VERSION 5.7 ;
  NOWIREEXTENSIONATPIN ON ;
  DIVIDERCHAR "/" ;
  BUSBITCHARS "[]" ;
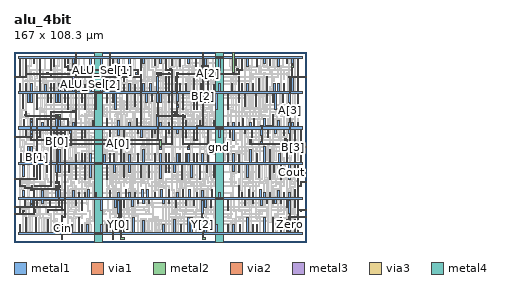
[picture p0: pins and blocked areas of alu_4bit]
MACRO alu_4bit
  CLASS BLOCK ;
  FOREIGN alu_4bit ;
  ORIGIN 1.900 4.000 ;
  SIZE 167.000 BY 108.300 ;
  PIN vdd
    USE POWER ;
    PORT
      LAYER metal1 ;
        RECT 1.200 81.600 2.000 86.200 ;
        RECT 4.400 81.600 5.200 86.200 ;
        RECT 7.600 81.600 8.400 86.200 ;
        RECT 12.400 81.600 13.200 90.200 ;
        RECT 15.600 81.600 16.400 85.800 ;
        RECT 18.800 81.600 19.600 86.200 ;
        RECT 20.400 81.600 21.200 86.200 ;
        RECT 23.600 81.600 24.400 86.200 ;
        RECT 26.800 81.600 27.600 86.200 ;
        RECT 31.600 81.600 32.400 90.200 ;
        RECT 33.200 81.600 34.000 86.200 ;
        RECT 38.000 81.600 38.800 85.800 ;
        RECT 41.200 81.600 42.000 86.200 ;
        RECT 47.600 81.600 48.400 86.200 ;
        RECT 50.800 81.600 51.600 85.800 ;
        RECT 57.200 81.600 58.000 90.200 ;
        RECT 60.400 81.600 61.200 85.800 ;
        RECT 63.600 81.600 64.400 86.200 ;
        RECT 66.800 81.600 67.600 85.800 ;
        RECT 70.000 81.600 70.800 86.200 ;
        RECT 71.600 81.600 72.400 86.200 ;
        RECT 75.400 81.600 76.200 86.200 ;
        RECT 79.600 81.600 80.400 90.200 ;
        RECT 84.400 81.600 85.200 90.200 ;
        RECT 86.000 81.600 86.800 90.200 ;
        RECT 90.200 81.600 91.000 86.200 ;
        RECT 92.400 81.600 93.200 86.200 ;
        RECT 95.600 81.600 96.400 86.200 ;
        RECT 100.400 81.600 101.200 89.000 ;
        RECT 104.200 81.600 105.000 86.200 ;
        RECT 108.400 81.600 109.200 90.200 ;
        RECT 111.600 81.600 112.400 85.800 ;
        RECT 114.800 81.600 115.600 86.200 ;
        RECT 121.800 81.600 122.600 86.200 ;
        RECT 126.000 81.600 126.800 90.200 ;
        RECT 127.600 81.600 128.400 86.200 ;
        RECT 130.800 81.600 131.600 86.200 ;
        RECT 134.000 81.600 134.800 86.200 ;
        RECT 137.200 81.600 138.000 89.000 ;
        RECT 142.000 81.600 142.800 90.200 ;
        RECT 146.200 81.600 147.000 86.200 ;
        RECT 148.400 81.600 149.200 86.200 ;
        RECT 151.600 81.600 152.400 86.200 ;
        RECT 156.400 81.600 157.200 90.200 ;
        RECT 159.600 81.600 160.400 90.200 ;
        RECT 0.400 80.400 162.800 81.600 ;
        RECT 2.800 72.200 3.600 80.400 ;
        RECT 6.000 75.800 6.800 80.400 ;
        RECT 7.600 75.800 8.400 80.400 ;
        RECT 10.800 71.800 11.600 80.400 ;
        RECT 17.200 75.800 18.000 80.400 ;
        RECT 18.800 75.800 19.600 80.400 ;
        RECT 22.000 75.800 22.800 80.400 ;
        RECT 23.600 75.800 24.400 80.400 ;
        RECT 26.800 75.800 27.600 80.400 ;
        RECT 28.400 71.800 29.200 80.400 ;
        RECT 33.200 75.800 34.000 80.400 ;
        RECT 36.400 75.800 37.200 80.400 ;
        RECT 38.000 71.800 38.800 80.400 ;
        RECT 44.400 71.800 45.200 80.400 ;
        RECT 50.800 75.800 51.600 80.400 ;
        RECT 54.000 75.800 54.800 80.400 ;
        RECT 55.600 71.800 56.400 80.400 ;
        RECT 62.000 71.800 62.800 80.400 ;
        RECT 66.800 73.000 67.600 80.400 ;
        RECT 70.000 75.800 70.800 80.400 ;
        RECT 73.200 75.800 74.000 80.400 ;
        RECT 76.400 76.200 77.200 80.400 ;
        RECT 79.600 75.800 80.400 80.400 ;
        RECT 81.200 75.800 82.000 80.400 ;
        RECT 86.000 75.800 86.800 80.400 ;
        RECT 87.600 75.800 88.400 80.400 ;
        RECT 90.800 76.200 91.600 80.400 ;
        RECT 94.000 71.800 94.800 80.400 ;
        RECT 100.400 71.800 101.200 80.400 ;
        RECT 102.000 71.800 102.800 80.400 ;
        RECT 106.200 75.800 107.000 80.400 ;
        RECT 109.000 75.800 109.800 80.400 ;
        RECT 113.200 71.800 114.000 80.400 ;
        RECT 119.600 71.800 120.400 80.400 ;
        RECT 126.000 75.800 126.800 80.400 ;
        RECT 129.200 73.000 130.000 80.400 ;
        RECT 135.600 73.000 136.400 80.400 ;
        RECT 142.000 75.800 142.800 80.400 ;
        RECT 145.200 75.800 146.000 80.400 ;
        RECT 146.800 71.800 147.600 80.400 ;
        RECT 151.000 75.800 151.800 80.400 ;
        RECT 154.800 75.800 155.600 80.400 ;
        RECT 159.600 71.800 160.400 80.400 ;
        RECT 1.800 41.600 2.600 46.200 ;
        RECT 6.000 41.600 6.800 50.200 ;
        RECT 7.600 41.600 8.400 50.200 ;
        RECT 12.400 41.600 13.200 46.200 ;
        RECT 15.600 41.600 16.400 46.200 ;
        RECT 18.800 41.600 19.600 46.200 ;
        RECT 23.600 41.600 24.400 49.000 ;
        RECT 26.800 41.600 27.600 50.200 ;
        RECT 33.200 41.600 34.000 45.800 ;
        RECT 36.400 41.600 37.200 46.200 ;
        RECT 38.000 41.600 38.800 46.200 ;
        RECT 41.200 41.600 42.000 46.200 ;
        RECT 49.200 41.600 50.000 45.800 ;
        RECT 52.400 41.600 53.200 46.200 ;
        RECT 54.600 41.600 55.400 46.200 ;
        RECT 58.800 41.600 59.600 50.200 ;
        RECT 60.400 41.600 61.200 46.200 ;
        RECT 63.600 41.600 64.400 45.800 ;
        RECT 68.400 41.600 69.200 46.200 ;
        RECT 71.600 41.600 72.400 49.000 ;
        RECT 78.000 41.600 78.800 46.200 ;
        RECT 81.200 41.600 82.000 46.200 ;
        RECT 84.400 41.600 85.200 46.200 ;
        RECT 86.000 41.600 86.800 46.200 ;
        RECT 90.800 41.600 91.600 46.200 ;
        RECT 92.400 41.600 93.200 46.200 ;
        RECT 95.600 41.600 96.400 46.200 ;
        RECT 97.200 41.600 98.000 46.200 ;
        RECT 100.400 41.600 101.200 46.200 ;
        RECT 102.000 41.600 102.800 46.200 ;
        RECT 105.200 41.600 106.000 46.200 ;
        RECT 108.400 41.600 109.200 46.200 ;
        RECT 119.600 41.600 120.400 49.000 ;
        RECT 122.800 41.600 123.600 46.200 ;
        RECT 126.000 41.600 126.800 45.800 ;
        RECT 132.400 41.600 133.200 49.000 ;
        RECT 136.200 41.600 137.000 46.200 ;
        RECT 140.400 41.600 141.200 50.200 ;
        RECT 143.600 41.600 144.400 49.000 ;
        RECT 149.000 41.600 149.800 46.200 ;
        RECT 153.200 41.600 154.000 50.200 ;
        RECT 158.000 41.600 158.800 50.200 ;
        RECT 161.200 41.600 162.000 46.200 ;
        RECT 0.400 40.400 162.800 41.600 ;
        RECT 3.000 39.800 3.800 40.400 ;
        RECT 2.800 33.200 3.800 39.800 ;
        RECT 9.000 33.200 10.000 40.400 ;
        RECT 12.400 31.800 13.200 40.400 ;
        RECT 16.600 35.800 17.400 40.400 ;
        RECT 18.800 35.800 19.600 40.400 ;
        RECT 22.000 35.800 22.800 40.400 ;
        RECT 23.600 35.800 24.400 40.400 ;
        RECT 26.800 35.800 27.600 40.400 ;
        RECT 29.000 35.800 29.800 40.400 ;
        RECT 33.200 31.800 34.000 40.400 ;
        RECT 38.000 31.800 38.800 40.400 ;
        RECT 41.200 33.000 42.000 40.400 ;
        RECT 50.800 31.800 51.600 40.400 ;
        RECT 55.000 35.800 55.800 40.400 ;
        RECT 60.400 33.000 61.200 40.400 ;
        RECT 63.600 35.800 64.400 40.400 ;
        RECT 70.000 33.000 70.800 40.400 ;
        RECT 74.800 33.000 75.600 40.400 ;
        RECT 81.200 32.200 82.000 40.400 ;
        RECT 84.400 35.800 85.200 40.400 ;
        RECT 86.000 35.800 86.800 40.400 ;
        RECT 89.200 35.800 90.000 40.400 ;
        RECT 93.400 31.800 94.200 40.400 ;
        RECT 98.800 33.000 99.600 40.400 ;
        RECT 103.600 31.800 104.400 40.400 ;
        RECT 107.800 35.800 108.600 40.400 ;
        RECT 111.600 33.000 112.400 40.400 ;
        RECT 122.800 36.200 123.600 40.400 ;
        RECT 126.000 35.800 126.800 40.400 ;
        RECT 130.800 33.000 131.600 40.400 ;
        RECT 137.200 33.000 138.000 40.400 ;
        RECT 143.600 31.800 144.400 40.400 ;
        RECT 145.800 35.800 146.600 40.400 ;
        RECT 150.000 31.800 150.800 40.400 ;
        RECT 154.800 31.800 155.600 40.400 ;
        RECT 158.000 33.000 158.800 40.400 ;
        RECT 1.200 1.600 2.000 6.200 ;
        RECT 4.400 1.600 5.200 9.800 ;
        RECT 10.200 1.600 11.000 10.200 ;
        RECT 17.200 1.600 18.000 9.000 ;
        RECT 22.000 1.600 22.800 5.800 ;
        RECT 25.200 1.600 26.000 6.200 ;
        RECT 26.800 1.600 27.600 6.200 ;
        RECT 30.600 1.600 31.400 6.200 ;
        RECT 34.800 1.600 35.600 10.200 ;
        RECT 36.400 1.600 37.200 6.200 ;
        RECT 39.600 1.600 40.400 5.800 ;
        RECT 47.600 1.600 48.400 6.200 ;
        RECT 50.800 1.600 51.600 5.800 ;
        RECT 55.600 1.600 56.400 9.000 ;
        RECT 60.400 1.600 61.200 9.000 ;
        RECT 65.800 1.600 66.600 10.200 ;
        RECT 71.600 1.600 72.400 8.200 ;
        RECT 82.800 1.600 83.600 6.200 ;
        RECT 89.200 1.600 90.000 9.000 ;
        RECT 93.000 1.600 93.800 6.200 ;
        RECT 97.200 1.600 98.000 10.200 ;
        RECT 98.800 1.600 99.600 10.200 ;
        RECT 103.000 1.600 103.800 6.200 ;
        RECT 106.800 1.600 107.600 9.000 ;
        RECT 110.000 1.600 110.800 6.200 ;
        RECT 113.200 1.600 114.000 6.200 ;
        RECT 119.600 1.600 120.400 6.200 ;
        RECT 122.800 1.600 123.600 5.800 ;
        RECT 126.600 1.600 127.400 6.200 ;
        RECT 130.800 1.600 131.600 10.200 ;
        RECT 134.000 1.600 134.800 6.200 ;
        RECT 136.200 1.600 137.000 6.200 ;
        RECT 140.400 1.600 141.200 10.200 ;
        RECT 145.200 1.600 146.000 10.200 ;
        RECT 150.000 1.600 150.800 10.200 ;
        RECT 153.200 1.600 154.000 9.000 ;
        RECT 158.000 1.600 158.800 9.000 ;
        RECT 0.400 0.400 162.800 1.600 ;
      LAYER via1 ;
        RECT 44.600 80.600 45.400 81.400 ;
        RECT 46.000 80.600 46.800 81.400 ;
        RECT 47.400 80.600 48.200 81.400 ;
        RECT 44.600 40.600 45.400 41.400 ;
        RECT 46.000 40.600 46.800 41.400 ;
        RECT 47.400 40.600 48.200 41.400 ;
        RECT 44.600 0.600 45.400 1.400 ;
        RECT 46.000 0.600 46.800 1.400 ;
        RECT 47.400 0.600 48.200 1.400 ;
      LAYER metal2 ;
        RECT 44.000 80.600 48.800 81.400 ;
        RECT 44.000 40.600 48.800 41.400 ;
        RECT 44.000 0.600 48.800 1.400 ;
      LAYER via2 ;
        RECT 44.600 80.600 45.400 81.400 ;
        RECT 46.000 80.600 46.800 81.400 ;
        RECT 47.400 80.600 48.200 81.400 ;
        RECT 44.600 40.600 45.400 41.400 ;
        RECT 46.000 40.600 46.800 41.400 ;
        RECT 47.400 40.600 48.200 41.400 ;
        RECT 44.600 0.600 45.400 1.400 ;
        RECT 46.000 0.600 46.800 1.400 ;
        RECT 47.400 0.600 48.200 1.400 ;
      LAYER metal3 ;
        RECT 44.000 80.400 48.800 81.600 ;
        RECT 44.000 40.400 48.800 41.600 ;
        RECT 44.000 0.400 48.800 1.600 ;
      LAYER via3 ;
        RECT 44.400 80.600 45.200 81.400 ;
        RECT 46.000 80.600 46.800 81.400 ;
        RECT 47.600 80.600 48.400 81.400 ;
        RECT 44.400 40.600 45.200 41.400 ;
        RECT 46.000 40.600 46.800 41.400 ;
        RECT 47.600 40.600 48.400 41.400 ;
        RECT 44.400 0.600 45.200 1.400 ;
        RECT 46.000 0.600 46.800 1.400 ;
        RECT 47.600 0.600 48.400 1.400 ;
      LAYER metal4 ;
        RECT 44.000 -4.000 48.800 104.000 ;
    END
  END vdd
  PIN gnd
    USE GROUND ;
    PORT
      LAYER metal1 ;
        RECT 0.400 100.400 162.800 101.600 ;
        RECT 1.200 97.800 2.000 100.400 ;
        RECT 4.400 95.800 5.200 100.400 ;
        RECT 9.200 97.800 10.000 100.400 ;
        RECT 12.400 97.800 13.200 100.400 ;
        RECT 18.800 93.800 19.600 100.400 ;
        RECT 20.400 95.800 21.200 100.400 ;
        RECT 26.800 97.800 27.600 100.400 ;
        RECT 28.400 97.800 29.200 100.400 ;
        RECT 31.600 97.800 32.400 100.400 ;
        RECT 33.200 97.800 34.000 100.400 ;
        RECT 41.200 93.800 42.000 100.400 ;
        RECT 47.600 93.800 48.400 100.400 ;
        RECT 54.000 97.800 54.800 100.400 ;
        RECT 57.200 97.800 58.000 100.400 ;
        RECT 63.600 93.800 64.400 100.400 ;
        RECT 70.000 93.800 70.800 100.400 ;
        RECT 71.600 97.800 72.400 100.400 ;
        RECT 78.000 96.600 78.800 100.400 ;
        RECT 81.200 97.800 82.000 100.400 ;
        RECT 84.400 97.800 85.200 100.400 ;
        RECT 87.600 96.600 88.400 100.400 ;
        RECT 92.400 95.800 93.200 100.400 ;
        RECT 97.200 97.800 98.000 100.400 ;
        RECT 101.400 95.800 102.200 100.400 ;
        RECT 106.800 96.600 107.600 100.400 ;
        RECT 114.800 93.800 115.600 100.400 ;
        RECT 124.400 96.600 125.200 100.400 ;
        RECT 127.600 97.800 128.400 100.400 ;
        RECT 130.800 95.800 131.600 100.400 ;
        RECT 136.200 95.800 137.000 100.400 ;
        RECT 140.400 97.800 141.200 100.400 ;
        RECT 143.600 96.600 144.400 100.400 ;
        RECT 148.400 95.800 149.200 100.400 ;
        RECT 153.200 97.800 154.000 100.400 ;
        RECT 156.400 97.800 157.200 100.400 ;
        RECT 159.600 95.800 160.400 100.400 ;
        RECT 3.400 61.600 4.200 66.000 ;
        RECT 7.600 61.600 8.400 64.200 ;
        RECT 10.800 61.600 11.600 64.200 ;
        RECT 14.000 61.600 14.800 64.200 ;
        RECT 17.200 61.600 18.000 64.200 ;
        RECT 22.000 61.600 22.800 66.200 ;
        RECT 23.600 61.600 24.400 66.200 ;
        RECT 28.400 61.600 29.200 64.200 ;
        RECT 31.600 61.600 32.400 64.200 ;
        RECT 33.200 61.600 34.000 66.200 ;
        RECT 42.800 61.600 43.600 65.400 ;
        RECT 50.800 61.600 51.600 66.200 ;
        RECT 57.200 61.600 58.000 65.400 ;
        RECT 63.600 61.600 64.400 64.200 ;
        RECT 67.800 61.600 68.600 66.200 ;
        RECT 70.000 61.600 70.800 66.200 ;
        RECT 79.600 61.600 80.400 68.200 ;
        RECT 81.200 61.600 82.000 64.200 ;
        RECT 86.000 61.600 86.800 64.200 ;
        RECT 87.600 61.600 88.400 68.200 ;
        RECT 95.600 61.600 96.400 65.400 ;
        RECT 103.600 61.600 104.400 65.400 ;
        RECT 111.600 61.600 112.400 65.400 ;
        RECT 119.600 61.600 120.400 64.200 ;
        RECT 122.800 61.600 123.600 64.200 ;
        RECT 126.000 61.600 126.800 64.200 ;
        RECT 128.200 61.600 129.000 66.200 ;
        RECT 132.400 61.600 133.200 64.200 ;
        RECT 134.400 61.600 135.200 66.200 ;
        RECT 140.400 61.600 141.200 66.200 ;
        RECT 145.200 61.600 146.000 66.200 ;
        RECT 148.400 61.600 149.200 65.400 ;
        RECT 154.800 61.600 155.600 64.200 ;
        RECT 156.400 61.600 157.200 64.200 ;
        RECT 159.600 61.600 160.400 64.200 ;
        RECT 0.400 60.400 162.800 61.600 ;
        RECT 4.400 56.600 5.200 60.400 ;
        RECT 7.600 57.800 8.400 60.400 ;
        RECT 10.800 57.800 11.600 60.400 ;
        RECT 12.400 57.800 13.200 60.400 ;
        RECT 18.800 55.800 19.600 60.400 ;
        RECT 20.400 57.800 21.200 60.400 ;
        RECT 24.600 55.800 25.400 60.400 ;
        RECT 26.800 57.800 27.600 60.400 ;
        RECT 30.000 57.800 30.800 60.400 ;
        RECT 36.400 53.800 37.200 60.400 ;
        RECT 38.000 55.800 38.800 60.400 ;
        RECT 52.400 53.800 53.200 60.400 ;
        RECT 57.200 56.600 58.000 60.400 ;
        RECT 60.400 53.800 61.200 60.400 ;
        RECT 68.400 57.800 69.200 60.400 ;
        RECT 70.400 55.800 71.200 60.400 ;
        RECT 76.400 55.800 77.200 60.400 ;
        RECT 78.000 57.800 78.800 60.400 ;
        RECT 84.400 55.800 85.200 60.400 ;
        RECT 86.000 57.800 86.800 60.400 ;
        RECT 90.800 57.800 91.600 60.400 ;
        RECT 95.600 55.800 96.400 60.400 ;
        RECT 100.400 55.800 101.200 60.400 ;
        RECT 102.000 57.800 102.800 60.400 ;
        RECT 108.400 55.800 109.200 60.400 ;
        RECT 114.800 55.800 115.600 60.400 ;
        RECT 120.800 55.800 121.600 60.400 ;
        RECT 122.800 53.800 123.600 60.400 ;
        RECT 129.200 57.800 130.000 60.400 ;
        RECT 133.400 55.800 134.200 60.400 ;
        RECT 138.800 56.600 139.600 60.400 ;
        RECT 142.600 55.800 143.400 60.400 ;
        RECT 146.800 57.800 147.600 60.400 ;
        RECT 151.600 56.600 152.400 60.400 ;
        RECT 154.800 57.800 155.600 60.400 ;
        RECT 158.000 57.800 158.800 60.400 ;
        RECT 161.200 57.800 162.000 60.400 ;
        RECT 2.800 22.200 3.800 25.600 ;
        RECT 3.000 21.600 3.800 22.200 ;
        RECT 9.000 21.600 10.000 25.600 ;
        RECT 14.000 21.600 14.800 25.400 ;
        RECT 22.000 21.600 22.800 26.200 ;
        RECT 23.600 21.600 24.400 26.200 ;
        RECT 31.600 21.600 32.400 25.400 ;
        RECT 34.800 21.600 35.600 24.200 ;
        RECT 38.000 21.600 38.800 24.200 ;
        RECT 40.200 21.600 41.000 26.200 ;
        RECT 44.400 21.600 45.200 24.200 ;
        RECT 52.400 21.600 53.200 25.400 ;
        RECT 57.200 21.600 58.000 24.200 ;
        RECT 61.400 21.600 62.200 26.200 ;
        RECT 63.600 21.600 64.400 24.200 ;
        RECT 66.800 21.600 67.600 24.200 ;
        RECT 71.000 21.600 71.800 26.200 ;
        RECT 73.800 21.600 74.600 26.200 ;
        RECT 78.000 21.600 78.800 24.200 ;
        RECT 81.800 21.600 82.600 26.000 ;
        RECT 86.000 21.600 86.800 26.200 ;
        RECT 90.800 21.600 91.600 24.200 ;
        RECT 94.000 21.600 94.800 25.800 ;
        RECT 97.800 21.600 98.600 26.200 ;
        RECT 102.000 21.600 102.800 24.200 ;
        RECT 105.200 21.600 106.000 25.400 ;
        RECT 110.600 21.600 111.400 26.200 ;
        RECT 114.800 21.600 115.600 24.200 ;
        RECT 126.000 21.600 126.800 28.200 ;
        RECT 127.600 21.600 128.400 24.200 ;
        RECT 131.800 21.600 132.600 26.200 ;
        RECT 134.000 21.600 134.800 24.200 ;
        RECT 138.200 21.600 139.000 26.200 ;
        RECT 140.400 21.600 141.200 24.200 ;
        RECT 143.600 21.600 144.400 24.200 ;
        RECT 148.400 21.600 149.200 25.400 ;
        RECT 151.600 21.600 152.400 24.200 ;
        RECT 154.800 21.600 155.600 24.200 ;
        RECT 158.000 21.600 158.800 26.200 ;
        RECT 0.400 20.400 162.800 21.600 ;
        RECT 3.800 16.000 4.600 20.400 ;
        RECT 7.600 17.800 8.400 20.400 ;
        RECT 10.800 16.200 11.600 20.400 ;
        RECT 14.000 17.800 14.800 20.400 ;
        RECT 18.200 15.800 19.000 20.400 ;
        RECT 25.200 13.800 26.000 20.400 ;
        RECT 26.800 17.800 27.600 20.400 ;
        RECT 33.200 16.600 34.000 20.400 ;
        RECT 36.400 13.800 37.200 20.400 ;
        RECT 47.600 13.800 48.400 20.400 ;
        RECT 55.600 15.800 56.400 20.400 ;
        RECT 60.400 15.800 61.200 20.400 ;
        RECT 65.200 16.200 66.000 20.400 ;
        RECT 68.400 17.800 69.200 20.400 ;
        RECT 71.600 17.800 72.400 20.400 ;
        RECT 74.800 18.200 75.600 20.400 ;
        RECT 82.800 17.800 83.600 20.400 ;
        RECT 86.000 17.800 86.800 20.400 ;
        RECT 90.200 15.800 91.000 20.400 ;
        RECT 95.600 16.600 96.400 20.400 ;
        RECT 100.400 16.600 101.200 20.400 ;
        RECT 106.800 15.800 107.600 20.400 ;
        RECT 110.000 15.800 110.800 20.400 ;
        RECT 119.600 13.800 120.400 20.400 ;
        RECT 129.200 16.600 130.000 20.400 ;
        RECT 134.000 17.800 134.800 20.400 ;
        RECT 138.800 16.600 139.600 20.400 ;
        RECT 142.000 17.800 142.800 20.400 ;
        RECT 145.200 17.800 146.000 20.400 ;
        RECT 146.800 17.800 147.600 20.400 ;
        RECT 150.000 17.800 150.800 20.400 ;
        RECT 153.200 15.800 154.000 20.400 ;
        RECT 158.000 15.800 158.800 20.400 ;
      LAYER via1 ;
        RECT 113.400 100.600 114.200 101.400 ;
        RECT 114.800 100.600 115.600 101.400 ;
        RECT 116.200 100.600 117.000 101.400 ;
        RECT 113.400 60.600 114.200 61.400 ;
        RECT 114.800 60.600 115.600 61.400 ;
        RECT 116.200 60.600 117.000 61.400 ;
        RECT 113.400 20.600 114.200 21.400 ;
        RECT 114.800 20.600 115.600 21.400 ;
        RECT 116.200 20.600 117.000 21.400 ;
      LAYER metal2 ;
        RECT 112.800 100.600 117.600 101.400 ;
        RECT 112.800 60.600 117.600 61.400 ;
        RECT 112.800 20.600 117.600 21.400 ;
      LAYER via2 ;
        RECT 113.400 100.600 114.200 101.400 ;
        RECT 114.800 100.600 115.600 101.400 ;
        RECT 116.200 100.600 117.000 101.400 ;
        RECT 113.400 60.600 114.200 61.400 ;
        RECT 114.800 60.600 115.600 61.400 ;
        RECT 116.200 60.600 117.000 61.400 ;
        RECT 113.400 20.600 114.200 21.400 ;
        RECT 114.800 20.600 115.600 21.400 ;
        RECT 116.200 20.600 117.000 21.400 ;
      LAYER metal3 ;
        RECT 112.800 100.400 117.600 101.600 ;
        RECT 112.800 60.400 117.600 61.600 ;
        RECT 112.800 20.400 117.600 21.600 ;
      LAYER via3 ;
        RECT 113.200 100.600 114.000 101.400 ;
        RECT 114.800 100.600 115.600 101.400 ;
        RECT 116.400 100.600 117.200 101.400 ;
        RECT 113.200 60.600 114.000 61.400 ;
        RECT 114.800 60.600 115.600 61.400 ;
        RECT 116.400 60.600 117.200 61.400 ;
        RECT 113.200 20.600 114.000 21.400 ;
        RECT 114.800 20.600 115.600 21.400 ;
        RECT 116.400 20.600 117.200 21.400 ;
      LAYER metal4 ;
        RECT 112.800 -4.000 117.600 104.000 ;
    END
  END gnd
  PIN A[0]
    PORT
      LAYER metal1 ;
        RECT 84.400 95.600 85.200 97.200 ;
        RECT 84.500 94.300 85.100 95.600 ;
        RECT 86.800 94.400 87.600 94.800 ;
        RECT 86.000 94.300 87.600 94.400 ;
        RECT 84.500 93.800 87.600 94.300 ;
        RECT 84.500 93.700 86.800 93.800 ;
        RECT 86.000 93.600 86.800 93.700 ;
        RECT 87.600 70.800 88.400 72.400 ;
        RECT 7.600 64.800 8.400 66.400 ;
        RECT 84.400 53.600 85.200 55.200 ;
        RECT 30.000 50.800 30.800 52.400 ;
        RECT 26.800 31.600 27.600 33.200 ;
        RECT 3.200 13.800 4.000 14.000 ;
        RECT 3.000 13.200 4.000 13.800 ;
        RECT 9.200 13.600 10.200 14.400 ;
        RECT 3.000 12.400 3.600 13.200 ;
        RECT 9.600 12.800 10.400 13.600 ;
        RECT 2.800 11.600 3.600 12.400 ;
      LAYER via1 ;
        RECT 87.600 71.600 88.400 72.400 ;
        RECT 7.600 65.600 8.400 66.400 ;
        RECT 30.000 51.600 30.800 52.400 ;
      LAYER metal2 ;
        RECT 86.000 94.300 86.800 94.400 ;
        RECT 86.000 93.700 88.300 94.300 ;
        RECT 86.000 93.600 86.800 93.700 ;
        RECT 87.700 72.400 88.300 93.700 ;
        RECT 87.600 71.600 88.400 72.400 ;
        RECT 7.600 65.600 8.400 66.400 ;
        RECT 7.700 60.400 8.300 65.600 ;
        RECT 7.600 59.600 8.400 60.400 ;
        RECT 30.000 59.600 30.800 60.400 ;
        RECT 30.100 52.400 30.700 59.600 ;
        RECT 84.400 53.600 85.200 54.400 ;
        RECT 84.500 52.400 85.100 53.600 ;
        RECT 87.700 52.400 88.300 71.600 ;
        RECT 26.800 51.600 27.600 52.400 ;
        RECT 30.000 51.600 30.800 52.400 ;
        RECT 84.400 51.600 85.200 52.400 ;
        RECT 87.600 51.600 88.400 52.400 ;
        RECT 26.900 32.400 27.500 51.600 ;
        RECT 26.800 31.600 27.600 32.400 ;
        RECT 26.900 20.400 27.500 31.600 ;
        RECT 9.200 19.600 10.000 20.400 ;
        RECT 26.800 19.600 27.600 20.400 ;
        RECT 9.300 14.400 9.900 19.600 ;
        RECT 9.200 13.600 10.000 14.400 ;
        RECT 9.300 12.400 9.900 13.600 ;
        RECT 2.800 11.600 3.600 12.400 ;
        RECT 9.200 11.600 10.000 12.400 ;
      LAYER metal3 ;
        RECT 7.600 60.300 8.400 60.400 ;
        RECT 30.000 60.300 30.800 60.400 ;
        RECT 7.600 59.700 30.800 60.300 ;
        RECT 7.600 59.600 8.400 59.700 ;
        RECT 30.000 59.600 30.800 59.700 ;
        RECT 26.800 52.300 27.600 52.400 ;
        RECT 30.000 52.300 30.800 52.400 ;
        RECT 84.400 52.300 85.200 52.400 ;
        RECT 87.600 52.300 88.400 52.400 ;
        RECT 26.800 51.700 88.400 52.300 ;
        RECT 26.800 51.600 27.600 51.700 ;
        RECT 30.000 51.600 30.800 51.700 ;
        RECT 84.400 51.600 85.200 51.700 ;
        RECT 87.600 51.600 88.400 51.700 ;
        RECT 9.200 20.300 10.000 20.400 ;
        RECT 26.800 20.300 27.600 20.400 ;
        RECT 9.200 19.700 27.600 20.300 ;
        RECT 9.200 19.600 10.000 19.700 ;
        RECT 26.800 19.600 27.600 19.700 ;
        RECT 2.800 12.300 3.600 12.400 ;
        RECT 9.200 12.300 10.000 12.400 ;
        RECT -1.900 11.700 10.000 12.300 ;
        RECT 2.800 11.600 3.600 11.700 ;
        RECT 9.200 11.600 10.000 11.700 ;
    END
  END A[0]
  PIN A[1]
    PORT
      LAYER metal1 ;
        RECT 79.600 92.300 80.400 92.400 ;
        RECT 81.200 92.300 82.000 92.400 ;
        RECT 79.600 91.700 82.000 92.300 ;
        RECT 79.600 91.600 80.400 91.700 ;
        RECT 81.200 90.800 82.000 91.700 ;
        RECT 86.000 92.300 86.800 92.400 ;
        RECT 87.600 92.300 88.400 93.200 ;
        RECT 86.000 91.700 88.400 92.300 ;
        RECT 86.000 91.600 86.800 91.700 ;
        RECT 87.600 91.600 88.400 91.700 ;
        RECT 31.600 69.600 32.400 71.200 ;
        RECT 89.200 69.600 90.800 70.400 ;
        RECT 17.200 64.800 18.000 66.400 ;
        RECT 7.600 55.600 8.400 57.200 ;
        RECT 18.800 53.600 19.600 55.200 ;
        RECT 81.200 48.800 82.000 50.400 ;
        RECT 18.800 31.600 19.600 33.200 ;
        RECT 10.000 27.600 11.600 28.400 ;
      LAYER via1 ;
        RECT 17.200 65.600 18.000 66.400 ;
        RECT 81.200 49.600 82.000 50.400 ;
        RECT 10.800 27.600 11.600 28.400 ;
      LAYER metal2 ;
        RECT 79.600 91.600 80.400 92.400 ;
        RECT 86.000 91.600 86.800 92.400 ;
        RECT 18.800 69.600 19.600 70.400 ;
        RECT 31.600 69.600 32.400 70.400 ;
        RECT 17.200 66.300 18.000 66.400 ;
        RECT 18.900 66.300 19.500 69.600 ;
        RECT 79.700 68.400 80.300 91.600 ;
        RECT 89.200 69.600 90.000 70.400 ;
        RECT 89.300 68.400 89.900 69.600 ;
        RECT 79.600 67.600 80.400 68.400 ;
        RECT 89.200 67.600 90.000 68.400 ;
        RECT 17.200 65.700 19.500 66.300 ;
        RECT 17.200 65.600 18.000 65.700 ;
        RECT 7.600 55.600 8.400 56.400 ;
        RECT 7.700 54.400 8.300 55.600 ;
        RECT 18.900 54.400 19.500 65.700 ;
        RECT 79.700 54.400 80.300 67.600 ;
        RECT 7.600 53.600 8.400 54.400 ;
        RECT 18.800 53.600 19.600 54.400 ;
        RECT 79.600 53.600 80.400 54.400 ;
        RECT 81.200 53.600 82.000 54.400 ;
        RECT 18.900 32.400 19.500 53.600 ;
        RECT 81.300 50.400 81.900 53.600 ;
        RECT 81.200 49.600 82.000 50.400 ;
        RECT 18.800 31.600 19.600 32.400 ;
        RECT 18.900 28.400 19.500 31.600 ;
        RECT 10.800 27.600 11.600 28.400 ;
        RECT 18.800 27.600 19.600 28.400 ;
      LAYER metal3 ;
        RECT 79.600 92.300 80.400 92.400 ;
        RECT 86.000 92.300 86.800 92.400 ;
        RECT 79.600 91.700 86.800 92.300 ;
        RECT 79.600 91.600 80.400 91.700 ;
        RECT 86.000 91.600 86.800 91.700 ;
        RECT 18.800 70.300 19.600 70.400 ;
        RECT 31.600 70.300 32.400 70.400 ;
        RECT 18.800 69.700 32.400 70.300 ;
        RECT 18.800 69.600 19.600 69.700 ;
        RECT 31.600 69.600 32.400 69.700 ;
        RECT 79.600 68.300 80.400 68.400 ;
        RECT 89.200 68.300 90.000 68.400 ;
        RECT 79.600 67.700 90.000 68.300 ;
        RECT 79.600 67.600 80.400 67.700 ;
        RECT 89.200 67.600 90.000 67.700 ;
        RECT 7.600 56.300 8.400 56.400 ;
        RECT -1.900 55.700 8.400 56.300 ;
        RECT 7.600 55.600 8.400 55.700 ;
        RECT 7.600 54.300 8.400 54.400 ;
        RECT 18.800 54.300 19.600 54.400 ;
        RECT 79.600 54.300 80.400 54.400 ;
        RECT 81.200 54.300 82.000 54.400 ;
        RECT 7.600 53.700 82.000 54.300 ;
        RECT 7.600 53.600 8.400 53.700 ;
        RECT 18.800 53.600 19.600 53.700 ;
        RECT 79.600 53.600 80.400 53.700 ;
        RECT 81.200 53.600 82.000 53.700 ;
        RECT 10.800 28.300 11.600 28.400 ;
        RECT 18.800 28.300 19.600 28.400 ;
        RECT 10.800 27.700 19.600 28.300 ;
        RECT 10.800 27.600 11.600 27.700 ;
        RECT 18.800 27.600 19.600 27.700 ;
    END
  END A[1]
  PIN A[2]
    PORT
      LAYER metal1 ;
        RECT 127.600 95.600 128.400 97.200 ;
        RECT 125.200 94.400 126.000 94.800 ;
        RECT 125.200 94.300 126.800 94.400 ;
        RECT 127.700 94.300 128.300 95.600 ;
        RECT 125.200 93.800 128.300 94.300 ;
        RECT 126.000 93.700 128.300 93.800 ;
        RECT 126.000 93.600 126.800 93.700 ;
        RECT 106.800 91.600 107.600 93.200 ;
        RECT 90.800 90.200 91.600 90.400 ;
        RECT 90.200 89.600 91.600 90.200 ;
        RECT 90.200 88.400 90.800 89.600 ;
        RECT 90.000 87.600 90.800 88.400 ;
        RECT 90.800 72.800 91.600 74.400 ;
        RECT 94.000 68.200 94.800 68.400 ;
        RECT 94.000 67.600 95.600 68.200 ;
        RECT 94.800 67.200 95.600 67.600 ;
        RECT 108.400 53.600 109.200 55.200 ;
        RECT 97.200 48.800 98.000 50.400 ;
      LAYER via1 ;
        RECT 90.800 89.600 91.600 90.400 ;
        RECT 90.800 73.600 91.600 74.400 ;
        RECT 97.200 49.600 98.000 50.400 ;
      LAYER metal2 ;
        RECT 122.900 92.400 123.500 104.300 ;
        RECT 126.000 93.600 126.800 94.400 ;
        RECT 126.100 92.400 126.700 93.600 ;
        RECT 90.800 91.600 91.600 92.400 ;
        RECT 106.800 91.600 107.600 92.400 ;
        RECT 122.800 91.600 123.600 92.400 ;
        RECT 126.000 91.600 126.800 92.400 ;
        RECT 90.900 90.400 91.500 91.600 ;
        RECT 90.800 89.600 91.600 90.400 ;
        RECT 90.900 74.400 91.500 89.600 ;
        RECT 90.800 73.600 91.600 74.400 ;
        RECT 90.900 68.400 91.500 73.600 ;
        RECT 90.800 67.600 91.600 68.400 ;
        RECT 94.000 67.600 94.800 68.400 ;
        RECT 94.100 52.400 94.700 67.600 ;
        RECT 108.400 53.600 109.200 54.400 ;
        RECT 108.500 52.400 109.100 53.600 ;
        RECT 94.000 51.600 94.800 52.400 ;
        RECT 97.200 51.600 98.000 52.400 ;
        RECT 108.400 51.600 109.200 52.400 ;
        RECT 97.300 50.400 97.900 51.600 ;
        RECT 97.200 49.600 98.000 50.400 ;
      LAYER metal3 ;
        RECT 90.800 92.300 91.600 92.400 ;
        RECT 106.800 92.300 107.600 92.400 ;
        RECT 122.800 92.300 123.600 92.400 ;
        RECT 126.000 92.300 126.800 92.400 ;
        RECT 90.800 91.700 126.800 92.300 ;
        RECT 90.800 91.600 91.600 91.700 ;
        RECT 106.800 91.600 107.600 91.700 ;
        RECT 122.800 91.600 123.600 91.700 ;
        RECT 126.000 91.600 126.800 91.700 ;
        RECT 90.800 68.300 91.600 68.400 ;
        RECT 94.000 68.300 94.800 68.400 ;
        RECT 90.800 67.700 94.800 68.300 ;
        RECT 90.800 67.600 91.600 67.700 ;
        RECT 94.000 67.600 94.800 67.700 ;
        RECT 94.000 52.300 94.800 52.400 ;
        RECT 97.200 52.300 98.000 52.400 ;
        RECT 108.400 52.300 109.200 52.400 ;
        RECT 94.000 51.700 109.200 52.300 ;
        RECT 94.000 51.600 94.800 51.700 ;
        RECT 97.200 51.600 98.000 51.700 ;
        RECT 108.400 51.600 109.200 51.700 ;
    END
  END A[2]
  PIN A[3]
    PORT
      LAYER metal1 ;
        RECT 156.400 95.600 157.200 97.200 ;
        RECT 159.600 93.600 160.400 95.200 ;
        RECT 145.200 66.800 146.000 68.400 ;
        RECT 132.400 52.800 133.200 54.400 ;
        RECT 138.800 51.600 139.600 53.200 ;
        RECT 151.600 52.300 152.400 53.200 ;
        RECT 154.800 52.300 155.600 52.400 ;
        RECT 151.600 51.700 155.600 52.300 ;
        RECT 151.600 51.600 152.400 51.700 ;
        RECT 154.800 50.800 155.600 51.700 ;
      LAYER via1 ;
        RECT 145.200 67.600 146.000 68.400 ;
        RECT 132.400 53.600 133.200 54.400 ;
        RECT 154.800 51.600 155.600 52.400 ;
      LAYER metal2 ;
        RECT 156.400 95.600 157.200 96.400 ;
        RECT 156.500 90.400 157.100 95.600 ;
        RECT 159.600 93.600 160.400 94.400 ;
        RECT 159.700 90.400 160.300 93.600 ;
        RECT 154.800 89.600 155.600 90.400 ;
        RECT 156.400 89.600 157.200 90.400 ;
        RECT 159.600 89.600 160.400 90.400 ;
        RECT 145.200 67.600 146.000 68.400 ;
        RECT 145.300 62.400 145.900 67.600 ;
        RECT 138.800 61.600 139.600 62.400 ;
        RECT 145.200 61.600 146.000 62.400 ;
        RECT 132.400 53.600 133.200 54.400 ;
        RECT 132.500 52.400 133.100 53.600 ;
        RECT 138.900 52.400 139.500 61.600 ;
        RECT 154.900 52.400 155.500 89.600 ;
        RECT 132.400 51.600 133.200 52.400 ;
        RECT 138.800 51.600 139.600 52.400 ;
        RECT 151.600 51.600 152.400 52.400 ;
        RECT 154.800 51.600 155.600 52.400 ;
      LAYER metal3 ;
        RECT 154.800 90.300 155.600 90.400 ;
        RECT 156.400 90.300 157.200 90.400 ;
        RECT 159.600 90.300 160.400 90.400 ;
        RECT 154.800 89.700 165.100 90.300 ;
        RECT 154.800 89.600 155.600 89.700 ;
        RECT 156.400 89.600 157.200 89.700 ;
        RECT 159.600 89.600 160.400 89.700 ;
        RECT 138.800 62.300 139.600 62.400 ;
        RECT 145.200 62.300 146.000 62.400 ;
        RECT 138.800 61.700 146.000 62.300 ;
        RECT 138.800 61.600 139.600 61.700 ;
        RECT 145.200 61.600 146.000 61.700 ;
        RECT 132.400 52.300 133.200 52.400 ;
        RECT 138.800 52.300 139.600 52.400 ;
        RECT 151.600 52.300 152.400 52.400 ;
        RECT 132.400 51.700 152.400 52.300 ;
        RECT 132.400 51.600 133.200 51.700 ;
        RECT 138.800 51.600 139.600 51.700 ;
        RECT 151.600 51.600 152.400 51.700 ;
    END
  END A[3]
  PIN B[0]
    PORT
      LAYER metal1 ;
        RECT 4.400 69.600 5.200 70.400 ;
        RECT 4.400 68.800 5.000 69.600 ;
        RECT 4.000 68.000 5.200 68.800 ;
        RECT 22.000 66.800 22.800 68.400 ;
        RECT 26.800 55.600 27.600 57.200 ;
        RECT 22.000 30.300 22.800 30.400 ;
        RECT 22.000 29.700 24.300 30.300 ;
        RECT 22.000 29.600 22.800 29.700 ;
        RECT 23.700 28.400 24.300 29.700 ;
        RECT 23.600 26.800 24.400 28.400 ;
        RECT 7.600 15.600 8.400 17.200 ;
        RECT 1.200 12.800 2.000 14.400 ;
      LAYER via1 ;
        RECT 4.400 68.000 5.200 68.800 ;
        RECT 22.000 67.600 22.800 68.400 ;
        RECT 23.600 27.600 24.400 28.400 ;
        RECT 1.200 13.600 2.000 14.400 ;
      LAYER metal2 ;
        RECT 4.400 67.600 5.200 68.800 ;
        RECT 22.000 67.600 22.800 68.400 ;
        RECT 22.100 58.400 22.700 67.600 ;
        RECT 22.000 57.600 22.800 58.400 ;
        RECT 26.800 57.600 27.600 58.400 ;
        RECT 22.100 30.400 22.700 57.600 ;
        RECT 26.900 56.400 27.500 57.600 ;
        RECT 26.800 55.600 27.600 56.400 ;
        RECT 22.000 29.600 22.800 30.400 ;
        RECT 23.600 27.600 24.400 28.400 ;
        RECT 23.700 16.400 24.300 27.600 ;
        RECT 1.200 15.600 2.000 16.400 ;
        RECT 7.600 15.600 8.400 16.400 ;
        RECT 23.600 15.600 24.400 16.400 ;
        RECT 1.300 14.400 1.900 15.600 ;
        RECT 1.200 13.600 2.000 14.400 ;
      LAYER metal3 ;
        RECT 4.400 68.300 5.200 68.400 ;
        RECT 22.000 68.300 22.800 68.400 ;
        RECT 4.400 67.700 22.800 68.300 ;
        RECT 4.400 67.600 5.200 67.700 ;
        RECT 22.000 67.600 22.800 67.700 ;
        RECT 22.000 58.300 22.800 58.400 ;
        RECT 26.800 58.300 27.600 58.400 ;
        RECT 22.000 57.700 27.600 58.300 ;
        RECT 22.000 57.600 22.800 57.700 ;
        RECT 26.800 57.600 27.600 57.700 ;
        RECT 1.200 16.300 2.000 16.400 ;
        RECT 7.600 16.300 8.400 16.400 ;
        RECT 23.600 16.300 24.400 16.400 ;
        RECT -1.900 15.700 24.400 16.300 ;
        RECT 1.200 15.600 2.000 15.700 ;
        RECT 7.600 15.600 8.400 15.700 ;
        RECT 23.600 15.600 24.400 15.700 ;
    END
  END B[0]
  PIN B[1]
    PORT
      LAYER metal1 ;
        RECT 23.600 66.800 24.400 68.400 ;
        RECT 10.800 64.800 11.600 66.400 ;
        RECT 28.400 64.800 29.200 66.400 ;
        RECT 10.800 56.300 11.600 56.400 ;
        RECT 12.400 56.300 13.200 57.200 ;
        RECT 10.800 55.700 13.200 56.300 ;
        RECT 10.800 55.600 11.600 55.700 ;
        RECT 12.400 55.600 13.200 55.700 ;
        RECT 1.200 28.200 2.800 28.400 ;
        RECT 1.200 27.600 4.600 28.200 ;
        RECT 4.000 27.200 4.600 27.600 ;
        RECT 8.000 27.600 8.800 28.400 ;
        RECT 8.000 27.200 8.600 27.600 ;
        RECT 4.000 26.600 6.000 27.200 ;
        RECT 4.400 26.400 6.000 26.600 ;
        RECT 7.800 26.400 8.600 27.200 ;
        RECT 22.000 26.800 22.800 28.400 ;
      LAYER via1 ;
        RECT 23.600 67.600 24.400 68.400 ;
        RECT 10.800 65.600 11.600 66.400 ;
        RECT 28.400 65.600 29.200 66.400 ;
        RECT 22.000 27.600 22.800 28.400 ;
      LAYER metal2 ;
        RECT 23.600 67.600 24.400 68.400 ;
        RECT 23.700 66.400 24.300 67.600 ;
        RECT 10.800 65.600 11.600 66.400 ;
        RECT 23.600 65.600 24.400 66.400 ;
        RECT 28.400 65.600 29.200 66.400 ;
        RECT 10.900 56.400 11.500 65.600 ;
        RECT 10.800 55.600 11.600 56.400 ;
        RECT 10.900 32.400 11.500 55.600 ;
        RECT 1.200 31.600 2.000 32.400 ;
        RECT 10.800 31.600 11.600 32.400 ;
        RECT 1.300 28.400 1.900 31.600 ;
        RECT 1.200 27.600 2.000 28.400 ;
        RECT 22.000 27.600 22.800 28.400 ;
        RECT 4.400 27.000 5.200 27.200 ;
        RECT 7.800 27.000 8.600 27.200 ;
        RECT 4.400 26.400 8.600 27.000 ;
        RECT 22.100 26.400 22.700 27.600 ;
        RECT 7.600 25.600 8.400 26.400 ;
        RECT 22.000 25.600 22.800 26.400 ;
      LAYER metal3 ;
        RECT 10.800 66.300 11.600 66.400 ;
        RECT 23.600 66.300 24.400 66.400 ;
        RECT 28.400 66.300 29.200 66.400 ;
        RECT 10.800 65.700 29.200 66.300 ;
        RECT 10.800 65.600 11.600 65.700 ;
        RECT 23.600 65.600 24.400 65.700 ;
        RECT 28.400 65.600 29.200 65.700 ;
        RECT 1.200 32.300 2.000 32.400 ;
        RECT 10.800 32.300 11.600 32.400 ;
        RECT -1.900 31.700 11.600 32.300 ;
        RECT 1.200 31.600 2.000 31.700 ;
        RECT 10.800 31.600 11.600 31.700 ;
        RECT 7.600 26.300 8.400 26.400 ;
        RECT 22.000 26.300 22.800 26.400 ;
        RECT 7.600 25.700 22.800 26.300 ;
        RECT 7.600 25.600 8.400 25.700 ;
        RECT 22.000 25.600 22.800 25.700 ;
    END
  END B[1]
  PIN B[2]
    PORT
      LAYER metal1 ;
        RECT 107.600 94.400 108.400 94.800 ;
        RECT 107.600 93.800 109.200 94.400 ;
        RECT 108.400 93.600 109.200 93.800 ;
        RECT 102.000 55.600 102.800 57.200 ;
        RECT 100.400 54.300 101.200 55.200 ;
        RECT 102.100 54.300 102.700 55.600 ;
        RECT 100.400 53.700 102.700 54.300 ;
        RECT 100.400 53.600 101.200 53.700 ;
      LAYER metal2 ;
        RECT 105.300 96.400 105.900 104.300 ;
        RECT 105.200 95.600 106.000 96.400 ;
        RECT 108.400 95.600 109.200 96.400 ;
        RECT 105.300 62.400 105.900 95.600 ;
        RECT 108.500 94.400 109.100 95.600 ;
        RECT 108.400 93.600 109.200 94.400 ;
        RECT 102.000 61.600 102.800 62.400 ;
        RECT 105.200 61.600 106.000 62.400 ;
        RECT 102.100 56.400 102.700 61.600 ;
        RECT 102.000 55.600 102.800 56.400 ;
      LAYER metal3 ;
        RECT 105.200 96.300 106.000 96.400 ;
        RECT 108.400 96.300 109.200 96.400 ;
        RECT 105.200 95.700 109.200 96.300 ;
        RECT 105.200 95.600 106.000 95.700 ;
        RECT 108.400 95.600 109.200 95.700 ;
        RECT 102.000 62.300 102.800 62.400 ;
        RECT 105.200 62.300 106.000 62.400 ;
        RECT 102.000 61.700 106.000 62.300 ;
        RECT 102.000 61.600 102.800 61.700 ;
        RECT 105.200 61.600 106.000 61.700 ;
    END
  END B[2]
  PIN B[3]
    PORT
      LAYER metal1 ;
        RECT 158.000 55.600 158.800 57.200 ;
        RECT 161.200 55.600 162.000 57.200 ;
        RECT 152.400 54.400 153.200 54.800 ;
        RECT 152.400 53.800 154.000 54.400 ;
        RECT 153.200 53.600 154.000 53.800 ;
      LAYER metal2 ;
        RECT 158.000 55.600 158.800 56.400 ;
        RECT 161.200 55.600 162.000 56.400 ;
        RECT 153.200 53.600 154.000 54.400 ;
        RECT 153.300 50.400 153.900 53.600 ;
        RECT 158.100 50.400 158.700 55.600 ;
        RECT 161.300 50.400 161.900 55.600 ;
        RECT 153.200 49.600 154.000 50.400 ;
        RECT 158.000 49.600 158.800 50.400 ;
        RECT 161.200 49.600 162.000 50.400 ;
      LAYER metal3 ;
        RECT 153.200 50.300 154.000 50.400 ;
        RECT 158.000 50.300 158.800 50.400 ;
        RECT 161.200 50.300 162.000 50.400 ;
        RECT 153.200 49.700 165.100 50.300 ;
        RECT 153.200 49.600 154.000 49.700 ;
        RECT 158.000 49.600 158.800 49.700 ;
        RECT 161.200 49.600 162.000 49.700 ;
    END
  END B[3]
  PIN ALU_Sel[0]
    PORT
      LAYER metal1 ;
        RECT 1.200 95.600 2.000 97.200 ;
        RECT 4.400 93.600 5.200 95.200 ;
        RECT 16.400 91.600 18.000 92.400 ;
        RECT 38.800 91.600 40.400 92.400 ;
        RECT 54.000 90.800 54.800 92.400 ;
        RECT 60.400 87.600 61.200 89.200 ;
      LAYER via1 ;
        RECT 17.200 91.600 18.000 92.400 ;
        RECT 39.600 91.600 40.400 92.400 ;
        RECT 54.000 91.600 54.800 92.400 ;
      LAYER metal2 ;
        RECT 1.200 95.600 2.000 96.400 ;
        RECT 1.300 90.400 1.900 95.600 ;
        RECT 4.400 93.600 5.200 94.400 ;
        RECT 4.500 92.400 5.100 93.600 ;
        RECT 4.400 91.600 5.200 92.400 ;
        RECT 17.200 91.600 18.000 92.400 ;
        RECT 39.600 91.600 40.400 92.400 ;
        RECT 54.000 91.600 54.800 92.400 ;
        RECT 60.400 91.600 61.200 92.400 ;
        RECT 4.500 90.400 5.100 91.600 ;
        RECT 1.200 89.600 2.000 90.400 ;
        RECT 4.400 89.600 5.200 90.400 ;
        RECT 60.500 88.400 61.100 91.600 ;
        RECT 60.400 87.600 61.200 88.400 ;
      LAYER metal3 ;
        RECT 4.400 92.300 5.200 92.400 ;
        RECT 17.200 92.300 18.000 92.400 ;
        RECT 39.600 92.300 40.400 92.400 ;
        RECT 54.000 92.300 54.800 92.400 ;
        RECT 60.400 92.300 61.200 92.400 ;
        RECT 4.400 91.700 61.200 92.300 ;
        RECT 4.400 91.600 5.200 91.700 ;
        RECT 17.200 91.600 18.000 91.700 ;
        RECT 39.600 91.600 40.400 91.700 ;
        RECT 54.000 91.600 54.800 91.700 ;
        RECT 60.400 91.600 61.200 91.700 ;
        RECT 1.200 90.300 2.000 90.400 ;
        RECT 4.400 90.300 5.200 90.400 ;
        RECT -1.900 89.700 5.200 90.300 ;
        RECT 1.200 89.600 2.000 89.700 ;
        RECT 4.400 89.600 5.200 89.700 ;
    END
  END ALU_Sel[0]
  PIN ALU_Sel[1]
    PORT
      LAYER metal1 ;
        RECT 26.800 96.300 27.600 97.200 ;
        RECT 28.400 96.300 29.200 96.400 ;
        RECT 26.800 95.700 29.200 96.300 ;
        RECT 26.800 95.600 27.600 95.700 ;
        RECT 28.400 95.600 29.200 95.700 ;
        RECT 57.200 95.600 58.000 97.200 ;
        RECT 61.200 91.600 62.800 92.400 ;
        RECT 67.600 91.600 69.200 92.400 ;
        RECT 41.200 90.300 42.000 91.200 ;
        RECT 47.600 90.300 48.400 91.200 ;
        RECT 41.200 89.700 48.400 90.300 ;
        RECT 41.200 89.600 42.000 89.700 ;
        RECT 47.600 89.600 48.400 89.700 ;
      LAYER via1 ;
        RECT 62.000 91.600 62.800 92.400 ;
        RECT 68.400 91.600 69.200 92.400 ;
      LAYER metal2 ;
        RECT 28.400 95.600 29.200 96.400 ;
        RECT 28.500 94.400 29.100 95.600 ;
        RECT 52.500 94.400 53.100 104.300 ;
        RECT 57.200 95.600 58.000 96.400 ;
        RECT 57.300 94.400 57.900 95.600 ;
        RECT 28.400 93.600 29.200 94.400 ;
        RECT 41.200 93.600 42.000 94.400 ;
        RECT 52.400 93.600 53.200 94.400 ;
        RECT 57.200 93.600 58.000 94.400 ;
        RECT 62.000 93.600 62.800 94.400 ;
        RECT 68.400 93.600 69.200 94.400 ;
        RECT 41.300 90.400 41.900 93.600 ;
        RECT 62.100 92.400 62.700 93.600 ;
        RECT 68.500 92.400 69.100 93.600 ;
        RECT 62.000 91.600 62.800 92.400 ;
        RECT 68.400 91.600 69.200 92.400 ;
        RECT 41.200 89.600 42.000 90.400 ;
      LAYER metal3 ;
        RECT 28.400 94.300 29.200 94.400 ;
        RECT 41.200 94.300 42.000 94.400 ;
        RECT 52.400 94.300 53.200 94.400 ;
        RECT 57.200 94.300 58.000 94.400 ;
        RECT 62.000 94.300 62.800 94.400 ;
        RECT 68.400 94.300 69.200 94.400 ;
        RECT 28.400 93.700 69.200 94.300 ;
        RECT 28.400 93.600 29.200 93.700 ;
        RECT 41.200 93.600 42.000 93.700 ;
        RECT 52.400 93.600 53.200 93.700 ;
        RECT 57.200 93.600 58.000 93.700 ;
        RECT 62.000 93.600 62.800 93.700 ;
        RECT 68.400 93.600 69.200 93.700 ;
    END
  END ALU_Sel[1]
  PIN ALU_Sel[2]
    PORT
      LAYER metal1 ;
        RECT 12.400 95.600 13.200 97.200 ;
        RECT 31.600 96.300 32.400 97.200 ;
        RECT 33.200 96.300 34.000 97.200 ;
        RECT 31.600 95.700 34.000 96.300 ;
        RECT 31.600 95.600 32.400 95.700 ;
        RECT 33.200 95.600 34.000 95.700 ;
        RECT 18.800 89.600 19.600 91.200 ;
        RECT 63.600 89.600 64.400 91.200 ;
        RECT 70.000 89.600 70.800 91.200 ;
        RECT 33.200 66.800 34.000 68.400 ;
        RECT 70.000 66.800 70.800 68.400 ;
      LAYER via1 ;
        RECT 33.200 67.600 34.000 68.400 ;
        RECT 70.000 67.600 70.800 68.400 ;
      LAYER metal2 ;
        RECT 33.300 96.400 33.900 104.300 ;
        RECT 12.400 95.600 13.200 96.400 ;
        RECT 33.200 95.600 34.000 96.400 ;
        RECT 12.500 90.400 13.100 95.600 ;
        RECT 33.300 90.400 33.900 95.600 ;
        RECT 12.400 89.600 13.200 90.400 ;
        RECT 18.800 89.600 19.600 90.400 ;
        RECT 33.200 89.600 34.000 90.400 ;
        RECT 63.600 89.600 64.400 90.400 ;
        RECT 70.000 89.600 70.800 90.400 ;
        RECT 33.300 68.400 33.900 89.600 ;
        RECT 70.100 68.400 70.700 89.600 ;
        RECT 33.200 67.600 34.000 68.400 ;
        RECT 70.000 67.600 70.800 68.400 ;
      LAYER metal3 ;
        RECT 12.400 90.300 13.200 90.400 ;
        RECT 18.800 90.300 19.600 90.400 ;
        RECT 33.200 90.300 34.000 90.400 ;
        RECT 63.600 90.300 64.400 90.400 ;
        RECT 70.000 90.300 70.800 90.400 ;
        RECT 12.400 89.700 70.800 90.300 ;
        RECT 12.400 89.600 13.200 89.700 ;
        RECT 18.800 89.600 19.600 89.700 ;
        RECT 33.200 89.600 34.000 89.700 ;
        RECT 63.600 89.600 64.400 89.700 ;
        RECT 70.000 89.600 70.800 89.700 ;
    END
  END ALU_Sel[2]
  PIN Cin
    PORT
      LAYER metal1 ;
        RECT 26.800 15.600 27.600 17.200 ;
        RECT 17.200 12.800 18.000 14.400 ;
        RECT 25.200 9.600 26.000 11.200 ;
      LAYER via1 ;
        RECT 17.200 13.600 18.000 14.400 ;
      LAYER metal2 ;
        RECT 26.800 15.600 27.600 16.400 ;
        RECT 26.900 14.400 27.500 15.600 ;
        RECT 17.200 13.600 18.000 14.400 ;
        RECT 26.800 13.600 27.600 14.400 ;
        RECT 25.200 10.300 26.000 10.400 ;
        RECT 26.900 10.300 27.500 13.600 ;
        RECT 25.200 9.700 27.500 10.300 ;
        RECT 25.200 9.600 26.000 9.700 ;
        RECT 25.300 -2.300 25.900 9.600 ;
      LAYER metal3 ;
        RECT 17.200 14.300 18.000 14.400 ;
        RECT 26.800 14.300 27.600 14.400 ;
        RECT 17.200 13.700 27.600 14.300 ;
        RECT 17.200 13.600 18.000 13.700 ;
        RECT 26.800 13.600 27.600 13.700 ;
    END
  END Cin
  PIN Y[0]
    PORT
      LAYER metal1 ;
        RECT 57.200 12.400 58.000 19.800 ;
        RECT 57.400 10.200 58.000 12.400 ;
        RECT 57.200 2.200 58.000 10.200 ;
      LAYER via1 ;
        RECT 57.200 3.600 58.000 4.400 ;
      LAYER metal2 ;
        RECT 57.200 3.600 58.000 4.400 ;
        RECT 57.300 2.400 57.900 3.600 ;
        RECT 54.000 1.600 54.800 2.400 ;
        RECT 57.200 1.600 58.000 2.400 ;
        RECT 54.100 -2.300 54.700 1.600 ;
      LAYER metal3 ;
        RECT 54.000 2.300 54.800 2.400 ;
        RECT 57.200 2.300 58.000 2.400 ;
        RECT 54.000 1.700 58.000 2.300 ;
        RECT 54.000 1.600 54.800 1.700 ;
        RECT 57.200 1.600 58.000 1.700 ;
    END
  END Y[0]
  PIN Y[1]
    PORT
      LAYER metal1 ;
        RECT 58.800 12.400 59.600 19.800 ;
        RECT 58.800 10.200 59.400 12.400 ;
        RECT 58.800 2.200 59.600 10.200 ;
      LAYER via1 ;
        RECT 58.800 3.600 59.600 4.400 ;
      LAYER metal2 ;
        RECT 58.800 3.600 59.600 4.400 ;
        RECT 58.900 -1.700 59.500 3.600 ;
        RECT 58.900 -2.300 61.100 -1.700 ;
    END
  END Y[1]
  PIN Y[2]
    PORT
      LAYER metal1 ;
        RECT 105.200 12.400 106.000 19.800 ;
        RECT 105.200 10.200 105.800 12.400 ;
        RECT 105.200 2.200 106.000 10.200 ;
      LAYER via1 ;
        RECT 105.200 3.600 106.000 4.400 ;
      LAYER metal2 ;
        RECT 105.200 3.600 106.000 4.400 ;
        RECT 105.300 -1.700 105.900 3.600 ;
        RECT 105.300 -2.300 107.500 -1.700 ;
    END
  END Y[2]
  PIN Y[3]
    PORT
      LAYER metal1 ;
        RECT 159.600 14.300 160.400 19.800 ;
        RECT 161.200 14.300 162.000 14.400 ;
        RECT 159.600 13.700 162.000 14.300 ;
        RECT 159.600 12.400 160.400 13.700 ;
        RECT 161.200 13.600 162.000 13.700 ;
        RECT 159.800 10.200 160.400 12.400 ;
        RECT 159.600 2.200 160.400 10.200 ;
      LAYER metal2 ;
        RECT 161.200 13.600 162.000 14.400 ;
      LAYER metal3 ;
        RECT 161.200 14.300 162.000 14.400 ;
        RECT 161.200 13.700 165.100 14.300 ;
        RECT 161.200 13.600 162.000 13.700 ;
    END
  END Y[3]
  PIN Cout
    PORT
      LAYER metal1 ;
        RECT 159.600 31.800 160.400 39.800 ;
        RECT 159.800 29.600 160.400 31.800 ;
        RECT 159.600 28.300 160.400 29.600 ;
        RECT 161.200 28.300 162.000 28.400 ;
        RECT 159.600 27.700 162.000 28.300 ;
        RECT 159.600 22.200 160.400 27.700 ;
        RECT 161.200 27.600 162.000 27.700 ;
      LAYER metal2 ;
        RECT 161.200 29.600 162.000 30.400 ;
        RECT 161.300 28.400 161.900 29.600 ;
        RECT 161.200 27.600 162.000 28.400 ;
      LAYER metal3 ;
        RECT 161.200 30.300 162.000 30.400 ;
        RECT 161.200 29.700 165.100 30.300 ;
        RECT 161.200 29.600 162.000 29.700 ;
    END
  END Cout
  PIN Zero
    PORT
      LAYER metal1 ;
        RECT 154.800 12.400 155.600 19.800 ;
        RECT 155.000 10.200 155.600 12.400 ;
        RECT 154.800 2.200 155.600 10.200 ;
      LAYER via1 ;
        RECT 154.800 7.600 155.600 8.400 ;
      LAYER metal2 ;
        RECT 154.800 9.600 155.600 10.400 ;
        RECT 154.900 8.400 155.500 9.600 ;
        RECT 154.800 7.600 155.600 8.400 ;
      LAYER metal3 ;
        RECT 154.800 10.300 155.600 10.400 ;
        RECT 154.800 9.700 165.100 10.300 ;
        RECT 154.800 9.600 155.600 9.700 ;
    END
  END Zero
  OBS
      LAYER metal1 ;
        RECT 2.800 88.300 3.600 99.800 ;
        RECT 7.000 96.400 7.800 99.800 ;
        RECT 6.000 95.800 7.800 96.400 ;
        RECT 10.800 97.800 11.600 99.800 ;
        RECT 6.000 92.300 6.800 95.800 ;
        RECT 10.800 94.400 11.400 97.800 ;
        RECT 10.800 93.600 11.600 94.400 ;
        RECT 15.200 94.200 16.000 99.800 ;
        RECT 23.000 96.400 23.800 99.800 ;
        RECT 22.000 95.800 23.800 96.400 ;
        RECT 14.200 93.800 16.000 94.200 ;
        RECT 14.200 93.600 15.800 93.800 ;
        RECT 20.400 93.600 21.200 95.200 ;
        RECT 9.200 92.300 10.000 92.400 ;
        RECT 6.000 91.700 10.000 92.300 ;
        RECT 4.400 88.300 5.200 88.400 ;
        RECT 2.800 87.700 5.200 88.300 ;
        RECT 2.800 82.200 3.600 87.700 ;
        RECT 4.400 87.600 5.200 87.700 ;
        RECT 6.000 82.200 6.800 91.700 ;
        RECT 9.200 90.800 10.000 91.700 ;
        RECT 7.600 88.800 8.400 90.400 ;
        RECT 10.800 90.200 11.400 93.600 ;
        RECT 14.200 90.400 14.800 93.600 ;
        RECT 9.800 89.400 11.600 90.200 ;
        RECT 14.000 89.600 14.800 90.400 ;
        RECT 9.800 84.400 10.600 89.400 ;
        RECT 14.200 87.000 14.800 89.600 ;
        RECT 22.000 92.300 22.800 95.800 ;
        RECT 23.600 94.300 24.400 94.400 ;
        RECT 25.200 94.300 26.000 99.800 ;
        RECT 23.600 93.700 26.000 94.300 ;
        RECT 23.600 93.600 24.400 93.700 ;
        RECT 23.600 92.300 24.400 92.400 ;
        RECT 22.000 91.700 24.400 92.300 ;
        RECT 15.600 88.300 16.400 89.200 ;
        RECT 20.400 88.300 21.200 88.400 ;
        RECT 15.600 87.700 21.200 88.300 ;
        RECT 15.600 87.600 16.400 87.700 ;
        RECT 20.400 87.600 21.200 87.700 ;
        RECT 14.200 86.400 17.800 87.000 ;
        RECT 14.200 86.200 14.800 86.400 ;
        RECT 9.800 83.600 11.600 84.400 ;
        RECT 9.800 82.200 10.600 83.600 ;
        RECT 14.000 82.200 14.800 86.200 ;
        RECT 17.200 86.200 17.800 86.400 ;
        RECT 17.200 82.200 18.000 86.200 ;
        RECT 22.000 82.200 22.800 91.700 ;
        RECT 23.600 91.600 24.400 91.700 ;
        RECT 23.600 88.800 24.400 90.400 ;
        RECT 25.200 82.200 26.000 93.700 ;
        RECT 30.000 97.800 30.800 99.800 ;
        RECT 30.000 94.400 30.600 97.800 ;
        RECT 30.000 93.600 30.800 94.400 ;
        RECT 26.800 92.300 27.600 92.400 ;
        RECT 28.400 92.300 29.200 92.400 ;
        RECT 26.800 91.700 29.200 92.300 ;
        RECT 26.800 91.600 27.600 91.700 ;
        RECT 28.400 90.800 29.200 91.700 ;
        RECT 30.000 90.200 30.600 93.600 ;
        RECT 29.000 89.400 30.800 90.200 ;
        RECT 29.000 84.400 29.800 89.400 ;
        RECT 29.000 83.600 30.800 84.400 ;
        RECT 29.000 82.200 29.800 83.600 ;
        RECT 34.800 82.200 35.600 99.800 ;
        RECT 37.600 94.200 38.400 99.800 ;
        RECT 36.600 93.800 38.400 94.200 ;
        RECT 51.200 94.200 52.000 99.800 ;
        RECT 55.600 97.800 56.400 99.800 ;
        RECT 55.600 94.400 56.200 97.800 ;
        RECT 51.200 93.800 53.000 94.200 ;
        RECT 36.600 93.600 38.200 93.800 ;
        RECT 51.400 93.600 53.000 93.800 ;
        RECT 36.600 90.400 37.200 93.600 ;
        RECT 49.200 91.600 50.800 92.400 ;
        RECT 36.400 89.600 37.200 90.400 ;
        RECT 36.600 87.000 37.200 89.600 ;
        RECT 52.400 90.400 53.000 93.600 ;
        RECT 55.600 93.600 56.400 94.400 ;
        RECT 60.000 94.200 60.800 99.800 ;
        RECT 66.400 94.200 67.200 99.800 ;
        RECT 71.600 95.600 72.400 97.200 ;
        RECT 59.000 93.800 60.800 94.200 ;
        RECT 65.400 93.800 67.200 94.200 ;
        RECT 59.000 93.600 60.600 93.800 ;
        RECT 65.400 93.600 67.000 93.800 ;
        RECT 52.400 89.600 53.200 90.400 ;
        RECT 55.600 90.200 56.200 93.600 ;
        RECT 59.000 90.400 59.600 93.600 ;
        RECT 65.400 90.400 66.000 93.600 ;
        RECT 38.000 87.600 38.800 89.200 ;
        RECT 41.200 88.300 42.000 88.400 ;
        RECT 50.800 88.300 51.600 89.200 ;
        RECT 41.200 87.700 51.600 88.300 ;
        RECT 41.200 87.600 42.000 87.700 ;
        RECT 50.800 87.600 51.600 87.700 ;
        RECT 52.400 87.000 53.000 89.600 ;
        RECT 36.600 86.400 40.200 87.000 ;
        RECT 36.600 86.200 37.200 86.400 ;
        RECT 36.400 82.200 37.200 86.200 ;
        RECT 39.600 86.200 40.200 86.400 ;
        RECT 49.400 86.400 53.000 87.000 ;
        RECT 49.400 86.200 50.000 86.400 ;
        RECT 39.600 82.200 40.400 86.200 ;
        RECT 49.200 82.200 50.000 86.200 ;
        RECT 52.400 86.200 53.000 86.400 ;
        RECT 54.600 89.400 56.400 90.200 ;
        RECT 58.800 89.600 59.600 90.400 ;
        RECT 65.200 89.600 66.000 90.400 ;
        RECT 52.400 82.200 53.200 86.200 ;
        RECT 54.600 84.400 55.400 89.400 ;
        RECT 59.000 87.000 59.600 89.600 ;
        RECT 65.400 87.000 66.000 89.600 ;
        RECT 66.800 87.600 67.600 89.200 ;
        RECT 59.000 86.400 62.600 87.000 ;
        RECT 65.400 86.400 69.000 87.000 ;
        RECT 59.000 86.200 59.600 86.400 ;
        RECT 54.600 83.600 56.400 84.400 ;
        RECT 54.600 82.200 55.400 83.600 ;
        RECT 58.800 82.200 59.600 86.200 ;
        RECT 62.000 82.200 62.800 86.400 ;
        RECT 65.400 86.200 66.000 86.400 ;
        RECT 65.200 82.200 66.000 86.200 ;
        RECT 68.400 86.200 69.000 86.400 ;
        RECT 68.400 82.200 69.200 86.200 ;
        RECT 73.200 82.200 74.000 99.800 ;
        RECT 74.800 95.800 75.600 99.800 ;
        RECT 76.400 96.000 77.200 99.800 ;
        RECT 79.600 96.000 80.400 99.800 ;
        RECT 76.400 95.800 80.400 96.000 ;
        RECT 82.800 97.800 83.600 99.800 ;
        RECT 75.000 94.400 75.600 95.800 ;
        RECT 76.600 95.400 80.200 95.800 ;
        RECT 78.800 94.400 79.600 94.800 ;
        RECT 82.800 94.400 83.400 97.800 ;
        RECT 86.000 96.000 86.800 99.800 ;
        RECT 89.200 96.000 90.000 99.800 ;
        RECT 86.000 95.800 90.000 96.000 ;
        RECT 90.800 95.800 91.600 99.800 ;
        RECT 95.000 96.400 95.800 99.800 ;
        RECT 97.400 96.400 98.200 97.200 ;
        RECT 86.200 95.400 89.800 95.800 ;
        RECT 90.800 94.400 91.400 95.800 ;
        RECT 94.000 95.600 96.400 96.400 ;
        RECT 97.200 95.600 98.000 96.400 ;
        RECT 98.800 95.800 99.600 99.800 ;
        RECT 103.600 95.800 104.400 99.800 ;
        RECT 105.200 96.000 106.000 99.800 ;
        RECT 108.400 96.000 109.200 99.800 ;
        RECT 105.200 95.800 109.200 96.000 ;
        RECT 74.800 93.600 77.400 94.400 ;
        RECT 78.800 94.300 80.400 94.400 ;
        RECT 82.800 94.300 83.600 94.400 ;
        RECT 78.800 93.800 83.600 94.300 ;
        RECT 79.600 93.700 83.600 93.800 ;
        RECT 79.600 93.600 80.400 93.700 ;
        RECT 82.800 93.600 83.600 93.700 ;
        RECT 89.000 94.300 91.600 94.400 ;
        RECT 92.400 94.300 93.200 95.200 ;
        RECT 89.000 93.700 93.200 94.300 ;
        RECT 89.000 93.600 91.600 93.700 ;
        RECT 92.400 93.600 93.200 93.700 ;
        RECT 74.800 90.200 75.600 90.400 ;
        RECT 76.800 90.200 77.400 93.600 ;
        RECT 78.000 91.600 78.800 93.200 ;
        RECT 82.800 90.200 83.400 93.600 ;
        RECT 89.000 90.200 89.600 93.600 ;
        RECT 74.800 89.600 76.200 90.200 ;
        RECT 76.800 89.600 77.800 90.200 ;
        RECT 75.600 88.400 76.200 89.600 ;
        RECT 75.600 87.600 76.400 88.400 ;
        RECT 77.000 84.400 77.800 89.600 ;
        RECT 81.800 89.400 83.600 90.200 ;
        RECT 88.600 89.600 89.600 90.200 ;
        RECT 77.000 83.600 78.800 84.400 ;
        RECT 77.000 82.200 77.800 83.600 ;
        RECT 81.800 82.200 82.600 89.400 ;
        RECT 88.600 82.200 89.400 89.600 ;
        RECT 94.000 82.200 94.800 95.600 ;
        RECT 97.200 92.200 98.000 92.400 ;
        RECT 99.000 92.200 99.600 95.800 ;
        RECT 103.800 94.400 104.400 95.800 ;
        RECT 105.400 95.400 109.000 95.800 ;
        RECT 100.400 92.800 101.200 94.400 ;
        RECT 103.600 93.600 106.200 94.400 ;
        RECT 111.200 94.200 112.000 99.800 ;
        RECT 121.200 95.800 122.000 99.800 ;
        RECT 122.800 96.000 123.600 99.800 ;
        RECT 126.000 96.000 126.800 99.800 ;
        RECT 122.800 95.800 126.800 96.000 ;
        RECT 121.400 94.400 122.000 95.800 ;
        RECT 123.000 95.400 126.600 95.800 ;
        RECT 102.000 92.200 102.800 92.400 ;
        RECT 97.200 91.600 99.600 92.200 ;
        RECT 101.200 91.600 102.800 92.200 ;
        RECT 95.600 88.800 96.400 90.400 ;
        RECT 97.400 90.200 98.000 91.600 ;
        RECT 101.200 91.200 102.000 91.600 ;
        RECT 103.600 90.200 104.400 90.400 ;
        RECT 105.600 90.200 106.200 93.600 ;
        RECT 110.200 93.800 112.000 94.200 ;
        RECT 110.200 93.600 111.800 93.800 ;
        RECT 121.200 93.600 123.800 94.400 ;
        RECT 110.200 90.400 110.800 93.600 ;
        RECT 112.400 91.600 114.000 92.400 ;
        RECT 123.200 92.300 123.800 93.600 ;
        RECT 129.200 94.300 130.000 99.800 ;
        RECT 133.400 96.400 134.200 99.800 ;
        RECT 132.400 95.800 134.200 96.400 ;
        RECT 138.800 95.800 139.600 99.800 ;
        RECT 140.200 96.400 141.000 97.200 ;
        RECT 130.800 94.300 131.600 95.200 ;
        RECT 129.200 93.700 131.600 94.300 ;
        RECT 116.500 91.700 123.800 92.300 ;
        RECT 97.200 82.200 98.000 90.200 ;
        RECT 98.800 89.600 102.800 90.200 ;
        RECT 103.600 89.600 105.000 90.200 ;
        RECT 105.600 89.600 106.600 90.200 ;
        RECT 110.000 89.600 110.800 90.400 ;
        RECT 114.800 90.300 115.600 91.200 ;
        RECT 116.500 90.300 117.100 91.700 ;
        RECT 114.800 89.700 117.100 90.300 ;
        RECT 121.200 90.200 122.000 90.400 ;
        RECT 123.200 90.200 123.800 91.700 ;
        RECT 124.400 91.600 125.200 93.200 ;
        RECT 114.800 89.600 115.600 89.700 ;
        RECT 121.200 89.600 122.600 90.200 ;
        RECT 123.200 89.600 124.200 90.200 ;
        RECT 98.800 82.200 99.600 89.600 ;
        RECT 102.000 82.200 102.800 89.600 ;
        RECT 104.400 88.400 105.000 89.600 ;
        RECT 105.800 88.400 106.600 89.600 ;
        RECT 104.400 87.600 105.200 88.400 ;
        RECT 105.800 87.600 107.600 88.400 ;
        RECT 105.800 82.200 106.600 87.600 ;
        RECT 110.200 87.000 110.800 89.600 ;
        RECT 111.600 87.600 112.400 89.200 ;
        RECT 122.000 88.400 122.600 89.600 ;
        RECT 122.000 87.600 122.800 88.400 ;
        RECT 110.200 86.400 113.800 87.000 ;
        RECT 110.200 86.200 110.800 86.400 ;
        RECT 110.000 82.200 110.800 86.200 ;
        RECT 113.200 86.200 113.800 86.400 ;
        RECT 113.200 82.200 114.000 86.200 ;
        RECT 123.400 82.200 124.200 89.600 ;
        RECT 129.200 82.200 130.000 93.700 ;
        RECT 130.800 93.600 131.600 93.700 ;
        RECT 132.400 82.200 133.200 95.800 ;
        RECT 137.200 92.800 138.000 94.400 ;
        RECT 138.800 94.300 139.400 95.800 ;
        RECT 140.400 95.600 141.200 96.400 ;
        RECT 142.000 96.000 142.800 99.800 ;
        RECT 145.200 96.000 146.000 99.800 ;
        RECT 142.000 95.800 146.000 96.000 ;
        RECT 146.800 95.800 147.600 99.800 ;
        RECT 151.000 96.400 151.800 99.800 ;
        RECT 150.000 95.800 151.800 96.400 ;
        RECT 154.800 97.800 155.600 99.800 ;
        RECT 142.200 95.400 145.800 95.800 ;
        RECT 142.800 94.400 143.600 94.800 ;
        RECT 146.800 94.400 147.400 95.800 ;
        RECT 142.000 94.300 143.600 94.400 ;
        RECT 138.800 93.800 143.600 94.300 ;
        RECT 138.800 93.700 142.800 93.800 ;
        RECT 135.600 92.300 136.400 92.400 ;
        RECT 134.100 92.200 136.400 92.300 ;
        RECT 138.800 92.200 139.400 93.700 ;
        RECT 142.000 93.600 142.800 93.700 ;
        RECT 145.000 93.600 147.600 94.400 ;
        RECT 148.400 93.600 149.200 95.200 ;
        RECT 140.400 92.200 141.200 92.400 ;
        RECT 134.100 91.700 137.200 92.200 ;
        RECT 134.100 90.400 134.700 91.700 ;
        RECT 135.600 91.600 137.200 91.700 ;
        RECT 138.800 91.600 141.200 92.200 ;
        RECT 143.600 91.600 144.400 93.200 ;
        RECT 136.400 91.200 137.200 91.600 ;
        RECT 134.000 88.800 134.800 90.400 ;
        RECT 140.400 90.200 141.000 91.600 ;
        RECT 145.000 90.200 145.600 93.600 ;
        RECT 146.800 90.200 147.600 90.400 ;
        RECT 135.600 89.600 139.600 90.200 ;
        RECT 135.600 82.200 136.400 89.600 ;
        RECT 138.800 82.200 139.600 89.600 ;
        RECT 140.400 82.200 141.200 90.200 ;
        RECT 144.600 89.600 145.600 90.200 ;
        RECT 146.200 89.600 147.600 90.200 ;
        RECT 144.600 84.400 145.400 89.600 ;
        RECT 146.200 88.400 146.800 89.600 ;
        RECT 146.000 87.600 146.800 88.400 ;
        RECT 143.600 83.600 145.400 84.400 ;
        RECT 144.600 82.200 145.400 83.600 ;
        RECT 150.000 82.200 150.800 95.800 ;
        RECT 154.800 94.400 155.400 97.800 ;
        RECT 151.600 94.300 152.400 94.400 ;
        RECT 154.800 94.300 155.600 94.400 ;
        RECT 151.600 93.700 155.600 94.300 ;
        RECT 151.600 93.600 152.400 93.700 ;
        RECT 154.800 93.600 155.600 93.700 ;
        RECT 153.200 90.800 154.000 92.400 ;
        RECT 151.600 88.800 152.400 90.400 ;
        RECT 154.800 90.200 155.400 93.600 ;
        RECT 153.800 89.400 155.600 90.200 ;
        RECT 153.800 82.200 154.600 89.400 ;
        RECT 158.000 82.200 158.800 99.800 ;
        RECT 1.200 71.800 2.000 79.800 ;
        RECT 4.400 75.800 5.200 79.800 ;
        RECT 1.200 70.400 1.800 71.800 ;
        RECT 4.400 71.600 5.000 75.800 ;
        RECT 2.600 71.000 5.000 71.600 ;
        RECT 1.200 69.600 2.000 70.400 ;
        RECT 1.200 66.200 1.800 69.600 ;
        RECT 2.600 67.600 3.200 71.000 ;
        RECT 6.000 68.300 6.800 69.200 ;
        RECT 9.200 68.300 10.000 79.800 ;
        RECT 13.400 72.600 14.200 79.800 ;
        RECT 12.400 71.800 14.200 72.600 ;
        RECT 15.600 74.300 16.400 79.800 ;
        RECT 17.200 74.300 18.000 74.400 ;
        RECT 15.600 73.700 18.000 74.300 ;
        RECT 12.600 68.400 13.200 71.800 ;
        RECT 14.000 70.300 14.800 71.200 ;
        RECT 15.600 70.300 16.400 73.700 ;
        RECT 17.200 73.600 18.000 73.700 ;
        RECT 18.800 71.600 19.600 73.200 ;
        RECT 14.000 69.700 16.400 70.300 ;
        RECT 14.000 69.600 14.800 69.700 ;
        RECT 6.000 67.700 10.000 68.300 ;
        RECT 6.000 67.600 6.800 67.700 ;
        RECT 2.400 67.400 3.200 67.600 ;
        RECT 2.400 67.000 5.400 67.400 ;
        RECT 2.400 66.800 6.600 67.000 ;
        RECT 4.800 66.400 6.600 66.800 ;
        RECT 6.000 66.200 6.600 66.400 ;
        RECT 1.200 65.200 2.600 66.200 ;
        RECT 1.800 64.400 2.600 65.200 ;
        RECT 1.200 63.600 2.600 64.400 ;
        RECT 1.800 62.200 2.600 63.600 ;
        RECT 6.000 62.200 6.800 66.200 ;
        RECT 9.200 62.200 10.000 67.700 ;
        RECT 12.400 67.600 13.200 68.400 ;
        RECT 12.600 64.400 13.200 67.600 ;
        RECT 12.400 62.200 13.200 64.400 ;
        RECT 15.600 62.200 16.400 69.700 ;
        RECT 20.400 66.200 21.200 79.800 ;
        RECT 19.400 65.600 21.200 66.200 ;
        RECT 25.200 66.200 26.000 79.800 ;
        RECT 26.800 71.600 27.600 73.200 ;
        RECT 31.000 72.600 31.800 79.800 ;
        RECT 30.000 71.800 31.800 72.600 ;
        RECT 30.200 68.400 30.800 71.800 ;
        RECT 30.000 67.600 30.800 68.400 ;
        RECT 25.200 65.600 27.000 66.200 ;
        RECT 19.400 64.400 20.200 65.600 ;
        RECT 26.200 64.400 27.000 65.600 ;
        RECT 30.200 64.400 30.800 67.600 ;
        RECT 34.800 68.300 35.600 79.800 ;
        RECT 36.400 71.600 37.200 73.200 ;
        RECT 40.600 71.800 42.600 79.800 ;
        RECT 36.400 68.300 37.200 68.400 ;
        RECT 34.800 67.700 37.200 68.300 ;
        RECT 34.800 66.200 35.600 67.700 ;
        RECT 36.400 67.600 37.200 67.700 ;
        RECT 38.000 67.600 38.800 69.200 ;
        RECT 39.600 68.800 40.400 70.400 ;
        RECT 41.400 68.400 42.000 71.800 ;
        RECT 42.800 68.800 43.600 70.400 ;
        RECT 41.200 68.200 42.000 68.400 ;
        RECT 44.400 68.300 45.200 68.400 ;
        RECT 49.200 68.300 50.000 68.400 ;
        RECT 44.400 68.200 50.000 68.300 ;
        RECT 39.600 67.600 42.000 68.200 ;
        RECT 43.600 67.700 50.000 68.200 ;
        RECT 43.600 67.600 45.200 67.700 ;
        RECT 49.200 67.600 50.000 67.700 ;
        RECT 39.600 66.200 40.200 67.600 ;
        RECT 43.600 67.200 44.400 67.600 ;
        RECT 50.800 66.800 51.600 68.400 ;
        RECT 41.400 66.200 45.000 66.600 ;
        RECT 52.400 66.200 53.200 79.800 ;
        RECT 54.000 71.600 54.800 73.200 ;
        RECT 58.200 71.800 60.200 79.800 ;
        RECT 63.600 71.800 64.400 79.800 ;
        RECT 65.200 72.400 66.000 79.800 ;
        RECT 68.400 72.400 69.200 79.800 ;
        RECT 65.200 71.800 69.200 72.400 ;
        RECT 57.200 68.800 58.000 70.400 ;
        RECT 58.800 68.400 59.400 71.800 ;
        RECT 63.800 70.400 64.400 71.800 ;
        RECT 67.600 70.400 68.400 70.800 ;
        RECT 60.400 68.800 61.200 70.400 ;
        RECT 63.600 69.800 66.000 70.400 ;
        RECT 67.600 69.800 69.200 70.400 ;
        RECT 63.600 69.600 64.400 69.800 ;
        RECT 55.600 68.200 56.400 68.400 ;
        RECT 58.800 68.200 59.600 68.400 ;
        RECT 55.600 67.600 57.200 68.200 ;
        RECT 58.800 67.600 61.200 68.200 ;
        RECT 62.000 67.600 62.800 69.200 ;
        RECT 56.400 67.200 57.200 67.600 ;
        RECT 55.800 66.200 59.400 66.600 ;
        RECT 60.600 66.400 61.200 67.600 ;
        RECT 34.800 65.600 36.600 66.200 ;
        RECT 19.400 63.600 21.200 64.400 ;
        RECT 25.200 63.600 27.000 64.400 ;
        RECT 19.400 62.200 20.200 63.600 ;
        RECT 26.200 62.200 27.000 63.600 ;
        RECT 30.000 62.200 30.800 64.400 ;
        RECT 35.800 62.200 36.600 65.600 ;
        RECT 38.000 62.800 38.800 66.200 ;
        RECT 39.600 63.400 40.400 66.200 ;
        RECT 41.200 66.000 45.200 66.200 ;
        RECT 41.200 62.800 42.000 66.000 ;
        RECT 38.000 62.200 42.000 62.800 ;
        RECT 44.400 62.200 45.200 66.000 ;
        RECT 52.400 65.600 54.200 66.200 ;
        RECT 53.400 62.200 54.200 65.600 ;
        RECT 55.600 66.000 59.600 66.200 ;
        RECT 55.600 62.200 56.400 66.000 ;
        RECT 58.800 62.800 59.600 66.000 ;
        RECT 60.400 63.400 61.200 66.400 ;
        RECT 62.000 62.800 62.800 66.200 ;
        RECT 63.600 65.600 64.400 66.400 ;
        RECT 65.400 66.200 66.000 69.800 ;
        RECT 68.400 69.600 69.200 69.800 ;
        RECT 66.800 67.600 67.600 69.200 ;
        RECT 63.800 64.800 64.600 65.600 ;
        RECT 58.800 62.200 62.800 62.800 ;
        RECT 65.200 62.200 66.000 66.200 ;
        RECT 71.600 66.200 72.400 79.800 ;
        RECT 74.800 75.800 75.600 79.800 ;
        RECT 75.000 75.600 75.600 75.800 ;
        RECT 78.000 75.800 78.800 79.800 ;
        RECT 78.000 75.600 78.600 75.800 ;
        RECT 75.000 75.000 78.600 75.600 ;
        RECT 73.200 71.600 74.000 73.200 ;
        RECT 75.000 72.400 75.600 75.000 ;
        RECT 76.400 72.800 77.200 74.400 ;
        RECT 74.800 71.600 75.600 72.400 ;
        RECT 75.000 68.400 75.600 71.600 ;
        RECT 79.600 72.300 80.400 72.400 ;
        RECT 81.200 72.300 82.000 72.400 ;
        RECT 79.600 71.700 82.000 72.300 ;
        RECT 79.600 70.800 80.400 71.700 ;
        RECT 81.200 71.600 82.000 71.700 ;
        RECT 76.400 69.600 78.800 70.400 ;
        RECT 75.000 68.200 76.600 68.400 ;
        RECT 75.000 67.800 76.800 68.200 ;
        RECT 71.600 65.600 73.400 66.200 ;
        RECT 72.600 64.400 73.400 65.600 ;
        RECT 76.000 64.400 76.800 67.800 ;
        RECT 81.200 64.800 82.000 66.400 ;
        RECT 71.600 63.600 73.400 64.400 ;
        RECT 74.800 63.600 76.800 64.400 ;
        RECT 72.600 62.200 73.400 63.600 ;
        RECT 76.000 62.200 76.800 63.600 ;
        RECT 82.800 62.200 83.600 79.800 ;
        RECT 84.400 62.200 85.200 79.800 ;
        RECT 89.200 75.800 90.000 79.800 ;
        RECT 89.400 75.600 90.000 75.800 ;
        RECT 92.400 75.800 93.200 79.800 ;
        RECT 92.400 75.600 93.000 75.800 ;
        RECT 89.400 75.000 93.000 75.600 ;
        RECT 92.400 72.400 93.000 75.000 ;
        RECT 92.400 71.600 93.200 72.400 ;
        RECT 96.600 71.800 98.600 79.800 ;
        RECT 104.600 78.400 105.400 79.800 ;
        RECT 103.600 77.600 105.400 78.400 ;
        RECT 104.600 72.400 105.400 77.600 ;
        RECT 106.000 73.600 106.800 74.400 ;
        RECT 106.200 72.400 106.800 73.600 ;
        RECT 109.200 73.600 110.000 74.400 ;
        RECT 109.200 72.400 109.800 73.600 ;
        RECT 110.600 72.400 111.400 79.800 ;
        RECT 122.200 78.400 123.000 79.800 ;
        RECT 121.200 77.600 123.000 78.400 ;
        RECT 122.200 72.600 123.000 77.600 ;
        RECT 104.600 71.800 105.600 72.400 ;
        RECT 106.200 72.300 107.600 72.400 ;
        RECT 108.400 72.300 109.800 72.400 ;
        RECT 106.200 71.800 109.800 72.300 ;
        RECT 110.400 71.800 111.400 72.400 ;
        RECT 121.200 71.800 123.000 72.600 ;
        RECT 92.400 70.300 93.000 71.600 ;
        RECT 94.000 70.300 94.800 70.400 ;
        RECT 92.400 69.700 94.800 70.300 ;
        RECT 92.400 68.400 93.000 69.700 ;
        RECT 94.000 69.600 94.800 69.700 ;
        RECT 95.600 68.800 96.400 70.400 ;
        RECT 91.400 68.200 93.000 68.400 ;
        RECT 91.200 67.800 93.000 68.200 ;
        RECT 97.200 68.400 97.800 71.800 ;
        RECT 98.800 68.800 99.600 70.400 ;
        RECT 97.200 68.200 98.000 68.400 ;
        RECT 86.000 64.800 86.800 66.400 ;
        RECT 91.200 62.200 92.000 67.800 ;
        RECT 97.200 67.600 99.600 68.200 ;
        RECT 100.400 67.600 101.200 69.200 ;
        RECT 103.600 68.800 104.400 70.400 ;
        RECT 105.000 68.400 105.600 71.800 ;
        RECT 106.800 71.700 109.200 71.800 ;
        RECT 106.800 71.600 107.600 71.700 ;
        RECT 108.400 71.600 109.200 71.700 ;
        RECT 110.400 68.400 111.000 71.800 ;
        RECT 111.600 68.800 112.400 70.400 ;
        RECT 121.400 68.400 122.000 71.800 ;
        RECT 122.800 70.300 123.600 71.200 ;
        RECT 124.400 70.300 125.200 79.800 ;
        RECT 127.600 72.400 128.400 79.800 ;
        RECT 130.800 72.400 131.600 79.800 ;
        RECT 127.600 71.800 131.600 72.400 ;
        RECT 132.400 71.800 133.200 79.800 ;
        RECT 134.000 72.400 134.800 79.800 ;
        RECT 137.200 79.200 141.200 79.800 ;
        RECT 137.200 72.400 138.000 79.200 ;
        RECT 134.000 71.800 138.000 72.400 ;
        RECT 138.800 71.800 139.600 78.600 ;
        RECT 140.400 71.800 141.200 79.200 ;
        RECT 128.400 70.400 129.200 70.800 ;
        RECT 132.400 70.400 133.000 71.800 ;
        RECT 138.800 71.200 139.400 71.800 ;
        RECT 142.000 71.600 142.800 73.200 ;
        RECT 134.800 70.400 135.600 70.800 ;
        RECT 137.400 70.600 139.400 71.200 ;
        RECT 137.400 70.400 138.000 70.600 ;
        RECT 122.800 69.700 125.200 70.300 ;
        RECT 122.800 69.600 123.600 69.700 ;
        RECT 102.000 68.200 102.800 68.400 ;
        RECT 102.000 67.600 103.600 68.200 ;
        RECT 105.000 67.600 107.600 68.400 ;
        RECT 108.400 67.600 111.000 68.400 ;
        RECT 113.200 68.200 114.000 68.400 ;
        RECT 112.400 67.600 114.000 68.200 ;
        RECT 121.200 67.600 122.000 68.400 ;
        RECT 94.200 66.200 97.800 66.600 ;
        RECT 99.000 66.200 99.600 67.600 ;
        RECT 102.800 67.200 103.600 67.600 ;
        RECT 102.200 66.200 105.800 66.600 ;
        RECT 106.800 66.200 107.400 67.600 ;
        RECT 108.600 66.200 109.200 67.600 ;
        RECT 112.400 67.200 113.200 67.600 ;
        RECT 110.200 66.200 113.800 66.600 ;
        RECT 94.000 66.000 98.000 66.200 ;
        RECT 94.000 62.200 94.800 66.000 ;
        RECT 97.200 62.800 98.000 66.000 ;
        RECT 98.800 63.400 99.600 66.200 ;
        RECT 100.400 62.800 101.200 66.200 ;
        RECT 97.200 62.200 101.200 62.800 ;
        RECT 102.000 66.000 106.000 66.200 ;
        RECT 102.000 62.200 102.800 66.000 ;
        RECT 105.200 62.200 106.000 66.000 ;
        RECT 106.800 62.200 107.600 66.200 ;
        RECT 108.400 62.200 109.200 66.200 ;
        RECT 110.000 66.000 114.000 66.200 ;
        RECT 110.000 62.200 110.800 66.000 ;
        RECT 113.200 62.200 114.000 66.000 ;
        RECT 119.600 64.800 120.400 66.400 ;
        RECT 121.400 64.200 122.000 67.600 ;
        RECT 121.200 62.200 122.000 64.200 ;
        RECT 124.400 62.200 125.200 69.700 ;
        RECT 127.600 69.800 129.200 70.400 ;
        RECT 130.800 69.800 133.200 70.400 ;
        RECT 127.600 69.600 128.400 69.800 ;
        RECT 126.000 68.300 126.800 68.400 ;
        RECT 129.200 68.300 130.000 69.200 ;
        RECT 126.000 67.700 130.000 68.300 ;
        RECT 126.000 67.600 126.800 67.700 ;
        RECT 129.200 67.600 130.000 67.700 ;
        RECT 130.800 68.300 131.400 69.800 ;
        RECT 132.400 69.600 133.200 69.800 ;
        RECT 134.000 69.800 135.600 70.400 ;
        RECT 134.000 69.600 134.800 69.800 ;
        RECT 137.200 69.600 138.000 70.400 ;
        RECT 140.400 69.600 141.200 71.200 ;
        RECT 143.600 70.300 144.400 79.800 ;
        RECT 149.400 72.400 150.200 79.800 ;
        RECT 150.800 73.600 151.600 74.400 ;
        RECT 151.000 72.400 151.600 73.600 ;
        RECT 149.400 71.800 150.400 72.400 ;
        RECT 151.000 71.800 152.400 72.400 ;
        RECT 148.400 70.300 149.200 70.400 ;
        RECT 143.600 69.700 149.200 70.300 ;
        RECT 135.600 68.300 136.400 69.200 ;
        RECT 130.800 67.700 136.400 68.300 ;
        RECT 126.000 64.800 126.800 66.400 ;
        RECT 130.800 66.200 131.400 67.700 ;
        RECT 135.600 67.600 136.400 67.700 ;
        RECT 130.800 62.200 131.600 66.200 ;
        RECT 132.400 65.600 133.200 66.400 ;
        RECT 137.400 66.200 138.000 69.600 ;
        RECT 138.600 68.800 139.400 69.600 ;
        RECT 138.800 68.400 139.400 68.800 ;
        RECT 138.800 67.600 139.600 68.400 ;
        RECT 140.400 68.300 141.200 68.400 ;
        RECT 143.600 68.300 144.400 69.700 ;
        RECT 148.400 68.800 149.200 69.700 ;
        RECT 149.800 68.400 150.400 71.800 ;
        RECT 151.600 71.600 152.400 71.800 ;
        RECT 140.400 67.700 144.400 68.300 ;
        RECT 140.400 67.600 141.200 67.700 ;
        RECT 143.600 66.200 144.400 67.700 ;
        RECT 146.800 68.200 147.600 68.400 ;
        RECT 146.800 67.600 148.400 68.200 ;
        RECT 149.800 67.600 152.400 68.400 ;
        RECT 147.600 67.200 148.400 67.600 ;
        RECT 147.000 66.200 150.600 66.600 ;
        RECT 151.600 66.200 152.200 67.600 ;
        RECT 132.200 64.800 133.000 65.600 ;
        RECT 137.000 62.200 138.600 66.200 ;
        RECT 142.600 65.600 144.400 66.200 ;
        RECT 146.800 66.000 150.800 66.200 ;
        RECT 142.600 62.200 143.400 65.600 ;
        RECT 146.800 62.200 147.600 66.000 ;
        RECT 150.000 62.200 150.800 66.000 ;
        RECT 151.600 62.200 152.400 66.200 ;
        RECT 153.200 62.200 154.000 79.800 ;
        RECT 157.000 72.600 157.800 79.800 ;
        RECT 157.000 71.800 158.800 72.600 ;
        RECT 156.400 69.600 157.200 71.200 ;
        RECT 158.000 68.400 158.600 71.800 ;
        RECT 158.000 67.600 158.800 68.400 ;
        RECT 154.800 66.300 155.600 66.400 ;
        RECT 156.400 66.300 157.200 66.400 ;
        RECT 154.800 65.700 157.200 66.300 ;
        RECT 154.800 64.800 155.600 65.700 ;
        RECT 156.400 65.600 157.200 65.700 ;
        RECT 158.000 64.400 158.600 67.600 ;
        RECT 159.600 64.800 160.400 66.400 ;
        RECT 158.000 62.200 158.800 64.400 ;
        RECT 1.200 55.800 2.000 59.800 ;
        RECT 2.800 56.000 3.600 59.800 ;
        RECT 6.000 56.000 6.800 59.800 ;
        RECT 9.200 57.800 10.000 59.800 ;
        RECT 2.800 55.800 6.800 56.000 ;
        RECT 1.400 54.400 2.000 55.800 ;
        RECT 3.000 55.400 6.600 55.800 ;
        RECT 5.200 54.400 6.000 54.800 ;
        RECT 9.400 54.400 10.000 57.800 ;
        RECT 1.200 53.600 3.800 54.400 ;
        RECT 5.200 53.800 6.800 54.400 ;
        RECT 6.000 53.600 6.800 53.800 ;
        RECT 9.200 53.600 10.000 54.400 ;
        RECT 1.200 50.200 2.000 50.400 ;
        RECT 3.200 50.200 3.800 53.600 ;
        RECT 4.400 52.300 5.200 53.200 ;
        RECT 9.400 52.300 10.000 53.600 ;
        RECT 4.400 51.700 10.000 52.300 ;
        RECT 4.400 51.600 5.200 51.700 ;
        RECT 9.400 50.200 10.000 51.700 ;
        RECT 10.800 52.300 11.600 52.400 ;
        RECT 14.000 52.300 14.800 59.800 ;
        RECT 16.200 56.400 17.000 59.800 ;
        RECT 20.600 56.400 21.400 57.200 ;
        RECT 16.200 55.800 18.000 56.400 ;
        RECT 10.800 51.700 14.800 52.300 ;
        RECT 10.800 50.800 11.600 51.700 ;
        RECT 14.000 50.300 14.800 51.700 ;
        RECT 15.600 50.300 16.400 50.400 ;
        RECT 1.200 49.600 2.600 50.200 ;
        RECT 3.200 49.600 4.200 50.200 ;
        RECT 2.000 48.400 2.600 49.600 ;
        RECT 2.000 47.600 2.800 48.400 ;
        RECT 3.400 44.400 4.200 49.600 ;
        RECT 9.200 49.400 11.000 50.200 ;
        RECT 3.400 43.600 5.200 44.400 ;
        RECT 3.400 42.200 4.200 43.600 ;
        RECT 10.200 42.200 11.000 49.400 ;
        RECT 14.000 49.700 16.400 50.300 ;
        RECT 14.000 42.200 14.800 49.700 ;
        RECT 15.600 48.800 16.400 49.700 ;
        RECT 17.200 42.200 18.000 55.800 ;
        RECT 20.400 55.600 21.200 56.400 ;
        RECT 22.000 55.800 22.800 59.800 ;
        RECT 28.400 57.600 29.200 59.800 ;
        RECT 20.400 52.200 21.200 52.400 ;
        RECT 22.200 52.200 22.800 55.800 ;
        RECT 28.600 54.400 29.200 57.600 ;
        RECT 23.600 52.800 24.400 54.400 ;
        RECT 28.400 53.600 29.200 54.400 ;
        RECT 32.800 58.300 33.600 59.800 ;
        RECT 34.800 58.300 35.600 58.400 ;
        RECT 32.800 57.700 35.600 58.300 ;
        RECT 32.800 54.200 33.600 57.700 ;
        RECT 34.800 57.600 35.600 57.700 ;
        RECT 40.600 56.400 41.400 59.800 ;
        RECT 39.600 55.800 41.400 56.400 ;
        RECT 25.200 52.200 26.000 52.400 ;
        RECT 20.400 51.600 22.800 52.200 ;
        RECT 24.400 51.600 26.000 52.200 ;
        RECT 20.600 50.200 21.200 51.600 ;
        RECT 24.400 51.200 25.200 51.600 ;
        RECT 28.600 50.200 29.200 53.600 ;
        RECT 31.800 53.800 33.600 54.200 ;
        RECT 31.800 53.600 33.400 53.800 ;
        RECT 38.000 53.600 38.800 55.200 ;
        RECT 31.800 50.400 32.400 53.600 ;
        RECT 34.000 51.600 35.600 52.400 ;
        RECT 20.400 42.200 21.200 50.200 ;
        RECT 22.000 49.600 26.000 50.200 ;
        RECT 22.000 42.200 22.800 49.600 ;
        RECT 25.200 42.200 26.000 49.600 ;
        RECT 28.400 49.400 30.200 50.200 ;
        RECT 31.600 49.600 32.400 50.400 ;
        RECT 36.400 50.300 37.200 51.200 ;
        RECT 38.000 50.300 38.800 50.400 ;
        RECT 36.400 49.700 38.800 50.300 ;
        RECT 36.400 49.600 37.200 49.700 ;
        RECT 38.000 49.600 38.800 49.700 ;
        RECT 29.400 44.400 30.200 49.400 ;
        RECT 31.800 47.000 32.400 49.600 ;
        RECT 33.200 47.600 34.000 49.200 ;
        RECT 31.800 46.400 35.400 47.000 ;
        RECT 31.800 46.200 32.400 46.400 ;
        RECT 29.400 43.600 30.800 44.400 ;
        RECT 29.400 42.200 30.200 43.600 ;
        RECT 31.600 42.200 32.400 46.200 ;
        RECT 34.800 46.200 35.400 46.400 ;
        RECT 34.800 42.200 35.600 46.200 ;
        RECT 39.600 42.200 40.400 55.800 ;
        RECT 48.800 54.200 49.600 59.800 ;
        RECT 54.000 55.800 54.800 59.800 ;
        RECT 55.600 56.000 56.400 59.800 ;
        RECT 58.800 56.000 59.600 59.800 ;
        RECT 55.600 55.800 59.600 56.000 ;
        RECT 54.200 54.400 54.800 55.800 ;
        RECT 55.800 55.400 59.400 55.800 ;
        RECT 58.000 54.400 58.800 54.800 ;
        RECT 47.800 53.800 49.600 54.200 ;
        RECT 47.800 53.600 49.400 53.800 ;
        RECT 54.000 53.600 56.600 54.400 ;
        RECT 58.000 53.800 59.600 54.400 ;
        RECT 64.000 54.200 64.800 59.800 ;
        RECT 64.000 53.800 65.800 54.200 ;
        RECT 58.800 53.600 59.600 53.800 ;
        RECT 64.200 53.600 65.800 53.800 ;
        RECT 47.800 50.400 48.400 53.600 ;
        RECT 56.000 52.400 56.600 53.600 ;
        RECT 50.000 51.600 51.600 52.400 ;
        RECT 55.600 51.600 56.600 52.400 ;
        RECT 57.200 51.600 58.000 53.200 ;
        RECT 62.000 51.600 63.600 52.400 ;
        RECT 41.200 48.800 42.000 50.400 ;
        RECT 47.600 49.600 48.400 50.400 ;
        RECT 52.400 49.600 53.200 51.200 ;
        RECT 54.000 50.200 54.800 50.400 ;
        RECT 56.000 50.200 56.600 51.600 ;
        RECT 54.000 49.600 55.400 50.200 ;
        RECT 56.000 49.600 57.000 50.200 ;
        RECT 60.400 49.600 61.200 51.200 ;
        RECT 65.200 50.400 65.800 53.600 ;
        RECT 66.800 52.300 67.600 59.800 ;
        RECT 68.400 55.600 69.200 57.200 ;
        RECT 73.000 55.800 74.600 59.800 ;
        RECT 71.600 52.800 72.400 54.400 ;
        RECT 73.400 52.400 74.000 55.800 ;
        RECT 78.000 55.600 78.800 57.200 ;
        RECT 74.800 53.600 75.600 54.400 ;
        RECT 74.800 53.200 75.400 53.600 ;
        RECT 74.600 52.400 75.400 53.200 ;
        RECT 70.000 52.300 70.800 52.400 ;
        RECT 66.800 52.200 70.800 52.300 ;
        RECT 66.800 51.700 71.600 52.200 ;
        RECT 65.200 49.600 66.000 50.400 ;
        RECT 47.800 47.000 48.400 49.600 ;
        RECT 49.200 47.600 50.000 49.200 ;
        RECT 54.800 48.400 55.400 49.600 ;
        RECT 54.800 47.600 55.600 48.400 ;
        RECT 47.800 46.400 51.400 47.000 ;
        RECT 47.800 46.200 48.400 46.400 ;
        RECT 47.600 42.200 48.400 46.200 ;
        RECT 50.800 42.200 51.600 46.400 ;
        RECT 56.200 42.200 57.000 49.600 ;
        RECT 63.600 47.600 64.400 49.200 ;
        RECT 65.200 47.000 65.800 49.600 ;
        RECT 62.200 46.400 65.800 47.000 ;
        RECT 62.200 46.200 62.800 46.400 ;
        RECT 62.000 42.200 62.800 46.200 ;
        RECT 65.200 46.200 65.800 46.400 ;
        RECT 65.200 42.200 66.000 46.200 ;
        RECT 66.800 42.200 67.600 51.700 ;
        RECT 70.000 51.600 71.600 51.700 ;
        RECT 73.200 51.600 74.000 52.400 ;
        RECT 70.800 51.200 71.600 51.600 ;
        RECT 73.400 51.400 74.000 51.600 ;
        RECT 73.400 50.800 75.400 51.400 ;
        RECT 76.400 50.800 77.200 52.400 ;
        RECT 74.800 50.200 75.400 50.800 ;
        RECT 70.000 49.600 74.000 50.200 ;
        RECT 70.000 42.200 70.800 49.600 ;
        RECT 73.200 42.800 74.000 49.600 ;
        RECT 74.800 43.400 75.600 50.200 ;
        RECT 76.400 42.800 77.200 50.200 ;
        RECT 73.200 42.200 77.200 42.800 ;
        RECT 79.600 42.200 80.400 59.800 ;
        RECT 81.800 58.400 82.600 59.800 ;
        RECT 81.200 57.600 82.600 58.400 ;
        RECT 81.800 56.400 82.600 57.600 ;
        RECT 81.800 55.800 83.600 56.400 ;
        RECT 82.800 42.200 83.600 55.800 ;
        RECT 86.000 55.600 86.800 57.200 ;
        RECT 87.600 42.200 88.400 59.800 ;
        RECT 89.200 42.200 90.000 59.800 ;
        RECT 90.800 55.600 91.600 57.200 ;
        RECT 93.000 56.400 93.800 59.800 ;
        RECT 97.800 56.400 98.600 59.800 ;
        RECT 93.000 55.800 94.800 56.400 ;
        RECT 97.800 55.800 99.600 56.400 ;
        RECT 92.400 48.800 93.200 50.400 ;
        RECT 94.000 42.200 94.800 55.800 ;
        RECT 95.600 53.600 96.400 55.200 ;
        RECT 98.800 52.300 99.600 55.800 ;
        RECT 100.400 52.300 101.200 52.400 ;
        RECT 98.800 51.700 101.200 52.300 ;
        RECT 98.800 42.200 99.600 51.700 ;
        RECT 100.400 51.600 101.200 51.700 ;
        RECT 103.600 50.300 104.400 59.800 ;
        RECT 105.800 56.400 106.600 59.800 ;
        RECT 105.800 55.800 107.600 56.400 ;
        RECT 117.400 55.800 119.000 59.800 ;
        RECT 105.200 50.300 106.000 50.400 ;
        RECT 103.600 49.700 106.000 50.300 ;
        RECT 103.600 42.200 104.400 49.700 ;
        RECT 105.200 48.800 106.000 49.700 ;
        RECT 106.800 48.300 107.600 55.800 ;
        RECT 110.000 54.300 110.800 54.400 ;
        RECT 116.400 54.300 117.200 54.400 ;
        RECT 110.000 53.700 117.200 54.300 ;
        RECT 110.000 53.600 110.800 53.700 ;
        RECT 116.400 53.600 117.200 53.700 ;
        RECT 116.600 53.200 117.200 53.600 ;
        RECT 116.600 52.400 117.400 53.200 ;
        RECT 118.000 52.400 118.600 55.800 ;
        RECT 119.600 52.800 120.400 54.400 ;
        RECT 126.400 54.200 127.200 59.800 ;
        RECT 129.400 56.400 130.200 57.200 ;
        RECT 129.200 55.600 130.000 56.400 ;
        RECT 130.800 55.600 131.600 59.800 ;
        RECT 135.600 55.800 136.400 59.800 ;
        RECT 137.200 56.000 138.000 59.800 ;
        RECT 140.400 56.000 141.200 59.800 ;
        RECT 137.200 55.800 141.200 56.000 ;
        RECT 145.200 55.800 146.000 59.800 ;
        RECT 146.600 56.400 147.400 57.200 ;
        RECT 126.400 53.800 128.200 54.200 ;
        RECT 126.600 53.600 128.200 53.800 ;
        RECT 114.800 50.800 115.600 52.400 ;
        RECT 118.000 51.600 118.800 52.400 ;
        RECT 121.200 52.200 122.000 52.400 ;
        RECT 120.400 51.600 122.000 52.200 ;
        RECT 124.400 51.600 126.000 52.400 ;
        RECT 118.000 51.400 118.600 51.600 ;
        RECT 116.600 50.800 118.600 51.400 ;
        RECT 120.400 51.200 121.200 51.600 ;
        RECT 116.600 50.200 117.200 50.800 ;
        RECT 108.400 48.300 109.200 48.400 ;
        RECT 106.800 47.700 109.200 48.300 ;
        RECT 106.800 42.200 107.600 47.700 ;
        RECT 108.400 47.600 109.200 47.700 ;
        RECT 114.800 42.800 115.600 50.200 ;
        RECT 116.400 43.400 117.200 50.200 ;
        RECT 118.000 49.600 122.000 50.200 ;
        RECT 122.800 49.600 123.600 51.200 ;
        RECT 127.600 50.400 128.200 53.600 ;
        RECT 129.200 52.200 130.000 52.400 ;
        RECT 131.000 52.200 131.600 55.600 ;
        RECT 135.800 54.400 136.400 55.800 ;
        RECT 137.400 55.400 141.000 55.800 ;
        RECT 139.600 54.400 140.400 54.800 ;
        RECT 135.600 53.600 138.200 54.400 ;
        RECT 139.600 53.800 141.200 54.400 ;
        RECT 140.400 53.600 141.200 53.800 ;
        RECT 134.000 52.200 134.800 52.400 ;
        RECT 129.200 51.600 131.600 52.200 ;
        RECT 133.200 51.600 134.800 52.200 ;
        RECT 127.600 49.600 128.400 50.400 ;
        RECT 129.400 50.200 130.000 51.600 ;
        RECT 133.200 51.200 134.000 51.600 ;
        RECT 137.600 50.400 138.200 53.600 ;
        RECT 143.600 52.800 144.400 54.400 ;
        RECT 145.200 52.400 145.800 55.800 ;
        RECT 146.800 55.600 147.600 56.400 ;
        RECT 148.400 55.800 149.200 59.800 ;
        RECT 150.000 56.000 150.800 59.800 ;
        RECT 153.200 56.000 154.000 59.800 ;
        RECT 150.000 55.800 154.000 56.000 ;
        RECT 156.400 57.600 157.200 59.800 ;
        RECT 148.600 54.400 149.200 55.800 ;
        RECT 150.200 55.400 153.800 55.800 ;
        RECT 156.400 54.400 157.000 57.600 ;
        RECT 148.400 53.600 151.000 54.400 ;
        RECT 140.400 52.300 141.200 52.400 ;
        RECT 142.000 52.300 142.800 52.400 ;
        RECT 140.400 52.200 142.800 52.300 ;
        RECT 145.200 52.200 146.000 52.400 ;
        RECT 146.800 52.200 147.600 52.400 ;
        RECT 140.400 51.700 143.600 52.200 ;
        RECT 140.400 51.600 141.200 51.700 ;
        RECT 142.000 51.600 143.600 51.700 ;
        RECT 145.200 51.600 147.600 52.200 ;
        RECT 142.800 51.200 143.600 51.600 ;
        RECT 135.600 50.200 136.400 50.400 ;
        RECT 118.000 42.800 118.800 49.600 ;
        RECT 114.800 42.200 118.800 42.800 ;
        RECT 121.200 42.200 122.000 49.600 ;
        RECT 126.000 47.600 126.800 49.200 ;
        RECT 127.600 47.000 128.200 49.600 ;
        RECT 124.600 46.400 128.200 47.000 ;
        RECT 124.600 46.200 125.200 46.400 ;
        RECT 124.400 42.200 125.200 46.200 ;
        RECT 127.600 46.200 128.200 46.400 ;
        RECT 127.600 42.200 128.400 46.200 ;
        RECT 129.200 42.200 130.000 50.200 ;
        RECT 130.800 49.600 134.800 50.200 ;
        RECT 135.600 49.600 137.000 50.200 ;
        RECT 137.600 49.600 139.600 50.400 ;
        RECT 146.800 50.200 147.400 51.600 ;
        RECT 148.400 50.200 149.200 50.400 ;
        RECT 150.400 50.200 151.000 53.600 ;
        RECT 156.400 53.600 157.200 54.400 ;
        RECT 156.400 50.200 157.000 53.600 ;
        RECT 142.000 49.600 146.000 50.200 ;
        RECT 130.800 42.200 131.600 49.600 ;
        RECT 134.000 42.200 134.800 49.600 ;
        RECT 136.400 48.400 137.000 49.600 ;
        RECT 136.400 47.600 137.200 48.400 ;
        RECT 137.800 42.200 138.600 49.600 ;
        RECT 142.000 42.200 142.800 49.600 ;
        RECT 145.200 42.200 146.000 49.600 ;
        RECT 146.800 42.200 147.600 50.200 ;
        RECT 148.400 49.600 149.800 50.200 ;
        RECT 150.400 49.600 151.400 50.200 ;
        RECT 149.200 48.400 149.800 49.600 ;
        RECT 149.200 47.600 150.000 48.400 ;
        RECT 150.600 44.400 151.400 49.600 ;
        RECT 155.400 49.400 157.200 50.200 ;
        RECT 155.400 44.400 156.200 49.400 ;
        RECT 150.600 43.600 152.400 44.400 ;
        RECT 154.800 43.600 156.200 44.400 ;
        RECT 150.600 42.200 151.400 43.600 ;
        RECT 155.400 42.200 156.200 43.600 ;
        RECT 159.600 42.200 160.400 59.800 ;
        RECT 1.200 32.400 2.000 39.800 ;
        RECT 2.600 32.400 3.400 32.600 ;
        RECT 1.200 31.800 3.400 32.400 ;
        RECT 5.600 32.400 7.200 39.800 ;
        RECT 9.200 32.400 10.000 32.600 ;
        RECT 10.800 32.400 11.600 39.800 ;
        RECT 5.600 31.800 7.600 32.400 ;
        RECT 9.200 31.800 11.600 32.400 ;
        RECT 15.000 32.400 15.800 39.800 ;
        RECT 16.400 33.600 17.200 34.400 ;
        RECT 16.600 32.400 17.200 33.600 ;
        RECT 20.400 34.300 21.200 39.800 ;
        RECT 23.600 34.300 24.400 34.400 ;
        RECT 20.400 33.700 24.400 34.300 ;
        RECT 15.000 31.800 16.000 32.400 ;
        RECT 16.600 31.800 18.000 32.400 ;
        RECT 2.800 31.200 3.400 31.800 ;
        RECT 2.800 30.600 6.200 31.200 ;
        RECT 5.400 30.400 6.200 30.600 ;
        RECT 7.000 30.400 7.600 31.800 ;
        RECT 7.000 30.300 8.400 30.400 ;
        RECT 3.200 29.800 4.000 30.000 ;
        RECT 7.000 29.800 13.100 30.300 ;
        RECT 3.200 29.200 5.800 29.800 ;
        RECT 5.200 28.600 5.800 29.200 ;
        RECT 6.600 29.700 13.100 29.800 ;
        RECT 6.600 29.600 8.400 29.700 ;
        RECT 6.600 29.200 7.600 29.600 ;
        RECT 5.200 27.800 6.000 28.600 ;
        RECT 2.600 26.800 3.400 27.000 ;
        RECT 1.200 26.200 3.400 26.800 ;
        RECT 1.200 22.200 2.000 26.200 ;
        RECT 6.600 25.800 7.200 29.200 ;
        RECT 12.500 28.400 13.100 29.700 ;
        RECT 14.000 28.800 14.800 30.400 ;
        RECT 15.400 28.400 16.000 31.800 ;
        RECT 17.200 31.600 18.000 31.800 ;
        RECT 17.300 30.300 17.900 31.600 ;
        RECT 20.400 30.300 21.200 33.700 ;
        RECT 23.600 33.600 24.400 33.700 ;
        RECT 17.300 29.700 21.200 30.300 ;
        RECT 12.400 28.200 13.200 28.400 ;
        RECT 12.400 27.600 14.000 28.200 ;
        RECT 15.400 27.600 18.000 28.400 ;
        RECT 13.200 27.200 14.000 27.600 ;
        RECT 9.200 26.800 10.000 27.000 ;
        RECT 9.200 26.200 11.600 26.800 ;
        RECT 12.600 26.200 16.200 26.600 ;
        RECT 17.200 26.200 17.800 27.600 ;
        RECT 20.400 26.200 21.200 29.700 ;
        RECT 5.600 22.200 7.200 25.800 ;
        RECT 10.800 22.200 11.600 26.200 ;
        RECT 12.400 26.000 16.400 26.200 ;
        RECT 12.400 22.200 13.200 26.000 ;
        RECT 15.600 22.200 16.400 26.000 ;
        RECT 17.200 22.200 18.000 26.200 ;
        RECT 19.400 25.600 21.200 26.200 ;
        RECT 25.200 30.300 26.000 39.800 ;
        RECT 29.200 33.600 30.000 34.400 ;
        RECT 29.200 32.400 29.800 33.600 ;
        RECT 30.600 32.400 31.400 39.800 ;
        RECT 35.400 38.400 36.200 39.800 ;
        RECT 35.400 37.600 37.200 38.400 ;
        RECT 35.400 32.600 36.200 37.600 ;
        RECT 28.400 31.800 29.800 32.400 ;
        RECT 28.400 31.600 29.200 31.800 ;
        RECT 30.400 31.600 32.400 32.400 ;
        RECT 35.400 31.800 37.200 32.600 ;
        RECT 39.600 32.400 40.400 39.800 ;
        RECT 42.800 32.400 43.600 39.800 ;
        RECT 39.600 31.800 43.600 32.400 ;
        RECT 44.400 31.800 45.200 39.800 ;
        RECT 53.400 32.400 54.200 39.800 ;
        RECT 54.800 33.600 55.600 34.400 ;
        RECT 55.000 32.400 55.600 33.600 ;
        RECT 53.400 31.800 54.400 32.400 ;
        RECT 55.000 31.800 56.400 32.400 ;
        RECT 57.200 31.800 58.000 39.800 ;
        RECT 58.800 32.400 59.600 39.800 ;
        RECT 62.000 32.400 62.800 39.800 ;
        RECT 58.800 31.800 62.800 32.400 ;
        RECT 28.500 30.300 29.100 31.600 ;
        RECT 25.200 29.700 29.100 30.300 ;
        RECT 25.200 26.200 26.000 29.700 ;
        RECT 30.400 28.400 31.000 31.600 ;
        RECT 31.600 28.800 32.400 30.400 ;
        RECT 34.800 29.600 35.600 31.200 ;
        RECT 36.400 28.400 37.000 31.800 ;
        RECT 40.400 30.400 41.200 30.800 ;
        RECT 44.400 30.400 45.000 31.800 ;
        RECT 39.600 29.800 41.200 30.400 ;
        RECT 42.800 29.800 45.200 30.400 ;
        RECT 39.600 29.600 40.400 29.800 ;
        RECT 28.400 27.600 31.000 28.400 ;
        RECT 33.200 28.200 34.000 28.400 ;
        RECT 32.400 27.600 34.000 28.200 ;
        RECT 36.400 27.600 37.200 28.400 ;
        RECT 41.200 27.600 42.000 29.200 ;
        RECT 28.600 26.200 29.200 27.600 ;
        RECT 32.400 27.200 33.200 27.600 ;
        RECT 30.200 26.200 33.800 26.600 ;
        RECT 25.200 25.600 27.000 26.200 ;
        RECT 19.400 22.200 20.200 25.600 ;
        RECT 26.200 24.400 27.000 25.600 ;
        RECT 25.200 23.600 27.000 24.400 ;
        RECT 26.200 22.200 27.000 23.600 ;
        RECT 28.400 22.200 29.200 26.200 ;
        RECT 30.000 26.000 34.000 26.200 ;
        RECT 30.000 22.200 30.800 26.000 ;
        RECT 33.200 22.200 34.000 26.000 ;
        RECT 36.400 24.200 37.000 27.600 ;
        RECT 38.000 24.800 38.800 26.400 ;
        RECT 42.800 26.200 43.400 29.800 ;
        RECT 44.400 29.600 45.200 29.800 ;
        RECT 52.400 28.800 53.200 30.400 ;
        RECT 53.800 28.400 54.400 31.800 ;
        RECT 55.600 31.600 56.400 31.800 ;
        RECT 57.400 30.400 58.000 31.800 ;
        RECT 61.200 30.400 62.000 30.800 ;
        RECT 57.200 29.800 59.600 30.400 ;
        RECT 61.200 29.800 62.800 30.400 ;
        RECT 57.200 29.600 58.000 29.800 ;
        RECT 50.800 28.200 51.600 28.400 ;
        RECT 50.800 27.600 52.400 28.200 ;
        RECT 53.800 27.600 56.400 28.400 ;
        RECT 51.600 27.200 52.400 27.600 ;
        RECT 36.400 22.200 37.200 24.200 ;
        RECT 42.800 22.200 43.600 26.200 ;
        RECT 44.400 25.600 45.200 26.400 ;
        RECT 51.000 26.200 54.600 26.600 ;
        RECT 55.600 26.300 56.200 27.600 ;
        RECT 57.200 26.300 58.000 26.400 ;
        RECT 50.800 26.000 54.800 26.200 ;
        RECT 44.200 24.800 45.000 25.600 ;
        RECT 50.800 22.200 51.600 26.000 ;
        RECT 54.000 22.200 54.800 26.000 ;
        RECT 55.600 25.700 58.000 26.300 ;
        RECT 59.000 26.200 59.600 29.800 ;
        RECT 62.000 29.600 62.800 29.800 ;
        RECT 60.400 27.600 61.200 29.200 ;
        RECT 55.600 22.200 56.400 25.700 ;
        RECT 57.200 25.600 58.000 25.700 ;
        RECT 57.400 24.800 58.200 25.600 ;
        RECT 58.800 22.200 59.600 26.200 ;
        RECT 63.600 24.800 64.400 26.400 ;
        RECT 65.200 26.300 66.000 39.800 ;
        RECT 66.800 31.800 67.600 39.800 ;
        RECT 68.400 32.400 69.200 39.800 ;
        RECT 71.600 32.400 72.400 39.800 ;
        RECT 68.400 31.800 72.400 32.400 ;
        RECT 73.200 32.400 74.000 39.800 ;
        RECT 76.400 32.400 77.200 39.800 ;
        RECT 73.200 31.800 77.200 32.400 ;
        RECT 78.000 31.800 78.800 39.800 ;
        RECT 79.600 31.800 80.400 39.800 ;
        RECT 82.800 35.800 83.600 39.800 ;
        RECT 67.000 30.400 67.600 31.800 ;
        RECT 70.800 30.400 71.600 30.800 ;
        RECT 74.000 30.400 74.800 30.800 ;
        RECT 78.000 30.400 78.600 31.800 ;
        RECT 79.600 30.400 80.200 31.800 ;
        RECT 82.800 31.600 83.400 35.800 ;
        RECT 81.000 31.000 83.400 31.600 ;
        RECT 66.800 29.800 69.200 30.400 ;
        RECT 70.800 29.800 72.400 30.400 ;
        RECT 66.800 29.600 67.600 29.800 ;
        RECT 66.800 26.300 67.600 26.400 ;
        RECT 65.200 25.700 67.600 26.300 ;
        RECT 68.600 26.200 69.200 29.800 ;
        RECT 71.600 29.600 72.400 29.800 ;
        RECT 73.200 29.800 74.800 30.400 ;
        RECT 76.400 29.800 78.800 30.400 ;
        RECT 73.200 29.600 74.000 29.800 ;
        RECT 70.000 27.600 70.800 29.200 ;
        RECT 74.800 27.600 75.600 29.200 ;
        RECT 65.200 22.200 66.000 25.700 ;
        RECT 66.800 25.600 67.600 25.700 ;
        RECT 67.000 24.800 67.800 25.600 ;
        RECT 68.400 22.200 69.200 26.200 ;
        RECT 76.400 26.200 77.000 29.800 ;
        RECT 78.000 29.600 78.800 29.800 ;
        RECT 79.600 29.600 80.400 30.400 ;
        RECT 76.400 22.200 77.200 26.200 ;
        RECT 78.000 25.600 78.800 26.400 ;
        RECT 79.600 26.200 80.200 29.600 ;
        RECT 81.000 27.600 81.600 31.000 ;
        RECT 82.800 29.600 83.600 30.400 ;
        RECT 82.800 28.800 83.400 29.600 ;
        RECT 82.400 28.200 83.400 28.800 ;
        RECT 82.400 28.000 83.200 28.200 ;
        RECT 84.400 27.600 85.200 29.200 ;
        RECT 80.800 27.400 81.600 27.600 ;
        RECT 80.800 27.000 83.800 27.400 ;
        RECT 80.800 26.800 85.000 27.000 ;
        RECT 86.000 26.800 86.800 28.400 ;
        RECT 83.200 26.400 85.000 26.800 ;
        RECT 84.400 26.200 85.000 26.400 ;
        RECT 87.600 26.200 88.400 39.800 ;
        RECT 89.200 31.600 90.000 33.200 ;
        RECT 90.800 31.200 91.600 39.800 ;
        RECT 95.000 32.400 95.800 39.800 ;
        RECT 97.200 32.400 98.000 39.800 ;
        RECT 100.400 32.400 101.200 39.800 ;
        RECT 95.000 31.800 96.400 32.400 ;
        RECT 97.200 31.800 101.200 32.400 ;
        RECT 102.000 31.800 102.800 39.800 ;
        RECT 106.200 36.400 107.000 39.800 ;
        RECT 105.200 35.600 107.000 36.400 ;
        RECT 106.200 32.400 107.000 35.600 ;
        RECT 107.600 33.600 108.400 34.400 ;
        RECT 107.800 32.400 108.400 33.600 ;
        RECT 110.000 32.400 110.800 39.800 ;
        RECT 113.200 32.400 114.000 39.800 ;
        RECT 106.200 31.800 107.200 32.400 ;
        RECT 107.800 31.800 109.200 32.400 ;
        RECT 110.000 31.800 114.000 32.400 ;
        RECT 114.800 31.800 115.600 39.800 ;
        RECT 121.200 35.800 122.000 39.800 ;
        RECT 121.400 35.600 122.000 35.800 ;
        RECT 124.400 35.800 125.200 39.800 ;
        RECT 124.400 35.600 125.000 35.800 ;
        RECT 121.400 35.000 125.000 35.600 ;
        RECT 121.400 32.400 122.000 35.000 ;
        RECT 122.800 32.800 123.600 34.400 ;
        RECT 90.800 30.800 94.800 31.200 ;
        RECT 90.800 30.600 95.000 30.800 ;
        RECT 94.200 30.000 95.000 30.600 ;
        RECT 95.800 30.400 96.400 31.800 ;
        RECT 98.000 30.400 98.800 30.800 ;
        RECT 102.000 30.400 102.600 31.800 ;
        RECT 92.800 28.400 93.600 29.200 ;
        RECT 92.400 27.600 93.400 28.400 ;
        RECT 94.400 27.000 95.000 30.000 ;
        RECT 95.600 29.600 96.400 30.400 ;
        RECT 97.200 29.800 98.800 30.400 ;
        RECT 100.400 29.800 102.800 30.400 ;
        RECT 97.200 29.600 98.000 29.800 ;
        RECT 95.800 28.300 96.400 29.600 ;
        RECT 97.200 28.300 98.000 28.400 ;
        RECT 95.700 27.700 98.000 28.300 ;
        RECT 92.600 26.400 95.000 27.000 ;
        RECT 77.800 24.800 78.600 25.600 ;
        RECT 79.600 25.200 81.000 26.200 ;
        RECT 80.200 22.200 81.000 25.200 ;
        RECT 84.400 22.200 85.200 26.200 ;
        RECT 87.600 25.600 89.400 26.200 ;
        RECT 88.600 24.400 89.400 25.600 ;
        RECT 90.800 24.800 91.600 26.400 ;
        RECT 88.600 23.600 90.000 24.400 ;
        RECT 92.600 24.200 93.200 26.400 ;
        RECT 95.800 26.200 96.400 27.700 ;
        RECT 97.200 27.600 98.000 27.700 ;
        RECT 98.800 27.600 99.600 29.200 ;
        RECT 88.600 22.200 89.400 23.600 ;
        RECT 92.400 22.200 93.200 24.200 ;
        RECT 95.600 22.200 96.400 26.200 ;
        RECT 100.400 26.400 101.000 29.800 ;
        RECT 102.000 29.600 102.800 29.800 ;
        RECT 105.200 28.800 106.000 30.400 ;
        RECT 106.600 28.400 107.200 31.800 ;
        RECT 108.400 31.600 109.200 31.800 ;
        RECT 110.800 30.400 111.600 30.800 ;
        RECT 114.800 30.400 115.400 31.800 ;
        RECT 121.200 31.600 122.000 32.400 ;
        RECT 110.000 29.800 111.600 30.400 ;
        RECT 113.200 29.800 115.600 30.400 ;
        RECT 110.000 29.600 110.800 29.800 ;
        RECT 103.600 28.200 104.400 28.400 ;
        RECT 103.600 27.600 105.200 28.200 ;
        RECT 106.600 27.600 109.200 28.400 ;
        RECT 111.600 27.600 112.400 29.200 ;
        RECT 104.400 27.200 105.200 27.600 ;
        RECT 100.400 22.200 101.200 26.400 ;
        RECT 102.000 25.600 102.800 26.400 ;
        RECT 103.800 26.200 107.400 26.600 ;
        RECT 108.400 26.200 109.000 27.600 ;
        RECT 113.200 26.200 113.800 29.800 ;
        RECT 114.800 29.600 115.600 29.800 ;
        RECT 121.400 28.400 122.000 31.600 ;
        RECT 126.000 30.800 126.800 32.400 ;
        RECT 127.600 31.800 128.400 39.800 ;
        RECT 129.200 32.400 130.000 39.800 ;
        RECT 132.400 32.400 133.200 39.800 ;
        RECT 129.200 31.800 133.200 32.400 ;
        RECT 134.000 31.800 134.800 39.800 ;
        RECT 135.600 32.400 136.400 39.800 ;
        RECT 138.800 32.400 139.600 39.800 ;
        RECT 135.600 31.800 139.600 32.400 ;
        RECT 141.000 32.600 141.800 39.800 ;
        RECT 146.000 33.600 146.800 34.400 ;
        RECT 141.000 31.800 142.800 32.600 ;
        RECT 146.000 32.400 146.600 33.600 ;
        RECT 147.400 32.400 148.200 39.800 ;
        RECT 152.200 32.600 153.000 39.800 ;
        RECT 145.200 31.800 146.600 32.400 ;
        RECT 127.800 30.400 128.400 31.800 ;
        RECT 131.600 30.400 132.400 30.800 ;
        RECT 134.200 30.400 134.800 31.800 ;
        RECT 138.000 30.400 138.800 30.800 ;
        RECT 123.600 29.600 125.200 30.400 ;
        RECT 127.600 29.800 130.000 30.400 ;
        RECT 131.600 29.800 133.200 30.400 ;
        RECT 127.600 29.600 128.400 29.800 ;
        RECT 129.200 29.600 130.000 29.800 ;
        RECT 132.400 29.600 133.200 29.800 ;
        RECT 134.000 29.800 136.400 30.400 ;
        RECT 138.000 29.800 139.600 30.400 ;
        RECT 134.000 29.600 134.800 29.800 ;
        RECT 121.400 28.300 123.000 28.400 ;
        RECT 124.400 28.300 125.200 28.400 ;
        RECT 121.400 27.800 125.200 28.300 ;
        RECT 122.400 27.700 125.200 27.800 ;
        RECT 122.400 27.600 123.600 27.700 ;
        RECT 124.400 27.600 125.200 27.700 ;
        RECT 103.600 26.000 107.600 26.200 ;
        RECT 101.800 24.800 102.600 25.600 ;
        RECT 103.600 22.200 104.400 26.000 ;
        RECT 106.800 22.200 107.600 26.000 ;
        RECT 108.400 22.200 109.200 26.200 ;
        RECT 113.200 22.200 114.000 26.200 ;
        RECT 114.800 25.600 115.600 26.400 ;
        RECT 114.600 24.800 115.400 25.600 ;
        RECT 122.400 22.200 123.200 27.600 ;
        RECT 127.600 25.600 128.400 26.400 ;
        RECT 129.400 26.200 130.000 29.600 ;
        RECT 130.800 28.300 131.600 29.200 ;
        RECT 132.400 28.300 133.200 28.400 ;
        RECT 130.800 27.700 133.200 28.300 ;
        RECT 130.800 27.600 131.600 27.700 ;
        RECT 132.400 27.600 133.200 27.700 ;
        RECT 127.800 24.800 128.600 25.600 ;
        RECT 129.200 22.200 130.000 26.200 ;
        RECT 134.000 25.600 134.800 26.400 ;
        RECT 135.800 26.200 136.400 29.800 ;
        RECT 138.800 29.600 139.600 29.800 ;
        RECT 140.400 29.600 141.200 31.200 ;
        RECT 142.000 30.300 142.600 31.800 ;
        RECT 145.200 31.600 146.000 31.800 ;
        RECT 147.200 31.600 149.200 32.400 ;
        RECT 152.200 31.800 154.000 32.600 ;
        RECT 156.400 32.400 157.200 39.800 ;
        RECT 156.400 31.800 158.600 32.400 ;
        RECT 145.200 30.300 146.000 30.400 ;
        RECT 142.000 29.700 146.000 30.300 ;
        RECT 137.200 27.600 138.000 29.200 ;
        RECT 142.000 28.400 142.600 29.700 ;
        RECT 145.200 29.600 146.000 29.700 ;
        RECT 147.200 28.400 147.800 31.600 ;
        RECT 148.400 28.800 149.200 30.400 ;
        RECT 150.000 30.300 150.800 30.400 ;
        RECT 151.600 30.300 152.400 31.200 ;
        RECT 150.000 29.700 152.400 30.300 ;
        RECT 150.000 29.600 150.800 29.700 ;
        RECT 151.600 29.600 152.400 29.700 ;
        RECT 153.200 28.400 153.800 31.800 ;
        RECT 158.000 31.200 158.600 31.800 ;
        RECT 158.000 30.400 159.200 31.200 ;
        RECT 156.400 28.800 157.200 30.400 ;
        RECT 142.000 27.600 142.800 28.400 ;
        RECT 145.200 27.600 147.800 28.400 ;
        RECT 150.000 28.300 150.800 28.400 ;
        RECT 151.600 28.300 152.400 28.400 ;
        RECT 150.000 28.200 152.400 28.300 ;
        RECT 149.200 27.700 152.400 28.200 ;
        RECT 149.200 27.600 150.800 27.700 ;
        RECT 151.600 27.600 152.400 27.700 ;
        RECT 153.200 27.600 154.000 28.400 ;
        RECT 134.200 24.800 135.000 25.600 ;
        RECT 135.600 22.200 136.400 26.200 ;
        RECT 142.000 24.200 142.600 27.600 ;
        RECT 143.600 24.800 144.400 26.400 ;
        RECT 145.400 26.200 146.000 27.600 ;
        RECT 149.200 27.200 150.000 27.600 ;
        RECT 147.000 26.200 150.600 26.600 ;
        RECT 142.000 22.200 142.800 24.200 ;
        RECT 145.200 22.200 146.000 26.200 ;
        RECT 146.800 26.000 150.800 26.200 ;
        RECT 146.800 22.200 147.600 26.000 ;
        RECT 150.000 22.200 150.800 26.000 ;
        RECT 153.200 24.400 153.800 27.600 ;
        RECT 158.000 27.400 158.600 30.400 ;
        RECT 156.400 26.800 158.600 27.400 ;
        RECT 154.800 24.800 155.600 26.400 ;
        RECT 153.200 22.200 154.000 24.400 ;
        RECT 156.400 22.200 157.200 26.800 ;
        RECT 1.200 15.800 2.000 19.800 ;
        RECT 5.400 18.400 6.200 19.800 ;
        RECT 5.400 17.600 6.800 18.400 ;
        RECT 9.200 17.800 10.000 19.800 ;
        RECT 5.400 16.800 6.200 17.600 ;
        RECT 5.400 15.800 6.800 16.800 ;
        RECT 1.400 15.600 2.000 15.800 ;
        RECT 1.400 15.200 3.200 15.600 ;
        RECT 1.400 15.000 5.600 15.200 ;
        RECT 2.600 14.600 5.600 15.000 ;
        RECT 4.800 14.400 5.600 14.600 ;
        RECT 4.800 11.000 5.400 14.400 ;
        RECT 6.200 12.400 6.800 15.800 ;
        RECT 9.400 15.600 10.000 17.800 ;
        RECT 12.400 15.800 13.200 19.800 ;
        RECT 14.200 16.400 15.000 17.200 ;
        RECT 9.400 15.000 11.800 15.600 ;
        RECT 6.000 11.600 6.800 12.400 ;
        RECT 11.200 12.000 11.800 15.000 ;
        RECT 12.600 12.400 13.200 15.800 ;
        RECT 14.000 15.600 14.800 16.400 ;
        RECT 15.600 15.800 16.400 19.800 ;
        RECT 3.000 10.400 5.400 11.000 ;
        RECT 3.000 6.200 3.600 10.400 ;
        RECT 6.200 10.200 6.800 11.600 ;
        RECT 11.000 11.400 11.800 12.000 ;
        RECT 12.400 11.600 13.200 12.400 ;
        RECT 14.000 12.200 14.800 12.400 ;
        RECT 15.800 12.200 16.400 15.800 ;
        RECT 21.600 14.400 22.400 19.800 ;
        RECT 21.600 14.200 22.800 14.400 ;
        RECT 20.600 13.600 22.800 14.200 ;
        RECT 18.800 12.200 19.600 12.400 ;
        RECT 14.000 11.600 16.400 12.200 ;
        RECT 18.000 11.600 19.600 12.200 ;
        RECT 2.800 2.200 3.600 6.200 ;
        RECT 6.000 2.200 6.800 10.200 ;
        RECT 7.600 11.200 11.800 11.400 ;
        RECT 7.600 10.800 11.600 11.200 ;
        RECT 7.600 2.200 8.400 10.800 ;
        RECT 12.600 10.200 13.200 11.600 ;
        RECT 14.200 10.200 14.800 11.600 ;
        RECT 18.000 11.200 18.800 11.600 ;
        RECT 20.600 10.400 21.200 13.600 ;
        RECT 22.800 11.600 24.400 12.400 ;
        RECT 11.800 9.600 13.200 10.200 ;
        RECT 11.800 2.200 12.600 9.600 ;
        RECT 14.000 2.200 14.800 10.200 ;
        RECT 15.600 9.600 19.600 10.200 ;
        RECT 20.400 9.600 21.200 10.400 ;
        RECT 15.600 2.200 16.400 9.600 ;
        RECT 18.800 2.200 19.600 9.600 ;
        RECT 20.600 7.000 21.200 9.600 ;
        RECT 28.400 10.300 29.200 19.800 ;
        RECT 30.000 15.800 30.800 19.800 ;
        RECT 31.600 16.000 32.400 19.800 ;
        RECT 34.800 16.000 35.600 19.800 ;
        RECT 31.600 15.800 35.600 16.000 ;
        RECT 30.200 14.400 30.800 15.800 ;
        RECT 31.800 15.400 35.400 15.800 ;
        RECT 34.000 14.400 34.800 14.800 ;
        RECT 30.000 13.600 32.600 14.400 ;
        RECT 34.000 13.800 35.600 14.400 ;
        RECT 40.000 14.200 40.800 19.800 ;
        RECT 51.200 14.200 52.000 19.800 ;
        RECT 54.000 15.200 54.800 19.800 ;
        RECT 62.000 15.200 62.800 19.800 ;
        RECT 54.000 14.600 56.200 15.200 ;
        RECT 40.000 13.800 41.800 14.200 ;
        RECT 51.200 13.800 53.000 14.200 ;
        RECT 34.800 13.600 35.600 13.800 ;
        RECT 40.200 13.600 41.800 13.800 ;
        RECT 51.400 13.600 53.000 13.800 ;
        RECT 32.000 10.400 32.600 13.600 ;
        RECT 33.200 11.600 34.000 13.200 ;
        RECT 38.000 11.600 39.600 12.400 ;
        RECT 30.000 10.300 30.800 10.400 ;
        RECT 28.400 10.200 30.800 10.300 ;
        RECT 28.400 9.700 31.400 10.200 ;
        RECT 22.000 7.600 22.800 9.200 ;
        RECT 20.600 6.400 24.200 7.000 ;
        RECT 20.600 6.200 21.200 6.400 ;
        RECT 20.400 2.200 21.200 6.200 ;
        RECT 23.600 6.200 24.200 6.400 ;
        RECT 23.600 2.200 24.400 6.200 ;
        RECT 28.400 2.200 29.200 9.700 ;
        RECT 30.000 9.600 31.400 9.700 ;
        RECT 32.000 9.600 34.000 10.400 ;
        RECT 36.400 9.600 37.200 11.200 ;
        RECT 41.200 10.400 41.800 13.600 ;
        RECT 49.200 11.600 50.800 12.400 ;
        RECT 52.400 12.300 53.000 13.600 ;
        RECT 54.000 12.300 54.800 13.200 ;
        RECT 52.400 11.700 54.800 12.300 ;
        RECT 41.200 10.300 42.000 10.400 ;
        RECT 47.600 10.300 48.400 11.200 ;
        RECT 41.200 9.700 48.400 10.300 ;
        RECT 41.200 9.600 42.000 9.700 ;
        RECT 47.600 9.600 48.400 9.700 ;
        RECT 52.400 10.400 53.000 11.700 ;
        RECT 54.000 11.600 54.800 11.700 ;
        RECT 55.600 11.600 56.200 14.600 ;
        RECT 60.600 14.600 62.800 15.200 ;
        RECT 63.600 15.800 64.400 19.800 ;
        RECT 66.800 17.800 67.600 19.800 ;
        RECT 73.200 18.400 74.000 19.800 ;
        RECT 73.200 17.800 74.200 18.400 ;
        RECT 60.600 11.600 61.200 14.600 ;
        RECT 62.000 12.300 62.800 13.200 ;
        RECT 63.600 12.400 64.200 15.800 ;
        RECT 66.800 15.600 67.400 17.800 ;
        RECT 73.600 17.600 74.200 17.800 ;
        RECT 76.400 17.800 77.200 19.800 ;
        RECT 76.400 17.600 77.600 17.800 ;
        RECT 68.400 15.600 69.200 17.200 ;
        RECT 73.600 17.000 77.600 17.600 ;
        RECT 71.600 15.600 73.400 16.400 ;
        RECT 65.000 15.000 67.400 15.600 ;
        RECT 63.600 12.300 64.400 12.400 ;
        RECT 62.000 11.700 64.400 12.300 ;
        RECT 62.000 11.600 62.800 11.700 ;
        RECT 63.600 11.600 64.400 11.700 ;
        RECT 65.000 12.000 65.600 15.000 ;
        RECT 66.600 14.300 67.600 14.400 ;
        RECT 71.700 14.300 72.300 15.600 ;
        RECT 66.600 13.700 72.300 14.300 ;
        RECT 66.600 13.600 67.600 13.700 ;
        RECT 73.200 13.600 74.800 14.400 ;
        RECT 66.400 12.800 67.200 13.600 ;
        RECT 55.600 10.800 56.800 11.600 ;
        RECT 60.000 10.800 61.200 11.600 ;
        RECT 52.400 9.600 53.200 10.400 ;
        RECT 55.600 10.200 56.200 10.800 ;
        RECT 54.000 9.600 56.200 10.200 ;
        RECT 60.600 10.200 61.200 10.800 ;
        RECT 63.600 10.200 64.200 11.600 ;
        RECT 65.000 11.400 65.800 12.000 ;
        RECT 74.800 11.600 76.400 12.400 ;
        RECT 65.000 11.200 69.200 11.400 ;
        RECT 65.200 10.800 69.200 11.200 ;
        RECT 60.600 9.600 62.800 10.200 ;
        RECT 63.600 9.600 65.000 10.200 ;
        RECT 30.800 8.400 31.400 9.600 ;
        RECT 30.800 7.600 31.600 8.400 ;
        RECT 32.200 2.200 33.000 9.600 ;
        RECT 39.600 7.600 40.400 9.200 ;
        RECT 41.200 7.000 41.800 9.600 ;
        RECT 42.800 8.300 43.600 8.400 ;
        RECT 50.800 8.300 51.600 9.200 ;
        RECT 42.800 7.700 51.600 8.300 ;
        RECT 42.800 7.600 43.600 7.700 ;
        RECT 50.800 7.600 51.600 7.700 ;
        RECT 52.400 7.000 53.000 9.600 ;
        RECT 38.200 6.400 41.800 7.000 ;
        RECT 38.200 6.200 38.800 6.400 ;
        RECT 38.000 2.200 38.800 6.200 ;
        RECT 41.200 6.200 41.800 6.400 ;
        RECT 49.400 6.400 53.000 7.000 ;
        RECT 49.400 6.200 50.000 6.400 ;
        RECT 41.200 2.200 42.000 6.200 ;
        RECT 49.200 2.200 50.000 6.200 ;
        RECT 52.400 6.200 53.000 6.400 ;
        RECT 52.400 2.200 53.200 6.200 ;
        RECT 54.000 2.200 54.800 9.600 ;
        RECT 62.000 2.200 62.800 9.600 ;
        RECT 64.200 2.200 65.000 9.600 ;
        RECT 68.400 2.200 69.200 10.800 ;
        RECT 77.000 10.400 77.600 17.000 ;
        RECT 82.800 15.600 83.600 17.200 ;
        RECT 84.400 16.300 85.200 19.800 ;
        RECT 86.200 16.400 87.000 17.200 ;
        RECT 86.000 16.300 86.800 16.400 ;
        RECT 84.400 15.700 86.800 16.300 ;
        RECT 87.600 15.800 88.400 19.800 ;
        RECT 92.400 15.800 93.200 19.800 ;
        RECT 94.000 16.000 94.800 19.800 ;
        RECT 97.200 16.000 98.000 19.800 ;
        RECT 94.000 15.800 98.000 16.000 ;
        RECT 98.800 16.000 99.600 19.800 ;
        RECT 102.000 16.000 102.800 19.800 ;
        RECT 98.800 15.800 102.800 16.000 ;
        RECT 77.000 9.800 80.400 10.400 ;
        RECT 79.600 9.600 80.400 9.800 ;
        RECT 70.200 8.800 73.800 9.400 ;
        RECT 70.200 8.200 70.800 8.800 ;
        RECT 70.000 2.200 70.800 8.200 ;
        RECT 73.200 8.200 73.800 8.800 ;
        RECT 75.000 9.000 78.600 9.200 ;
        RECT 79.600 9.000 80.200 9.600 ;
        RECT 75.000 8.600 78.800 9.000 ;
        RECT 75.000 8.200 75.600 8.600 ;
        RECT 73.200 2.800 74.000 8.200 ;
        RECT 74.800 3.400 75.600 8.200 ;
        RECT 76.400 2.800 77.200 8.000 ;
        RECT 78.000 3.000 78.800 8.600 ;
        RECT 79.600 3.400 80.400 9.000 ;
        RECT 73.200 2.200 77.200 2.800 ;
        RECT 78.200 2.800 78.800 3.000 ;
        RECT 81.200 3.000 82.000 9.000 ;
        RECT 81.200 2.800 81.800 3.000 ;
        RECT 78.200 2.200 81.800 2.800 ;
        RECT 84.400 2.200 85.200 15.700 ;
        RECT 86.000 15.600 86.800 15.700 ;
        RECT 87.800 12.400 88.400 15.800 ;
        RECT 92.600 14.400 93.200 15.800 ;
        RECT 94.200 15.400 97.800 15.800 ;
        RECT 99.000 15.400 102.600 15.800 ;
        RECT 103.600 15.600 104.400 19.800 ;
        RECT 96.400 14.400 97.200 14.800 ;
        RECT 99.600 14.400 100.400 14.800 ;
        RECT 103.600 14.400 104.200 15.600 ;
        RECT 108.400 15.200 109.200 19.800 ;
        RECT 112.600 16.400 113.400 19.800 ;
        RECT 111.600 15.800 113.400 16.400 ;
        RECT 107.000 14.600 109.200 15.200 ;
        RECT 89.200 12.800 90.000 14.400 ;
        RECT 92.400 13.600 95.000 14.400 ;
        RECT 96.400 14.300 98.000 14.400 ;
        RECT 98.800 14.300 100.400 14.400 ;
        RECT 96.400 13.800 100.400 14.300 ;
        RECT 97.200 13.700 99.600 13.800 ;
        RECT 97.200 13.600 98.000 13.700 ;
        RECT 98.800 13.600 99.600 13.700 ;
        RECT 101.800 13.600 104.400 14.400 ;
        RECT 94.400 12.400 95.000 13.600 ;
        RECT 86.000 12.200 86.800 12.400 ;
        RECT 87.600 12.200 88.400 12.400 ;
        RECT 90.800 12.200 91.600 12.400 ;
        RECT 86.000 11.600 88.400 12.200 ;
        RECT 90.000 11.600 91.600 12.200 ;
        RECT 94.000 11.600 95.000 12.400 ;
        RECT 95.600 12.300 96.400 13.200 ;
        RECT 100.400 12.300 101.200 13.200 ;
        RECT 95.600 11.700 101.200 12.300 ;
        RECT 95.600 11.600 96.400 11.700 ;
        RECT 100.400 11.600 101.200 11.700 ;
        RECT 86.200 10.200 86.800 11.600 ;
        RECT 90.000 11.200 90.800 11.600 ;
        RECT 92.400 10.200 93.200 10.400 ;
        RECT 94.400 10.200 95.000 11.600 ;
        RECT 101.800 10.200 102.400 13.600 ;
        RECT 107.000 11.600 107.600 14.600 ;
        RECT 110.000 13.600 110.800 15.200 ;
        RECT 108.400 12.300 109.200 13.200 ;
        RECT 111.600 12.300 112.400 15.800 ;
        RECT 123.200 14.200 124.000 19.800 ;
        RECT 126.000 15.800 126.800 19.800 ;
        RECT 127.600 16.000 128.400 19.800 ;
        RECT 130.800 16.000 131.600 19.800 ;
        RECT 127.600 15.800 131.600 16.000 ;
        RECT 126.200 14.400 126.800 15.800 ;
        RECT 127.800 15.400 131.400 15.800 ;
        RECT 130.000 14.400 130.800 14.800 ;
        RECT 123.200 13.800 125.000 14.200 ;
        RECT 123.400 13.600 125.000 13.800 ;
        RECT 126.000 13.600 128.600 14.400 ;
        RECT 130.000 14.300 131.600 14.400 ;
        RECT 132.400 14.300 133.200 19.800 ;
        RECT 134.000 15.600 134.800 17.200 ;
        RECT 135.600 15.800 136.400 19.800 ;
        RECT 137.200 16.000 138.000 19.800 ;
        RECT 140.400 16.000 141.200 19.800 ;
        RECT 137.200 15.800 141.200 16.000 ;
        RECT 143.600 17.800 144.400 19.800 ;
        RECT 148.400 17.800 149.200 19.800 ;
        RECT 135.800 14.400 136.400 15.800 ;
        RECT 137.400 15.400 141.000 15.800 ;
        RECT 139.600 14.400 140.400 14.800 ;
        RECT 143.600 14.400 144.200 17.800 ;
        RECT 145.200 15.600 146.000 17.200 ;
        RECT 148.400 14.400 149.000 17.800 ;
        RECT 150.000 15.600 150.800 17.200 ;
        RECT 151.600 15.200 152.400 19.800 ;
        RECT 156.400 15.200 157.200 19.800 ;
        RECT 151.600 14.600 153.800 15.200 ;
        RECT 156.400 14.600 158.600 15.200 ;
        RECT 130.000 13.800 133.200 14.300 ;
        RECT 130.800 13.700 133.200 13.800 ;
        RECT 130.800 13.600 131.600 13.700 ;
        RECT 108.400 11.700 112.400 12.300 ;
        RECT 108.400 11.600 109.200 11.700 ;
        RECT 106.400 10.800 107.600 11.600 ;
        RECT 103.600 10.200 104.400 10.400 ;
        RECT 86.000 2.200 86.800 10.200 ;
        RECT 87.600 9.600 91.600 10.200 ;
        RECT 92.400 9.600 93.800 10.200 ;
        RECT 94.400 9.600 95.400 10.200 ;
        RECT 87.600 2.200 88.400 9.600 ;
        RECT 90.800 2.200 91.600 9.600 ;
        RECT 93.200 8.400 93.800 9.600 ;
        RECT 93.200 7.600 94.000 8.400 ;
        RECT 94.600 2.200 95.400 9.600 ;
        RECT 101.400 9.600 102.400 10.200 ;
        RECT 103.000 9.600 104.400 10.200 ;
        RECT 107.000 10.200 107.600 10.800 ;
        RECT 107.000 9.600 109.200 10.200 ;
        RECT 101.400 2.200 102.200 9.600 ;
        RECT 103.000 8.400 103.600 9.600 ;
        RECT 102.800 7.600 103.600 8.400 ;
        RECT 108.400 2.200 109.200 9.600 ;
        RECT 111.600 2.200 112.400 11.700 ;
        RECT 121.200 11.600 122.800 12.400 ;
        RECT 113.200 8.800 114.000 10.400 ;
        RECT 119.600 9.600 120.400 11.200 ;
        RECT 124.400 10.400 125.000 13.600 ;
        RECT 128.000 12.400 128.600 13.600 ;
        RECT 127.600 11.600 128.600 12.400 ;
        RECT 129.200 11.600 130.000 13.200 ;
        RECT 124.400 9.600 125.200 10.400 ;
        RECT 126.000 10.200 126.800 10.400 ;
        RECT 128.000 10.200 128.600 11.600 ;
        RECT 126.000 9.600 127.400 10.200 ;
        RECT 128.000 9.600 129.000 10.200 ;
        RECT 122.800 7.600 123.600 9.200 ;
        RECT 124.400 7.000 125.000 9.600 ;
        RECT 126.800 8.400 127.400 9.600 ;
        RECT 126.800 7.600 127.600 8.400 ;
        RECT 121.400 6.400 125.000 7.000 ;
        RECT 121.400 6.200 122.000 6.400 ;
        RECT 121.200 2.200 122.000 6.200 ;
        RECT 124.400 6.200 125.000 6.400 ;
        RECT 124.400 2.200 125.200 6.200 ;
        RECT 128.200 2.200 129.000 9.600 ;
        RECT 132.400 2.200 133.200 13.700 ;
        RECT 135.600 13.600 138.200 14.400 ;
        RECT 139.600 14.300 141.200 14.400 ;
        RECT 143.600 14.300 144.400 14.400 ;
        RECT 139.600 13.800 144.400 14.300 ;
        RECT 140.400 13.700 144.400 13.800 ;
        RECT 140.400 13.600 141.200 13.700 ;
        RECT 143.600 13.600 144.400 13.700 ;
        RECT 148.400 13.600 149.200 14.400 ;
        RECT 135.600 10.200 136.400 10.400 ;
        RECT 137.600 10.200 138.200 13.600 ;
        RECT 138.800 11.600 139.600 13.200 ;
        RECT 142.000 10.800 142.800 12.400 ;
        RECT 143.600 10.200 144.200 13.600 ;
        RECT 146.800 10.800 147.600 12.400 ;
        RECT 148.400 12.300 149.000 13.600 ;
        RECT 151.600 12.300 152.400 13.200 ;
        RECT 148.400 11.700 152.400 12.300 ;
        RECT 148.400 10.200 149.000 11.700 ;
        RECT 151.600 11.600 152.400 11.700 ;
        RECT 153.200 11.600 153.800 14.600 ;
        RECT 156.400 11.600 157.200 13.200 ;
        RECT 158.000 11.600 158.600 14.600 ;
        RECT 153.200 10.800 154.400 11.600 ;
        RECT 158.000 10.800 159.200 11.600 ;
        RECT 153.200 10.200 153.800 10.800 ;
        RECT 158.000 10.200 158.600 10.800 ;
        RECT 135.600 9.600 137.000 10.200 ;
        RECT 137.600 9.600 138.600 10.200 ;
        RECT 136.400 8.400 137.000 9.600 ;
        RECT 136.400 7.600 137.200 8.400 ;
        RECT 137.800 2.200 138.600 9.600 ;
        RECT 142.600 9.400 144.400 10.200 ;
        RECT 147.400 9.400 149.200 10.200 ;
        RECT 151.600 9.600 153.800 10.200 ;
        RECT 156.400 9.600 158.600 10.200 ;
        RECT 142.600 2.200 143.400 9.400 ;
        RECT 147.400 2.200 148.200 9.400 ;
        RECT 151.600 2.200 152.400 9.600 ;
        RECT 156.400 2.200 157.200 9.600 ;
      LAYER via1 ;
        RECT 7.600 89.600 8.400 90.400 ;
        RECT 10.800 83.600 11.600 84.400 ;
        RECT 17.200 83.600 18.000 84.400 ;
        RECT 23.600 89.600 24.400 90.400 ;
        RECT 34.800 87.600 35.600 88.400 ;
        RECT 30.000 83.600 30.800 84.400 ;
        RECT 39.600 83.600 40.400 84.400 ;
        RECT 52.400 83.600 53.200 84.400 ;
        RECT 98.800 97.600 99.600 98.400 ;
        RECT 95.600 95.600 96.400 96.400 ;
        RECT 73.200 89.600 74.000 90.400 ;
        RECT 55.600 83.600 56.400 84.400 ;
        RECT 62.000 85.600 62.800 86.400 ;
        RECT 68.400 83.600 69.200 84.400 ;
        RECT 78.000 83.600 78.800 84.400 ;
        RECT 100.400 93.600 101.200 94.400 ;
        RECT 95.600 89.600 96.400 90.400 ;
        RECT 102.000 91.600 102.800 92.400 ;
        RECT 113.200 91.600 114.000 92.400 ;
        RECT 106.800 87.600 107.600 88.400 ;
        RECT 110.000 83.600 110.800 84.400 ;
        RECT 129.200 83.600 130.000 84.400 ;
        RECT 137.200 93.600 138.000 94.400 ;
        RECT 132.400 91.600 133.200 92.400 ;
        RECT 146.800 89.600 147.600 90.400 ;
        RECT 158.000 95.600 158.800 96.400 ;
        RECT 153.200 91.600 154.000 92.400 ;
        RECT 151.600 89.600 152.400 90.400 ;
        RECT 150.000 83.600 150.800 84.400 ;
        RECT 158.000 83.600 158.800 84.400 ;
        RECT 9.200 71.600 10.000 72.400 ;
        RECT 12.400 63.600 13.200 64.400 ;
        RECT 39.600 69.600 40.400 70.400 ;
        RECT 52.400 71.600 53.200 72.400 ;
        RECT 42.800 69.600 43.600 70.400 ;
        RECT 50.800 67.600 51.600 68.400 ;
        RECT 57.200 69.600 58.000 70.400 ;
        RECT 60.400 69.600 61.200 70.400 ;
        RECT 20.400 63.600 21.200 64.400 ;
        RECT 30.000 63.600 30.800 64.400 ;
        RECT 39.600 63.600 40.400 64.400 ;
        RECT 60.400 65.600 61.200 66.400 ;
        RECT 82.800 77.600 83.600 78.400 ;
        RECT 76.400 73.600 77.200 74.400 ;
        RECT 81.200 65.600 82.000 66.400 ;
        RECT 65.200 63.600 66.000 64.400 ;
        RECT 97.200 77.600 98.000 78.400 ;
        RECT 95.600 69.600 96.400 70.400 ;
        RECT 98.800 69.600 99.600 70.400 ;
        RECT 103.600 69.600 104.400 70.400 ;
        RECT 111.600 69.600 112.400 70.400 ;
        RECT 124.400 69.600 125.200 70.400 ;
        RECT 86.000 65.600 86.800 66.400 ;
        RECT 84.400 63.600 85.200 64.400 ;
        RECT 110.000 67.600 110.800 68.400 ;
        RECT 113.200 67.600 114.000 68.400 ;
        RECT 119.600 65.600 120.400 66.400 ;
        RECT 153.200 73.600 154.000 74.400 ;
        RECT 126.000 65.600 126.800 66.400 ;
        RECT 137.200 63.600 138.000 64.400 ;
        RECT 151.600 63.600 152.400 64.400 ;
        RECT 159.600 65.600 160.400 66.400 ;
        RECT 158.000 63.600 158.800 64.400 ;
        RECT 17.200 55.600 18.000 56.400 ;
        RECT 4.400 43.600 5.200 44.400 ;
        RECT 23.600 53.600 24.400 54.400 ;
        RECT 25.200 51.600 26.000 52.400 ;
        RECT 34.800 51.600 35.600 52.400 ;
        RECT 20.400 43.600 21.200 44.400 ;
        RECT 30.000 43.600 30.800 44.400 ;
        RECT 73.200 57.600 74.000 58.400 ;
        RECT 66.800 55.600 67.600 56.400 ;
        RECT 50.800 51.600 51.600 52.400 ;
        RECT 41.200 49.600 42.000 50.400 ;
        RECT 71.600 53.600 72.400 54.400 ;
        RECT 39.600 43.600 40.400 44.400 ;
        RECT 50.800 45.600 51.600 46.400 ;
        RECT 65.200 43.600 66.000 44.400 ;
        RECT 76.400 51.600 77.200 52.400 ;
        RECT 79.600 49.600 80.400 50.400 ;
        RECT 87.600 43.600 88.400 44.400 ;
        RECT 89.200 57.600 90.000 58.400 ;
        RECT 92.400 49.600 93.200 50.400 ;
        RECT 89.200 43.600 90.000 44.400 ;
        RECT 94.000 43.600 94.800 44.400 ;
        RECT 103.600 53.600 104.400 54.400 ;
        RECT 119.600 53.600 120.400 54.400 ;
        RECT 114.800 51.600 115.600 52.400 ;
        RECT 121.200 51.600 122.000 52.400 ;
        RECT 143.600 53.600 144.400 54.400 ;
        RECT 134.000 51.600 134.800 52.400 ;
        RECT 159.600 57.600 160.400 58.400 ;
        RECT 127.600 43.600 128.400 44.400 ;
        RECT 138.800 49.600 139.600 50.400 ;
        RECT 151.600 43.600 152.400 44.400 ;
        RECT 2.600 31.800 3.400 32.600 ;
        RECT 2.600 26.200 3.400 27.000 ;
        RECT 14.000 29.600 14.800 30.400 ;
        RECT 17.200 23.600 18.000 24.400 ;
        RECT 36.400 37.600 37.200 38.400 ;
        RECT 31.600 31.600 32.400 32.400 ;
        RECT 31.600 29.600 32.400 30.400 ;
        RECT 33.200 27.600 34.000 28.400 ;
        RECT 38.000 25.600 38.800 26.400 ;
        RECT 52.400 29.600 53.200 30.400 ;
        RECT 42.800 23.600 43.600 24.400 ;
        RECT 63.600 25.600 64.400 26.400 ;
        RECT 58.800 23.600 59.600 24.400 ;
        RECT 68.400 23.600 69.200 24.400 ;
        RECT 86.000 27.600 86.800 28.400 ;
        RECT 76.400 23.600 77.200 24.400 ;
        RECT 90.800 25.600 91.600 26.400 ;
        RECT 89.200 23.600 90.000 24.400 ;
        RECT 105.200 29.600 106.000 30.400 ;
        RECT 122.800 33.600 123.600 34.400 ;
        RECT 100.400 25.600 101.200 26.400 ;
        RECT 126.000 31.600 126.800 32.400 ;
        RECT 124.400 29.600 125.200 30.400 ;
        RECT 113.200 23.600 114.000 24.400 ;
        RECT 148.400 31.600 149.200 32.400 ;
        RECT 148.400 29.600 149.200 30.400 ;
        RECT 156.400 29.600 157.200 30.400 ;
        RECT 135.600 23.600 136.400 24.400 ;
        RECT 143.600 25.600 144.400 26.400 ;
        RECT 154.800 25.600 155.600 26.400 ;
        RECT 153.200 23.600 154.000 24.400 ;
        RECT 6.000 17.600 6.800 18.400 ;
        RECT 15.600 17.600 16.400 18.400 ;
        RECT 28.400 17.600 29.200 18.400 ;
        RECT 22.000 13.600 22.800 14.400 ;
        RECT 18.800 11.600 19.600 12.400 ;
        RECT 23.600 11.600 24.400 12.400 ;
        RECT 33.200 9.600 34.000 10.400 ;
        RECT 66.800 13.600 67.600 14.400 ;
        RECT 79.600 5.600 80.400 6.400 ;
        RECT 89.200 13.600 90.000 14.400 ;
        RECT 87.600 11.600 88.400 12.400 ;
        RECT 90.800 11.600 91.600 12.400 ;
        RECT 132.400 17.600 133.200 18.400 ;
        RECT 103.600 9.600 104.400 10.400 ;
        RECT 113.200 9.600 114.000 10.400 ;
        RECT 137.200 13.600 138.000 14.400 ;
        RECT 142.000 11.600 142.800 12.400 ;
        RECT 146.800 11.600 147.600 12.400 ;
      LAYER metal2 ;
        RECT 98.800 97.600 99.600 98.400 ;
        RECT 113.200 97.600 114.000 98.400 ;
        RECT 71.600 95.600 72.400 96.400 ;
        RECT 95.600 95.600 96.400 96.400 ;
        RECT 97.200 95.600 98.000 96.400 ;
        RECT 100.400 95.600 101.200 96.400 ;
        RECT 7.600 93.600 8.400 94.400 ;
        RECT 20.400 93.600 21.200 94.400 ;
        RECT 23.600 93.600 24.400 94.400 ;
        RECT 7.700 90.400 8.300 93.600 ;
        RECT 7.600 89.600 8.400 90.400 ;
        RECT 20.500 88.400 21.100 93.600 ;
        RECT 23.600 92.300 24.400 92.400 ;
        RECT 26.800 92.300 27.600 92.400 ;
        RECT 23.600 91.700 27.600 92.300 ;
        RECT 23.600 91.600 24.400 91.700 ;
        RECT 26.800 91.600 27.600 91.700 ;
        RECT 49.200 91.600 50.000 92.400 ;
        RECT 23.600 89.600 24.400 90.400 ;
        RECT 23.700 88.400 24.300 89.600 ;
        RECT 49.300 88.400 49.900 91.600 ;
        RECT 71.700 88.400 72.300 95.600 ;
        RECT 82.800 93.600 83.600 94.400 ;
        RECT 78.000 91.600 78.800 92.400 ;
        RECT 73.200 89.600 74.000 90.400 ;
        RECT 74.800 89.600 75.600 90.400 ;
        RECT 74.900 88.400 75.500 89.600 ;
        RECT 78.100 88.400 78.700 91.600 ;
        RECT 95.600 89.600 96.400 90.400 ;
        RECT 95.700 88.400 96.300 89.600 ;
        RECT 4.400 87.600 5.200 88.400 ;
        RECT 20.400 87.600 21.200 88.400 ;
        RECT 23.600 87.600 24.400 88.400 ;
        RECT 34.800 87.600 35.600 88.400 ;
        RECT 38.000 87.600 38.800 88.400 ;
        RECT 41.200 87.600 42.000 88.400 ;
        RECT 49.200 87.600 50.000 88.400 ;
        RECT 62.000 87.600 62.800 88.400 ;
        RECT 66.800 87.600 67.600 88.400 ;
        RECT 71.600 87.600 72.400 88.400 ;
        RECT 74.800 87.600 75.600 88.400 ;
        RECT 78.000 87.600 78.800 88.400 ;
        RECT 82.800 87.600 83.600 88.400 ;
        RECT 95.600 87.600 96.400 88.400 ;
        RECT 41.300 86.400 41.900 87.600 ;
        RECT 62.100 86.400 62.700 87.600 ;
        RECT 66.900 86.400 67.500 87.600 ;
        RECT 82.900 86.400 83.500 87.600 ;
        RECT 41.200 85.600 42.000 86.400 ;
        RECT 62.000 85.600 62.800 86.400 ;
        RECT 66.800 85.600 67.600 86.400 ;
        RECT 82.800 85.600 83.600 86.400 ;
        RECT 10.800 83.600 11.600 84.400 ;
        RECT 17.200 83.600 18.000 84.400 ;
        RECT 30.000 83.600 30.800 84.400 ;
        RECT 39.600 83.600 40.400 84.400 ;
        RECT 52.400 83.600 53.200 84.400 ;
        RECT 55.600 83.600 56.400 84.400 ;
        RECT 68.400 83.600 69.200 84.400 ;
        RECT 78.000 83.600 78.800 84.400 ;
        RECT 10.900 78.400 11.500 83.600 ;
        RECT 10.800 77.600 11.600 78.400 ;
        RECT 17.200 73.600 18.000 74.400 ;
        RECT 26.800 73.600 27.600 74.400 ;
        RECT 26.900 72.400 27.500 73.600 ;
        RECT 9.200 71.600 10.000 72.400 ;
        RECT 18.800 71.600 19.600 72.400 ;
        RECT 26.800 71.600 27.600 72.400 ;
        RECT 30.100 66.300 30.700 83.600 ;
        RECT 36.400 71.600 37.200 72.400 ;
        RECT 39.700 70.400 40.300 83.600 ;
        RECT 50.800 81.600 51.600 82.400 ;
        RECT 50.900 74.300 51.500 81.600 ;
        RECT 52.500 76.400 53.100 83.600 ;
        RECT 55.700 82.400 56.300 83.600 ;
        RECT 55.600 81.600 56.400 82.400 ;
        RECT 68.500 80.400 69.100 83.600 ;
        RECT 73.200 81.600 74.000 82.400 ;
        RECT 68.400 79.600 69.200 80.400 ;
        RECT 58.800 77.600 59.600 78.400 ;
        RECT 52.400 75.600 53.200 76.400 ;
        RECT 49.300 73.700 51.500 74.300 ;
        RECT 39.600 69.600 40.400 70.400 ;
        RECT 42.800 69.600 43.600 70.400 ;
        RECT 42.900 68.400 43.500 69.600 ;
        RECT 49.300 68.400 49.900 73.700 ;
        RECT 54.000 73.600 54.800 74.400 ;
        RECT 54.100 72.400 54.700 73.600 ;
        RECT 50.800 71.600 51.600 72.400 ;
        RECT 52.400 71.600 53.200 72.400 ;
        RECT 54.000 71.600 54.800 72.400 ;
        RECT 50.900 68.400 51.500 71.600 ;
        RECT 55.600 69.600 56.400 70.400 ;
        RECT 57.200 69.600 58.000 70.400 ;
        RECT 55.700 68.400 56.300 69.600 ;
        RECT 36.400 67.600 37.200 68.400 ;
        RECT 38.000 67.600 38.800 68.400 ;
        RECT 42.800 67.600 43.600 68.400 ;
        RECT 49.200 67.600 50.000 68.400 ;
        RECT 50.800 67.600 51.600 68.400 ;
        RECT 55.600 67.600 56.400 68.400 ;
        RECT 30.100 65.700 32.300 66.300 ;
        RECT 1.200 63.600 2.000 64.400 ;
        RECT 12.400 63.600 13.200 64.400 ;
        RECT 20.400 63.600 21.200 64.400 ;
        RECT 25.200 63.600 26.000 64.400 ;
        RECT 30.000 63.600 30.800 64.400 ;
        RECT 1.300 50.400 1.900 63.600 ;
        RECT 12.500 58.400 13.100 63.600 ;
        RECT 20.500 62.400 21.100 63.600 ;
        RECT 20.400 61.600 21.200 62.400 ;
        RECT 23.600 61.600 24.400 62.400 ;
        RECT 6.000 57.600 6.800 58.400 ;
        RECT 12.400 57.600 13.200 58.400 ;
        RECT 20.400 57.600 21.200 58.400 ;
        RECT 6.100 54.400 6.700 57.600 ;
        RECT 20.500 56.400 21.100 57.600 ;
        RECT 17.200 55.600 18.000 56.400 ;
        RECT 20.400 55.600 21.200 56.400 ;
        RECT 23.700 54.400 24.300 61.600 ;
        RECT 6.000 53.600 6.800 54.400 ;
        RECT 23.600 53.600 24.400 54.400 ;
        RECT 25.300 52.400 25.900 63.600 ;
        RECT 28.400 57.600 29.200 58.400 ;
        RECT 25.200 51.600 26.000 52.400 ;
        RECT 25.300 50.400 25.900 51.600 ;
        RECT 1.200 49.600 2.000 50.400 ;
        RECT 25.200 49.600 26.000 50.400 ;
        RECT 4.400 43.600 5.200 44.400 ;
        RECT 20.400 43.600 21.200 44.400 ;
        RECT 30.000 43.600 30.800 44.400 ;
        RECT 4.500 42.400 5.100 43.600 ;
        RECT 4.400 41.600 5.200 42.400 ;
        RECT 20.500 36.400 21.100 43.600 ;
        RECT 20.400 35.600 21.200 36.400 ;
        RECT 23.600 33.600 24.400 34.400 ;
        RECT 2.600 31.800 3.400 32.600 ;
        RECT 9.200 31.800 10.000 32.600 ;
        RECT 2.600 27.000 3.200 31.800 ;
        RECT 5.200 28.400 6.000 28.600 ;
        RECT 9.400 28.400 10.000 31.800 ;
        RECT 14.000 30.300 14.800 30.400 ;
        RECT 30.100 30.300 30.700 43.600 ;
        RECT 31.700 38.400 32.300 65.700 ;
        RECT 33.200 61.600 34.000 62.400 ;
        RECT 33.300 48.400 33.900 61.600 ;
        RECT 38.100 60.400 38.700 67.600 ;
        RECT 57.300 64.400 57.900 69.600 ;
        RECT 58.900 64.400 59.500 77.600 ;
        RECT 60.400 75.600 61.200 76.400 ;
        RECT 60.500 70.400 61.100 75.600 ;
        RECT 68.400 73.600 69.200 74.400 ;
        RECT 68.500 70.400 69.100 73.600 ;
        RECT 73.300 72.400 73.900 81.600 ;
        RECT 76.400 79.600 77.200 80.400 ;
        RECT 76.500 74.400 77.100 79.600 ;
        RECT 76.400 73.600 77.200 74.400 ;
        RECT 73.200 71.600 74.000 72.400 ;
        RECT 76.400 71.600 77.200 72.400 ;
        RECT 76.500 70.400 77.100 71.600 ;
        RECT 60.400 69.600 61.200 70.400 ;
        RECT 68.400 69.600 69.200 70.400 ;
        RECT 76.400 69.600 77.200 70.400 ;
        RECT 62.000 67.600 62.800 68.400 ;
        RECT 66.800 67.600 67.600 68.400 ;
        RECT 60.400 65.600 61.200 66.400 ;
        RECT 63.600 65.600 64.400 66.400 ;
        RECT 39.600 63.600 40.400 64.400 ;
        RECT 57.200 63.600 58.000 64.400 ;
        RECT 58.800 63.600 59.600 64.400 ;
        RECT 65.200 63.600 66.000 64.400 ;
        RECT 38.000 59.600 38.800 60.400 ;
        RECT 34.800 57.600 35.600 58.400 ;
        RECT 38.000 55.600 38.800 56.400 ;
        RECT 38.100 54.400 38.700 55.600 ;
        RECT 38.000 53.600 38.800 54.400 ;
        RECT 34.800 51.600 35.600 52.400 ;
        RECT 34.900 50.400 35.500 51.600 ;
        RECT 38.100 50.400 38.700 53.600 ;
        RECT 34.800 49.600 35.600 50.400 ;
        RECT 38.000 49.600 38.800 50.400 ;
        RECT 33.200 47.600 34.000 48.400 ;
        RECT 36.400 47.600 37.200 48.400 ;
        RECT 36.500 38.400 37.100 47.600 ;
        RECT 39.700 46.300 40.300 63.600 ;
        RECT 58.900 58.400 59.500 63.600 ;
        RECT 50.800 57.600 51.600 58.400 ;
        RECT 52.400 57.600 53.200 58.400 ;
        RECT 58.800 57.600 59.600 58.400 ;
        RECT 62.000 57.600 62.800 58.400 ;
        RECT 49.200 55.600 50.000 56.400 ;
        RECT 41.200 49.600 42.000 50.400 ;
        RECT 49.300 48.400 49.900 55.600 ;
        RECT 50.900 52.400 51.500 57.600 ;
        RECT 50.800 51.600 51.600 52.400 ;
        RECT 52.500 50.400 53.100 57.600 ;
        RECT 57.200 55.600 58.000 56.400 ;
        RECT 57.300 52.400 57.900 55.600 ;
        RECT 58.900 54.400 59.500 57.600 ;
        RECT 58.800 53.600 59.600 54.400 ;
        RECT 62.100 52.400 62.700 57.600 ;
        RECT 55.600 51.600 56.400 52.400 ;
        RECT 57.200 51.600 58.000 52.400 ;
        RECT 62.000 51.600 62.800 52.400 ;
        RECT 50.800 49.600 51.600 50.400 ;
        RECT 52.400 49.600 53.200 50.400 ;
        RECT 54.000 49.600 54.800 50.400 ;
        RECT 49.200 47.600 50.000 48.400 ;
        RECT 50.900 46.400 51.500 49.600 ;
        RECT 54.100 48.400 54.700 49.600 ;
        RECT 54.000 47.600 54.800 48.400 ;
        RECT 38.100 45.700 40.300 46.300 ;
        RECT 31.600 37.600 32.400 38.400 ;
        RECT 36.400 37.600 37.200 38.400 ;
        RECT 31.600 31.600 32.400 32.400 ;
        RECT 31.600 30.300 32.400 30.400 ;
        RECT 14.000 29.700 16.300 30.300 ;
        RECT 30.100 29.700 32.400 30.300 ;
        RECT 14.000 29.600 14.800 29.700 ;
        RECT 5.200 27.800 10.000 28.400 ;
        RECT 9.400 27.000 10.000 27.800 ;
        RECT 2.600 26.200 3.400 27.000 ;
        RECT 9.200 26.200 10.000 27.000 ;
        RECT 15.700 18.400 16.300 29.700 ;
        RECT 31.600 29.600 32.400 29.700 ;
        RECT 34.800 29.600 35.600 30.400 ;
        RECT 31.700 26.400 32.300 29.600 ;
        RECT 38.100 28.400 38.700 45.700 ;
        RECT 41.200 45.600 42.000 46.400 ;
        RECT 50.800 45.600 51.600 46.400 ;
        RECT 39.600 43.600 40.400 44.400 ;
        RECT 39.600 29.600 40.400 30.400 ;
        RECT 33.200 27.600 34.000 28.400 ;
        RECT 38.000 27.600 38.800 28.400 ;
        RECT 31.600 25.600 32.400 26.400 ;
        RECT 17.200 23.600 18.000 24.400 ;
        RECT 25.200 23.600 26.000 24.400 ;
        RECT 6.000 17.600 6.800 18.400 ;
        RECT 14.000 17.600 14.800 18.400 ;
        RECT 15.600 17.600 16.400 18.400 ;
        RECT 14.100 16.400 14.700 17.600 ;
        RECT 14.000 15.600 14.800 16.400 ;
        RECT 22.000 13.600 22.800 14.400 ;
        RECT 22.100 12.400 22.700 13.600 ;
        RECT 12.400 11.600 13.200 12.400 ;
        RECT 18.800 11.600 19.600 12.400 ;
        RECT 22.000 11.600 22.800 12.400 ;
        RECT 23.600 12.300 24.400 12.400 ;
        RECT 25.300 12.300 25.900 23.600 ;
        RECT 33.300 22.400 33.900 27.600 ;
        RECT 34.800 25.600 35.600 26.400 ;
        RECT 38.000 25.600 38.800 26.400 ;
        RECT 28.400 21.600 29.200 22.400 ;
        RECT 33.200 21.600 34.000 22.400 ;
        RECT 28.500 18.400 29.100 21.600 ;
        RECT 28.400 17.600 29.200 18.400 ;
        RECT 33.200 17.600 34.000 18.400 ;
        RECT 33.300 12.400 33.900 17.600 ;
        RECT 34.900 14.400 35.500 25.600 ;
        RECT 39.700 18.400 40.300 29.600 ;
        RECT 41.300 28.400 41.900 45.600 ;
        RECT 52.400 43.600 53.200 44.400 ;
        RECT 50.800 31.600 51.600 32.400 ;
        RECT 50.900 28.400 51.500 31.600 ;
        RECT 52.500 30.400 53.100 43.600 ;
        RECT 55.700 40.300 56.300 51.600 ;
        RECT 60.400 49.600 61.200 50.400 ;
        RECT 63.600 48.300 64.400 48.400 ;
        RECT 65.300 48.300 65.900 63.600 ;
        RECT 66.900 62.400 67.500 67.600 ;
        RECT 71.600 65.600 72.400 66.400 ;
        RECT 71.700 64.400 72.300 65.600 ;
        RECT 71.600 63.600 72.400 64.400 ;
        RECT 74.800 63.600 75.600 64.400 ;
        RECT 66.800 61.600 67.600 62.400 ;
        RECT 71.700 56.400 72.300 63.600 ;
        RECT 73.200 57.600 74.000 58.400 ;
        RECT 66.800 55.600 67.600 56.400 ;
        RECT 68.400 55.600 69.200 56.400 ;
        RECT 71.600 55.600 72.400 56.400 ;
        RECT 74.900 54.400 75.500 63.600 ;
        RECT 78.100 58.300 78.700 83.600 ;
        RECT 82.900 78.400 83.500 85.600 ;
        RECT 86.000 83.600 86.800 84.400 ;
        RECT 82.800 77.600 83.600 78.400 ;
        RECT 86.100 72.400 86.700 83.600 ;
        RECT 97.300 78.400 97.900 95.600 ;
        RECT 100.500 94.400 101.100 95.600 ;
        RECT 100.400 93.600 101.200 94.400 ;
        RECT 113.300 92.400 113.900 97.600 ;
        RECT 130.800 95.600 131.600 96.400 ;
        RECT 137.200 95.600 138.000 96.400 ;
        RECT 140.400 95.600 141.200 96.400 ;
        RECT 158.000 95.600 158.800 96.400 ;
        RECT 130.900 94.400 131.500 95.600 ;
        RECT 137.300 94.400 137.900 95.600 ;
        RECT 130.800 93.600 131.600 94.400 ;
        RECT 135.600 93.600 136.400 94.400 ;
        RECT 137.200 93.600 138.000 94.400 ;
        RECT 143.600 93.600 144.400 94.400 ;
        RECT 148.400 93.600 149.200 94.400 ;
        RECT 151.600 93.600 152.400 94.400 ;
        RECT 135.700 92.400 136.300 93.600 ;
        RECT 143.700 92.400 144.300 93.600 ;
        RECT 102.000 91.600 102.800 92.400 ;
        RECT 113.200 91.600 114.000 92.400 ;
        RECT 124.400 91.600 125.200 92.400 ;
        RECT 132.400 91.600 133.200 92.400 ;
        RECT 135.600 91.600 136.400 92.400 ;
        RECT 143.600 91.600 144.400 92.400 ;
        RECT 102.100 90.400 102.700 91.600 ;
        RECT 102.000 89.600 102.800 90.400 ;
        RECT 103.600 89.600 104.400 90.400 ;
        RECT 121.200 89.600 122.000 90.400 ;
        RECT 103.700 78.400 104.300 89.600 ;
        RECT 106.800 88.300 107.600 88.400 ;
        RECT 111.600 88.300 112.400 88.400 ;
        RECT 106.800 87.700 112.400 88.300 ;
        RECT 106.800 87.600 107.600 87.700 ;
        RECT 111.600 87.600 112.400 87.700 ;
        RECT 110.000 83.600 110.800 84.400 ;
        RECT 92.400 77.600 93.200 78.400 ;
        RECT 97.200 77.600 98.000 78.400 ;
        RECT 103.600 77.600 104.400 78.400 ;
        RECT 81.200 71.600 82.000 72.400 ;
        RECT 86.000 71.600 86.800 72.400 ;
        RECT 81.300 66.400 81.900 71.600 ;
        RECT 86.100 66.400 86.700 71.600 ;
        RECT 81.200 65.600 82.000 66.400 ;
        RECT 86.000 65.600 86.800 66.400 ;
        RECT 81.300 58.400 81.900 65.600 ;
        RECT 84.400 63.600 85.200 64.400 ;
        RECT 86.000 63.600 86.800 64.400 ;
        RECT 89.200 63.600 90.000 64.400 ;
        RECT 84.500 62.400 85.100 63.600 ;
        RECT 84.400 61.600 85.200 62.400 ;
        RECT 84.500 58.400 85.100 61.600 ;
        RECT 76.500 57.700 78.700 58.300 ;
        RECT 71.600 53.600 72.400 54.400 ;
        RECT 74.800 53.600 75.600 54.400 ;
        RECT 63.600 47.700 65.900 48.300 ;
        RECT 63.600 47.600 64.400 47.700 ;
        RECT 65.200 43.600 66.000 44.400 ;
        RECT 54.100 39.700 56.300 40.300 ;
        RECT 52.400 29.600 53.200 30.400 ;
        RECT 41.200 27.600 42.000 28.400 ;
        RECT 44.400 27.600 45.200 28.400 ;
        RECT 50.800 27.600 51.600 28.400 ;
        RECT 44.500 26.400 45.100 27.600 ;
        RECT 44.400 25.600 45.200 26.400 ;
        RECT 42.800 23.600 43.600 24.400 ;
        RECT 39.600 17.600 40.400 18.400 ;
        RECT 34.800 13.600 35.600 14.400 ;
        RECT 23.600 11.700 25.900 12.300 ;
        RECT 23.600 11.600 24.400 11.700 ;
        RECT 33.200 11.600 34.000 12.400 ;
        RECT 38.000 11.600 38.800 12.400 ;
        RECT 18.900 8.400 19.500 11.600 ;
        RECT 33.200 9.600 34.000 10.400 ;
        RECT 36.400 9.600 37.200 10.400 ;
        RECT 42.900 8.400 43.500 23.600 ;
        RECT 54.100 14.400 54.700 39.700 ;
        RECT 55.600 37.600 56.400 38.400 ;
        RECT 55.700 32.400 56.300 37.600 ;
        RECT 63.600 33.600 64.400 34.400 ;
        RECT 55.600 31.600 56.400 32.400 ;
        RECT 60.400 31.600 61.200 32.400 ;
        RECT 49.200 13.600 50.000 14.400 ;
        RECT 54.000 13.600 54.800 14.400 ;
        RECT 49.300 12.400 49.900 13.600 ;
        RECT 49.200 11.600 50.000 12.400 ;
        RECT 54.000 11.600 54.800 12.400 ;
        RECT 55.700 8.400 56.300 31.600 ;
        RECT 60.500 28.400 61.100 31.600 ;
        RECT 62.000 29.600 62.800 30.400 ;
        RECT 60.400 27.600 61.200 28.400 ;
        RECT 63.700 26.400 64.300 33.600 ;
        RECT 63.600 25.600 64.400 26.400 ;
        RECT 58.800 23.600 59.600 24.400 ;
        RECT 58.900 14.400 59.500 23.600 ;
        RECT 65.300 16.400 65.900 43.600 ;
        RECT 70.000 31.600 70.800 32.400 ;
        RECT 70.100 28.400 70.700 31.600 ;
        RECT 71.700 30.400 72.300 53.600 ;
        RECT 76.500 52.400 77.100 57.700 ;
        RECT 81.200 57.600 82.000 58.400 ;
        RECT 84.400 57.600 85.200 58.400 ;
        RECT 86.100 56.400 86.700 63.600 ;
        RECT 89.300 58.400 89.900 63.600 ;
        RECT 89.200 57.600 90.000 58.400 ;
        RECT 78.000 55.600 78.800 56.400 ;
        RECT 82.800 55.600 83.600 56.400 ;
        RECT 86.000 55.600 86.800 56.400 ;
        RECT 90.800 55.600 91.600 56.400 ;
        RECT 76.400 51.600 77.200 52.400 ;
        RECT 79.600 49.600 80.400 50.400 ;
        RECT 79.700 46.400 80.300 49.600 ;
        RECT 79.600 45.600 80.400 46.400 ;
        RECT 78.000 37.600 78.800 38.400 ;
        RECT 71.600 29.600 72.400 30.400 ;
        RECT 73.200 29.600 74.000 30.400 ;
        RECT 70.000 27.600 70.800 28.400 ;
        RECT 73.300 24.400 73.900 29.600 ;
        RECT 74.800 27.600 75.600 28.400 ;
        RECT 78.100 26.400 78.700 37.600 ;
        RECT 82.900 30.400 83.500 55.600 ;
        RECT 92.500 50.400 93.100 77.600 ;
        RECT 98.800 75.600 99.600 76.400 ;
        RECT 94.000 73.600 94.800 74.400 ;
        RECT 94.100 70.400 94.700 73.600 ;
        RECT 95.600 71.600 96.400 72.400 ;
        RECT 95.700 70.400 96.300 71.600 ;
        RECT 98.900 70.400 99.500 75.600 ;
        RECT 106.800 71.600 107.600 72.400 ;
        RECT 106.900 70.400 107.500 71.600 ;
        RECT 110.100 70.400 110.700 83.600 ;
        RECT 119.600 79.600 120.400 80.400 ;
        RECT 94.000 69.600 94.800 70.400 ;
        RECT 95.600 69.600 96.400 70.400 ;
        RECT 98.800 69.600 99.600 70.400 ;
        RECT 103.600 69.600 104.400 70.400 ;
        RECT 106.800 69.600 107.600 70.400 ;
        RECT 110.000 69.600 110.800 70.400 ;
        RECT 111.600 69.600 112.400 70.400 ;
        RECT 100.400 67.600 101.200 68.400 ;
        RECT 102.000 67.600 102.800 68.400 ;
        RECT 100.500 56.400 101.100 67.600 ;
        RECT 102.100 64.400 102.700 67.600 ;
        RECT 103.700 66.400 104.300 69.600 ;
        RECT 110.000 67.600 110.800 68.400 ;
        RECT 103.600 65.600 104.400 66.400 ;
        RECT 110.000 65.600 110.800 66.400 ;
        RECT 102.000 63.600 102.800 64.400 ;
        RECT 100.400 55.600 101.200 56.400 ;
        RECT 95.600 53.600 96.400 54.400 ;
        RECT 100.500 52.400 101.100 55.600 ;
        RECT 110.100 54.400 110.700 65.600 ;
        RECT 111.700 64.400 112.300 69.600 ;
        RECT 113.200 67.600 114.000 68.400 ;
        RECT 113.300 66.400 113.900 67.600 ;
        RECT 119.700 66.400 120.300 79.600 ;
        RECT 121.300 78.400 121.900 89.600 ;
        RECT 124.500 86.400 125.100 91.600 ;
        RECT 132.500 88.400 133.100 91.600 ;
        RECT 146.800 90.300 147.600 90.400 ;
        RECT 148.500 90.300 149.100 93.600 ;
        RECT 151.700 90.400 152.300 93.600 ;
        RECT 153.200 91.600 154.000 92.400 ;
        RECT 146.800 89.700 149.100 90.300 ;
        RECT 146.800 89.600 147.600 89.700 ;
        RECT 151.600 89.600 152.400 90.400 ;
        RECT 132.400 87.600 133.200 88.400 ;
        RECT 124.400 85.600 125.200 86.400 ;
        RECT 129.200 83.600 130.000 84.400 ;
        RECT 143.600 83.600 144.400 84.400 ;
        RECT 150.000 83.600 150.800 84.400 ;
        RECT 158.000 83.600 158.800 84.400 ;
        RECT 129.300 78.400 129.900 83.600 ;
        RECT 132.400 79.600 133.200 80.400 ;
        RECT 121.200 77.600 122.000 78.400 ;
        RECT 129.200 77.600 130.000 78.400 ;
        RECT 126.000 73.600 126.800 74.400 ;
        RECT 124.400 69.600 125.200 70.400 ;
        RECT 126.100 68.400 126.700 73.600 ;
        RECT 127.600 71.600 128.400 72.400 ;
        RECT 127.700 70.400 128.300 71.600 ;
        RECT 127.600 69.600 128.400 70.400 ;
        RECT 126.000 67.600 126.800 68.400 ;
        RECT 126.100 66.400 126.700 67.600 ;
        RECT 113.200 65.600 114.000 66.400 ;
        RECT 119.600 65.600 120.400 66.400 ;
        RECT 126.000 65.600 126.800 66.400 ;
        RECT 111.600 63.600 112.400 64.400 ;
        RECT 121.200 57.600 122.000 58.400 ;
        RECT 124.400 57.600 125.200 58.400 ;
        RECT 103.600 53.600 104.400 54.400 ;
        RECT 110.000 53.600 110.800 54.400 ;
        RECT 116.400 53.600 117.200 54.400 ;
        RECT 119.600 53.600 120.400 54.400 ;
        RECT 100.400 51.600 101.200 52.400 ;
        RECT 114.800 51.600 115.600 52.400 ;
        RECT 114.900 50.400 115.500 51.600 ;
        RECT 92.400 49.600 93.200 50.400 ;
        RECT 114.800 49.600 115.600 50.400 ;
        RECT 116.500 48.400 117.100 53.600 ;
        RECT 121.300 52.400 121.900 57.600 ;
        RECT 124.500 52.400 125.100 57.600 ;
        RECT 127.700 54.400 128.300 69.600 ;
        RECT 132.500 66.400 133.100 79.600 ;
        RECT 140.400 73.600 141.200 74.400 ;
        RECT 140.500 70.400 141.100 73.600 ;
        RECT 142.000 71.600 142.800 72.400 ;
        RECT 142.100 70.400 142.700 71.600 ;
        RECT 134.000 69.600 134.800 70.400 ;
        RECT 140.400 69.600 141.200 70.400 ;
        RECT 142.000 69.600 142.800 70.400 ;
        RECT 134.100 68.400 134.700 69.600 ;
        RECT 134.000 67.600 134.800 68.400 ;
        RECT 138.800 67.600 139.600 68.400 ;
        RECT 140.400 67.600 141.200 68.400 ;
        RECT 138.900 66.400 139.500 67.600 ;
        RECT 132.400 65.600 133.200 66.400 ;
        RECT 138.800 65.600 139.600 66.400 ;
        RECT 137.200 63.600 138.000 64.400 ;
        RECT 129.200 55.600 130.000 56.400 ;
        RECT 130.800 55.600 131.600 56.400 ;
        RECT 127.600 53.600 128.400 54.400 ;
        RECT 118.000 51.600 118.800 52.400 ;
        RECT 121.200 51.600 122.000 52.400 ;
        RECT 124.400 51.600 125.200 52.400 ;
        RECT 118.100 50.400 118.700 51.600 ;
        RECT 118.000 49.600 118.800 50.400 ;
        RECT 122.800 49.600 123.600 50.400 ;
        RECT 126.000 49.600 126.800 50.400 ;
        RECT 126.100 48.400 126.700 49.600 ;
        RECT 108.400 47.600 109.200 48.400 ;
        RECT 116.400 47.600 117.200 48.400 ;
        RECT 126.000 47.600 126.800 48.400 ;
        RECT 102.000 45.600 102.800 46.400 ;
        RECT 87.600 43.600 88.400 44.400 ;
        RECT 89.200 43.600 90.000 44.400 ;
        RECT 94.000 43.600 94.800 44.400 ;
        RECT 87.700 34.400 88.300 43.600 ;
        RECT 89.300 38.400 89.900 43.600 ;
        RECT 89.200 37.600 90.000 38.400 ;
        RECT 90.800 35.600 91.600 36.400 ;
        RECT 87.600 33.600 88.400 34.400 ;
        RECT 84.400 31.600 85.200 32.400 ;
        RECT 89.200 31.600 90.000 32.400 ;
        RECT 79.600 29.600 80.400 30.400 ;
        RECT 82.800 29.600 83.600 30.400 ;
        RECT 79.700 28.400 80.300 29.600 ;
        RECT 82.900 28.400 83.500 29.600 ;
        RECT 84.500 28.400 85.100 31.600 ;
        RECT 79.600 27.600 80.400 28.400 ;
        RECT 82.800 27.600 83.600 28.400 ;
        RECT 84.400 27.600 85.200 28.400 ;
        RECT 86.000 27.600 86.800 28.400 ;
        RECT 78.000 25.600 78.800 26.400 ;
        RECT 68.400 23.600 69.200 24.400 ;
        RECT 73.200 23.600 74.000 24.400 ;
        RECT 76.400 23.600 77.200 24.400 ;
        RECT 68.500 18.400 69.100 23.600 ;
        RECT 68.400 17.600 69.200 18.400 ;
        RECT 76.500 16.400 77.100 23.600 ;
        RECT 65.200 15.600 66.000 16.400 ;
        RECT 68.400 15.600 69.200 16.400 ;
        RECT 74.800 15.600 75.600 16.400 ;
        RECT 76.400 15.600 77.200 16.400 ;
        RECT 82.800 15.600 83.600 16.400 ;
        RECT 58.800 13.600 59.600 14.400 ;
        RECT 66.800 13.600 67.600 14.400 ;
        RECT 73.200 13.600 74.000 14.400 ;
        RECT 73.300 12.400 73.900 13.600 ;
        RECT 74.900 12.400 75.500 15.600 ;
        RECT 73.200 11.600 74.000 12.400 ;
        RECT 74.800 11.600 75.600 12.400 ;
        RECT 82.900 8.400 83.500 15.600 ;
        RECT 86.100 10.400 86.700 27.600 ;
        RECT 90.900 26.400 91.500 35.600 ;
        RECT 94.100 32.400 94.700 43.600 ;
        RECT 97.200 35.600 98.000 36.400 ;
        RECT 97.300 32.400 97.900 35.600 ;
        RECT 102.100 34.400 102.700 45.600 ;
        RECT 105.200 35.600 106.000 36.400 ;
        RECT 102.000 33.600 102.800 34.400 ;
        RECT 94.000 31.600 94.800 32.400 ;
        RECT 97.200 31.600 98.000 32.400 ;
        RECT 97.300 30.400 97.900 31.600 ;
        RECT 92.400 29.600 93.200 30.400 ;
        RECT 97.200 29.600 98.000 30.400 ;
        RECT 98.800 29.600 99.600 30.400 ;
        RECT 92.500 28.400 93.100 29.600 ;
        RECT 98.900 28.400 99.500 29.600 ;
        RECT 92.400 27.600 93.200 28.400 ;
        RECT 97.200 27.600 98.000 28.400 ;
        RECT 98.800 27.600 99.600 28.400 ;
        RECT 102.100 26.400 102.700 33.600 ;
        RECT 108.500 32.400 109.100 47.600 ;
        RECT 129.300 46.400 129.900 55.600 ;
        RECT 134.000 53.600 134.800 54.400 ;
        RECT 134.100 52.400 134.700 53.600 ;
        RECT 134.000 51.600 134.800 52.400 ;
        RECT 137.300 50.400 137.900 63.600 ;
        RECT 143.700 58.400 144.300 83.600 ;
        RECT 146.800 79.600 147.600 80.400 ;
        RECT 146.900 68.400 147.500 79.600 ;
        RECT 150.100 72.300 150.700 83.600 ;
        RECT 153.200 73.600 154.000 74.400 ;
        RECT 151.600 72.300 152.400 72.400 ;
        RECT 150.100 71.700 152.400 72.300 ;
        RECT 151.600 71.600 152.400 71.700 ;
        RECT 156.400 71.600 157.200 72.400 ;
        RECT 156.500 70.400 157.100 71.600 ;
        RECT 156.400 70.300 157.200 70.400 ;
        RECT 158.100 70.300 158.700 83.600 ;
        RECT 156.400 69.700 158.700 70.300 ;
        RECT 156.400 69.600 157.200 69.700 ;
        RECT 146.800 67.600 147.600 68.400 ;
        RECT 156.400 65.600 157.200 66.400 ;
        RECT 159.600 65.600 160.400 66.400 ;
        RECT 151.600 63.600 152.400 64.400 ;
        RECT 143.600 57.600 144.400 58.400 ;
        RECT 150.000 57.600 150.800 58.400 ;
        RECT 143.600 55.600 144.400 56.400 ;
        RECT 146.800 55.600 147.600 56.400 ;
        RECT 143.700 54.400 144.300 55.600 ;
        RECT 140.400 53.600 141.200 54.400 ;
        RECT 143.600 53.600 144.400 54.400 ;
        RECT 140.400 51.600 141.200 52.400 ;
        RECT 145.200 51.600 146.000 52.400 ;
        RECT 135.600 49.600 136.400 50.400 ;
        RECT 137.200 49.600 138.000 50.400 ;
        RECT 138.800 50.300 139.600 50.400 ;
        RECT 140.500 50.300 141.100 51.600 ;
        RECT 138.800 49.700 141.100 50.300 ;
        RECT 138.800 49.600 139.600 49.700 ;
        RECT 129.200 45.600 130.000 46.400 ;
        RECT 127.600 43.600 128.400 44.400 ;
        RECT 114.800 33.600 115.600 34.400 ;
        RECT 122.800 33.600 123.600 34.400 ;
        RECT 105.200 31.600 106.000 32.400 ;
        RECT 108.400 31.600 109.200 32.400 ;
        RECT 105.300 30.400 105.900 31.600 ;
        RECT 108.500 30.400 109.100 31.600 ;
        RECT 103.600 29.600 104.400 30.400 ;
        RECT 105.200 29.600 106.000 30.400 ;
        RECT 108.400 29.600 109.200 30.400 ;
        RECT 110.000 29.600 110.800 30.400 ;
        RECT 103.700 28.400 104.300 29.600 ;
        RECT 103.600 27.600 104.400 28.400 ;
        RECT 110.100 26.400 110.700 29.600 ;
        RECT 111.600 27.600 112.400 28.400 ;
        RECT 114.900 26.400 115.500 33.600 ;
        RECT 122.900 28.400 123.500 33.600 ;
        RECT 127.700 32.400 128.300 43.600 ;
        RECT 135.700 36.400 136.300 49.600 ;
        RECT 132.400 35.600 133.200 36.400 ;
        RECT 135.600 35.600 136.400 36.400 ;
        RECT 126.000 31.600 126.800 32.400 ;
        RECT 127.600 31.600 128.400 32.400 ;
        RECT 124.400 29.600 125.200 30.400 ;
        RECT 122.800 27.600 123.600 28.400 ;
        RECT 124.400 27.600 125.200 28.400 ;
        RECT 90.800 25.600 91.600 26.400 ;
        RECT 100.400 25.600 101.200 26.400 ;
        RECT 102.000 25.600 102.800 26.400 ;
        RECT 110.000 25.600 110.800 26.400 ;
        RECT 114.800 25.600 115.600 26.400 ;
        RECT 89.200 23.600 90.000 24.400 ;
        RECT 113.200 23.600 114.000 24.400 ;
        RECT 121.200 23.600 122.000 24.400 ;
        RECT 89.300 14.400 89.900 23.600 ;
        RECT 90.800 17.600 91.600 18.400 ;
        RECT 95.600 17.600 96.400 18.400 ;
        RECT 89.200 13.600 90.000 14.400 ;
        RECT 90.900 12.400 91.500 17.600 ;
        RECT 95.700 12.400 96.300 17.600 ;
        RECT 103.600 15.600 104.400 16.400 ;
        RECT 97.200 13.600 98.000 14.400 ;
        RECT 110.000 13.600 110.800 14.400 ;
        RECT 110.100 12.400 110.700 13.600 ;
        RECT 121.300 12.400 121.900 23.600 ;
        RECT 126.100 18.400 126.700 31.600 ;
        RECT 132.500 30.400 133.100 35.600 ;
        RECT 145.300 32.400 145.900 51.600 ;
        RECT 148.400 49.600 149.200 50.400 ;
        RECT 150.100 48.400 150.700 57.600 ;
        RECT 151.700 56.400 152.300 63.600 ;
        RECT 156.500 58.400 157.100 65.600 ;
        RECT 158.000 63.600 158.800 64.400 ;
        RECT 158.100 58.400 158.700 63.600 ;
        RECT 159.700 58.400 160.300 65.600 ;
        RECT 156.400 57.600 157.200 58.400 ;
        RECT 158.000 57.600 158.800 58.400 ;
        RECT 159.600 57.600 160.400 58.400 ;
        RECT 151.600 55.600 152.400 56.400 ;
        RECT 159.700 54.400 160.300 57.600 ;
        RECT 159.600 53.600 160.400 54.400 ;
        RECT 150.000 47.600 150.800 48.400 ;
        RECT 134.000 31.600 134.800 32.400 ;
        RECT 145.200 31.600 146.000 32.400 ;
        RECT 148.400 31.600 149.200 32.400 ;
        RECT 129.200 29.600 130.000 30.400 ;
        RECT 132.400 29.600 133.200 30.400 ;
        RECT 132.400 27.600 133.200 28.400 ;
        RECT 127.600 25.600 128.400 26.400 ;
        RECT 132.500 18.400 133.100 27.600 ;
        RECT 134.100 26.400 134.700 31.600 ;
        RECT 150.100 30.400 150.700 47.600 ;
        RECT 151.600 43.600 152.400 44.400 ;
        RECT 154.800 43.600 155.600 44.400 ;
        RECT 138.800 29.600 139.600 30.400 ;
        RECT 140.400 29.600 141.200 30.400 ;
        RECT 145.200 29.600 146.000 30.400 ;
        RECT 148.400 29.600 149.200 30.400 ;
        RECT 150.000 29.600 150.800 30.400 ;
        RECT 137.200 27.600 138.000 28.400 ;
        RECT 134.000 25.600 134.800 26.400 ;
        RECT 135.600 23.600 136.400 24.400 ;
        RECT 126.000 17.600 126.800 18.400 ;
        RECT 132.400 17.600 133.200 18.400 ;
        RECT 134.000 17.600 134.800 18.400 ;
        RECT 134.100 16.400 134.700 17.600 ;
        RECT 134.000 15.600 134.800 16.400 ;
        RECT 129.200 13.600 130.000 14.400 ;
        RECT 129.300 12.400 129.900 13.600 ;
        RECT 87.600 11.600 88.400 12.400 ;
        RECT 90.800 11.600 91.600 12.400 ;
        RECT 92.400 11.600 93.200 12.400 ;
        RECT 94.000 11.600 94.800 12.400 ;
        RECT 95.600 11.600 96.400 12.400 ;
        RECT 110.000 11.600 110.800 12.400 ;
        RECT 119.600 11.600 120.400 12.400 ;
        RECT 121.200 11.600 122.000 12.400 ;
        RECT 127.600 11.600 128.400 12.400 ;
        RECT 129.200 11.600 130.000 12.400 ;
        RECT 92.500 10.400 93.100 11.600 ;
        RECT 119.700 10.400 120.300 11.600 ;
        RECT 121.300 10.400 121.900 11.600 ;
        RECT 135.700 10.400 136.300 23.600 ;
        RECT 140.500 16.400 141.100 29.600 ;
        RECT 150.100 26.400 150.700 29.600 ;
        RECT 151.700 28.400 152.300 43.600 ;
        RECT 151.600 27.600 152.400 28.400 ;
        RECT 154.900 26.400 155.500 43.600 ;
        RECT 156.400 31.600 157.200 32.400 ;
        RECT 156.500 30.400 157.100 31.600 ;
        RECT 156.400 29.600 157.200 30.400 ;
        RECT 143.600 25.600 144.400 26.400 ;
        RECT 150.000 25.600 150.800 26.400 ;
        RECT 154.800 25.600 155.600 26.400 ;
        RECT 153.200 23.600 154.000 24.400 ;
        RECT 153.300 16.400 153.900 23.600 ;
        RECT 140.400 15.600 141.200 16.400 ;
        RECT 142.000 15.600 142.800 16.400 ;
        RECT 145.200 15.600 146.000 16.400 ;
        RECT 150.000 15.600 150.800 16.400 ;
        RECT 153.200 15.600 154.000 16.400 ;
        RECT 137.200 13.600 138.000 14.400 ;
        RECT 142.100 12.400 142.700 15.600 ;
        RECT 150.100 14.400 150.700 15.600 ;
        RECT 150.000 13.600 150.800 14.400 ;
        RECT 156.400 13.600 157.200 14.400 ;
        RECT 156.500 12.400 157.100 13.600 ;
        RECT 138.800 11.600 139.600 12.400 ;
        RECT 142.000 11.600 142.800 12.400 ;
        RECT 146.800 11.600 147.600 12.400 ;
        RECT 156.400 11.600 157.200 12.400 ;
        RECT 146.900 10.400 147.500 11.600 ;
        RECT 86.000 9.600 86.800 10.400 ;
        RECT 92.400 9.600 93.200 10.400 ;
        RECT 103.600 9.600 104.400 10.400 ;
        RECT 113.200 9.600 114.000 10.400 ;
        RECT 119.600 9.600 120.400 10.400 ;
        RECT 121.200 9.600 122.000 10.400 ;
        RECT 124.400 9.600 125.200 10.400 ;
        RECT 126.000 9.600 126.800 10.400 ;
        RECT 135.600 9.600 136.400 10.400 ;
        RECT 146.800 9.600 147.600 10.400 ;
        RECT 126.100 8.400 126.700 9.600 ;
        RECT 18.800 7.600 19.600 8.400 ;
        RECT 22.000 7.600 22.800 8.400 ;
        RECT 39.600 7.600 40.400 8.400 ;
        RECT 42.800 7.600 43.600 8.400 ;
        RECT 55.600 7.600 56.400 8.400 ;
        RECT 82.800 7.600 83.600 8.400 ;
        RECT 122.800 7.600 123.600 8.400 ;
        RECT 126.000 7.600 126.800 8.400 ;
        RECT 122.900 6.400 123.500 7.600 ;
        RECT 79.600 5.600 80.400 6.400 ;
        RECT 122.800 5.600 123.600 6.400 ;
      LAYER metal3 ;
        RECT 98.800 98.300 99.600 98.400 ;
        RECT 113.200 98.300 114.000 98.400 ;
        RECT 98.800 97.700 114.000 98.300 ;
        RECT 98.800 97.600 99.600 97.700 ;
        RECT 113.200 97.600 114.000 97.700 ;
        RECT 95.600 96.300 96.400 96.400 ;
        RECT 100.400 96.300 101.200 96.400 ;
        RECT 95.600 95.700 101.200 96.300 ;
        RECT 95.600 95.600 96.400 95.700 ;
        RECT 100.400 95.600 101.200 95.700 ;
        RECT 130.800 96.300 131.600 96.400 ;
        RECT 137.200 96.300 138.000 96.400 ;
        RECT 130.800 95.700 138.000 96.300 ;
        RECT 130.800 95.600 131.600 95.700 ;
        RECT 137.200 95.600 138.000 95.700 ;
        RECT 140.400 96.300 141.200 96.400 ;
        RECT 158.000 96.300 158.800 96.400 ;
        RECT 140.400 95.700 158.800 96.300 ;
        RECT 140.400 95.600 141.200 95.700 ;
        RECT 158.000 95.600 158.800 95.700 ;
        RECT 7.600 94.300 8.400 94.400 ;
        RECT 20.400 94.300 21.200 94.400 ;
        RECT 23.600 94.300 24.400 94.400 ;
        RECT 7.600 93.700 24.400 94.300 ;
        RECT 7.600 93.600 8.400 93.700 ;
        RECT 20.400 93.600 21.200 93.700 ;
        RECT 23.600 93.600 24.400 93.700 ;
        RECT 82.800 94.300 83.600 94.400 ;
        RECT 135.600 94.300 136.400 94.400 ;
        RECT 82.800 93.700 136.400 94.300 ;
        RECT 82.800 93.600 83.600 93.700 ;
        RECT 135.600 93.600 136.400 93.700 ;
        RECT 143.600 94.300 144.400 94.400 ;
        RECT 151.600 94.300 152.400 94.400 ;
        RECT 143.600 93.700 152.400 94.300 ;
        RECT 143.600 93.600 144.400 93.700 ;
        RECT 151.600 93.600 152.400 93.700 ;
        RECT 132.400 92.300 133.200 92.400 ;
        RECT 153.200 92.300 154.000 92.400 ;
        RECT 132.400 91.700 154.000 92.300 ;
        RECT 132.400 91.600 133.200 91.700 ;
        RECT 153.200 91.600 154.000 91.700 ;
        RECT 73.200 90.300 74.000 90.400 ;
        RECT 102.000 90.300 102.800 90.400 ;
        RECT 146.800 90.300 147.600 90.400 ;
        RECT 73.200 89.700 147.600 90.300 ;
        RECT 73.200 89.600 74.000 89.700 ;
        RECT 102.000 89.600 102.800 89.700 ;
        RECT 146.800 89.600 147.600 89.700 ;
        RECT 4.400 88.300 5.200 88.400 ;
        RECT 23.600 88.300 24.400 88.400 ;
        RECT 4.400 87.700 24.400 88.300 ;
        RECT 4.400 87.600 5.200 87.700 ;
        RECT 23.600 87.600 24.400 87.700 ;
        RECT 34.800 88.300 35.600 88.400 ;
        RECT 38.000 88.300 38.800 88.400 ;
        RECT 49.200 88.300 50.000 88.400 ;
        RECT 34.800 87.700 50.000 88.300 ;
        RECT 34.800 87.600 35.600 87.700 ;
        RECT 38.000 87.600 38.800 87.700 ;
        RECT 49.200 87.600 50.000 87.700 ;
        RECT 62.000 88.300 62.800 88.400 ;
        RECT 71.600 88.300 72.400 88.400 ;
        RECT 74.800 88.300 75.600 88.400 ;
        RECT 62.000 87.700 75.600 88.300 ;
        RECT 62.000 87.600 62.800 87.700 ;
        RECT 71.600 87.600 72.400 87.700 ;
        RECT 74.800 87.600 75.600 87.700 ;
        RECT 78.000 88.300 78.800 88.400 ;
        RECT 82.800 88.300 83.600 88.400 ;
        RECT 78.000 87.700 83.600 88.300 ;
        RECT 78.000 87.600 78.800 87.700 ;
        RECT 82.800 87.600 83.600 87.700 ;
        RECT 95.600 88.300 96.400 88.400 ;
        RECT 132.400 88.300 133.200 88.400 ;
        RECT 95.600 87.700 133.200 88.300 ;
        RECT 95.600 87.600 96.400 87.700 ;
        RECT 132.400 87.600 133.200 87.700 ;
        RECT 23.700 86.300 24.300 87.600 ;
        RECT 41.200 86.300 42.000 86.400 ;
        RECT 66.800 86.300 67.600 86.400 ;
        RECT 23.700 85.700 67.600 86.300 ;
        RECT 41.200 85.600 42.000 85.700 ;
        RECT 66.800 85.600 67.600 85.700 ;
        RECT 82.800 86.300 83.600 86.400 ;
        RECT 124.400 86.300 125.200 86.400 ;
        RECT 82.800 85.700 125.200 86.300 ;
        RECT 82.800 85.600 83.600 85.700 ;
        RECT 124.400 85.600 125.200 85.700 ;
        RECT 17.200 84.300 18.000 84.400 ;
        RECT 86.000 84.300 86.800 84.400 ;
        RECT 17.200 83.700 86.800 84.300 ;
        RECT 17.200 83.600 18.000 83.700 ;
        RECT 86.000 83.600 86.800 83.700 ;
        RECT 50.800 82.300 51.600 82.400 ;
        RECT 55.600 82.300 56.400 82.400 ;
        RECT 73.200 82.300 74.000 82.400 ;
        RECT 50.800 81.700 74.000 82.300 ;
        RECT 50.800 81.600 51.600 81.700 ;
        RECT 55.600 81.600 56.400 81.700 ;
        RECT 73.200 81.600 74.000 81.700 ;
        RECT 68.400 80.300 69.200 80.400 ;
        RECT 76.400 80.300 77.200 80.400 ;
        RECT 119.600 80.300 120.400 80.400 ;
        RECT 132.400 80.300 133.200 80.400 ;
        RECT 146.800 80.300 147.600 80.400 ;
        RECT 68.400 79.700 147.600 80.300 ;
        RECT 68.400 79.600 69.200 79.700 ;
        RECT 76.400 79.600 77.200 79.700 ;
        RECT 119.600 79.600 120.400 79.700 ;
        RECT 132.400 79.600 133.200 79.700 ;
        RECT 146.800 79.600 147.600 79.700 ;
        RECT 10.800 78.300 11.600 78.400 ;
        RECT 58.800 78.300 59.600 78.400 ;
        RECT 10.800 77.700 59.600 78.300 ;
        RECT 10.800 77.600 11.600 77.700 ;
        RECT 58.800 77.600 59.600 77.700 ;
        RECT 92.400 78.300 93.200 78.400 ;
        RECT 129.200 78.300 130.000 78.400 ;
        RECT 92.400 77.700 130.000 78.300 ;
        RECT 92.400 77.600 93.200 77.700 ;
        RECT 129.200 77.600 130.000 77.700 ;
        RECT 52.400 76.300 53.200 76.400 ;
        RECT 60.400 76.300 61.200 76.400 ;
        RECT 76.400 76.300 77.200 76.400 ;
        RECT 98.800 76.300 99.600 76.400 ;
        RECT 52.400 75.700 99.600 76.300 ;
        RECT 52.400 75.600 53.200 75.700 ;
        RECT 60.400 75.600 61.200 75.700 ;
        RECT 76.400 75.600 77.200 75.700 ;
        RECT 98.800 75.600 99.600 75.700 ;
        RECT 17.200 74.300 18.000 74.400 ;
        RECT 26.800 74.300 27.600 74.400 ;
        RECT 54.000 74.300 54.800 74.400 ;
        RECT 68.400 74.300 69.200 74.400 ;
        RECT 17.200 73.700 69.200 74.300 ;
        RECT 17.200 73.600 18.000 73.700 ;
        RECT 26.800 73.600 27.600 73.700 ;
        RECT 54.000 73.600 54.800 73.700 ;
        RECT 68.400 73.600 69.200 73.700 ;
        RECT 94.000 74.300 94.800 74.400 ;
        RECT 126.000 74.300 126.800 74.400 ;
        RECT 94.000 73.700 126.800 74.300 ;
        RECT 94.000 73.600 94.800 73.700 ;
        RECT 126.000 73.600 126.800 73.700 ;
        RECT 140.400 74.300 141.200 74.400 ;
        RECT 153.200 74.300 154.000 74.400 ;
        RECT 140.400 73.700 154.000 74.300 ;
        RECT 140.400 73.600 141.200 73.700 ;
        RECT 153.200 73.600 154.000 73.700 ;
        RECT 9.200 72.300 10.000 72.400 ;
        RECT 18.800 72.300 19.600 72.400 ;
        RECT 36.400 72.300 37.200 72.400 ;
        RECT 50.800 72.300 51.600 72.400 ;
        RECT 9.200 71.700 51.600 72.300 ;
        RECT 9.200 71.600 10.000 71.700 ;
        RECT 18.800 71.600 19.600 71.700 ;
        RECT 36.400 71.600 37.200 71.700 ;
        RECT 50.800 71.600 51.600 71.700 ;
        RECT 52.400 72.300 53.200 72.400 ;
        RECT 76.400 72.300 77.200 72.400 ;
        RECT 52.400 71.700 77.200 72.300 ;
        RECT 52.400 71.600 53.200 71.700 ;
        RECT 76.400 71.600 77.200 71.700 ;
        RECT 86.000 72.300 86.800 72.400 ;
        RECT 95.600 72.300 96.400 72.400 ;
        RECT 86.000 71.700 96.400 72.300 ;
        RECT 86.000 71.600 86.800 71.700 ;
        RECT 95.600 71.600 96.400 71.700 ;
        RECT 127.600 72.300 128.400 72.400 ;
        RECT 156.400 72.300 157.200 72.400 ;
        RECT 127.600 71.700 157.200 72.300 ;
        RECT 127.600 71.600 128.400 71.700 ;
        RECT 156.400 71.600 157.200 71.700 ;
        RECT 39.600 70.300 40.400 70.400 ;
        RECT 55.600 70.300 56.400 70.400 ;
        RECT 106.800 70.300 107.600 70.400 ;
        RECT 39.600 69.700 107.600 70.300 ;
        RECT 39.600 69.600 40.400 69.700 ;
        RECT 55.600 69.600 56.400 69.700 ;
        RECT 106.800 69.600 107.600 69.700 ;
        RECT 108.400 70.300 109.200 70.400 ;
        RECT 110.000 70.300 110.800 70.400 ;
        RECT 108.400 69.700 110.800 70.300 ;
        RECT 108.400 69.600 109.200 69.700 ;
        RECT 110.000 69.600 110.800 69.700 ;
        RECT 124.400 70.300 125.200 70.400 ;
        RECT 142.000 70.300 142.800 70.400 ;
        RECT 124.400 69.700 142.800 70.300 ;
        RECT 124.400 69.600 125.200 69.700 ;
        RECT 142.000 69.600 142.800 69.700 ;
        RECT 36.400 68.300 37.200 68.400 ;
        RECT 42.800 68.300 43.600 68.400 ;
        RECT 36.400 67.700 43.600 68.300 ;
        RECT 36.400 67.600 37.200 67.700 ;
        RECT 42.800 67.600 43.600 67.700 ;
        RECT 60.400 68.300 61.200 68.400 ;
        RECT 62.000 68.300 62.800 68.400 ;
        RECT 60.400 67.700 62.800 68.300 ;
        RECT 60.400 67.600 61.200 67.700 ;
        RECT 62.000 67.600 62.800 67.700 ;
        RECT 110.000 68.300 110.800 68.400 ;
        RECT 134.000 68.300 134.800 68.400 ;
        RECT 140.400 68.300 141.200 68.400 ;
        RECT 110.000 67.700 133.100 68.300 ;
        RECT 110.000 67.600 110.800 67.700 ;
        RECT 60.400 66.300 61.200 66.400 ;
        RECT 63.600 66.300 64.400 66.400 ;
        RECT 60.400 65.700 64.400 66.300 ;
        RECT 60.400 65.600 61.200 65.700 ;
        RECT 63.600 65.600 64.400 65.700 ;
        RECT 71.600 66.300 72.400 66.400 ;
        RECT 103.600 66.300 104.400 66.400 ;
        RECT 71.600 65.700 104.400 66.300 ;
        RECT 71.600 65.600 72.400 65.700 ;
        RECT 103.600 65.600 104.400 65.700 ;
        RECT 110.000 66.300 110.800 66.400 ;
        RECT 113.200 66.300 114.000 66.400 ;
        RECT 110.000 65.700 114.000 66.300 ;
        RECT 132.500 66.300 133.100 67.700 ;
        RECT 134.000 67.700 141.200 68.300 ;
        RECT 134.000 67.600 134.800 67.700 ;
        RECT 140.400 67.600 141.200 67.700 ;
        RECT 138.800 66.300 139.600 66.400 ;
        RECT 132.500 65.700 139.600 66.300 ;
        RECT 110.000 65.600 110.800 65.700 ;
        RECT 113.200 65.600 114.000 65.700 ;
        RECT 138.800 65.600 139.600 65.700 ;
        RECT 30.000 64.300 30.800 64.400 ;
        RECT 57.200 64.300 58.000 64.400 ;
        RECT 30.000 63.700 58.000 64.300 ;
        RECT 30.000 63.600 30.800 63.700 ;
        RECT 57.200 63.600 58.000 63.700 ;
        RECT 58.800 64.300 59.600 64.400 ;
        RECT 86.000 64.300 86.800 64.400 ;
        RECT 58.800 63.700 86.800 64.300 ;
        RECT 58.800 63.600 59.600 63.700 ;
        RECT 86.000 63.600 86.800 63.700 ;
        RECT 89.200 64.300 90.000 64.400 ;
        RECT 102.000 64.300 102.800 64.400 ;
        RECT 89.200 63.700 102.800 64.300 ;
        RECT 103.700 64.300 104.300 65.600 ;
        RECT 111.600 64.300 112.400 64.400 ;
        RECT 103.700 63.700 112.400 64.300 ;
        RECT 89.200 63.600 90.000 63.700 ;
        RECT 102.000 63.600 102.800 63.700 ;
        RECT 111.600 63.600 112.400 63.700 ;
        RECT 20.400 62.300 21.200 62.400 ;
        RECT 23.600 62.300 24.400 62.400 ;
        RECT 33.200 62.300 34.000 62.400 ;
        RECT 20.400 61.700 34.000 62.300 ;
        RECT 20.400 61.600 21.200 61.700 ;
        RECT 23.600 61.600 24.400 61.700 ;
        RECT 33.200 61.600 34.000 61.700 ;
        RECT 66.800 62.300 67.600 62.400 ;
        RECT 84.400 62.300 85.200 62.400 ;
        RECT 66.800 61.700 85.200 62.300 ;
        RECT 66.800 61.600 67.600 61.700 ;
        RECT 84.400 61.600 85.200 61.700 ;
        RECT 38.000 60.300 38.800 60.400 ;
        RECT 33.300 59.700 38.800 60.300 ;
        RECT 6.000 58.300 6.800 58.400 ;
        RECT 12.400 58.300 13.200 58.400 ;
        RECT 20.400 58.300 21.200 58.400 ;
        RECT 6.000 57.700 21.200 58.300 ;
        RECT 6.000 57.600 6.800 57.700 ;
        RECT 12.400 57.600 13.200 57.700 ;
        RECT 20.400 57.600 21.200 57.700 ;
        RECT 28.400 58.300 29.200 58.400 ;
        RECT 33.300 58.300 33.900 59.700 ;
        RECT 38.000 59.600 38.800 59.700 ;
        RECT 28.400 57.700 33.900 58.300 ;
        RECT 34.800 58.300 35.600 58.400 ;
        RECT 50.800 58.300 51.600 58.400 ;
        RECT 34.800 57.700 51.600 58.300 ;
        RECT 28.400 57.600 29.200 57.700 ;
        RECT 34.800 57.600 35.600 57.700 ;
        RECT 50.800 57.600 51.600 57.700 ;
        RECT 52.400 58.300 53.200 58.400 ;
        RECT 58.800 58.300 59.600 58.400 ;
        RECT 52.400 57.700 59.600 58.300 ;
        RECT 52.400 57.600 53.200 57.700 ;
        RECT 58.800 57.600 59.600 57.700 ;
        RECT 62.000 58.300 62.800 58.400 ;
        RECT 73.200 58.300 74.000 58.400 ;
        RECT 62.000 57.700 74.000 58.300 ;
        RECT 62.000 57.600 62.800 57.700 ;
        RECT 73.200 57.600 74.000 57.700 ;
        RECT 84.400 58.300 85.200 58.400 ;
        RECT 121.200 58.300 122.000 58.400 ;
        RECT 84.400 57.700 122.000 58.300 ;
        RECT 84.400 57.600 85.200 57.700 ;
        RECT 121.200 57.600 122.000 57.700 ;
        RECT 124.400 58.300 125.200 58.400 ;
        RECT 143.600 58.300 144.400 58.400 ;
        RECT 124.400 57.700 144.400 58.300 ;
        RECT 124.400 57.600 125.200 57.700 ;
        RECT 143.600 57.600 144.400 57.700 ;
        RECT 150.000 58.300 150.800 58.400 ;
        RECT 158.000 58.300 158.800 58.400 ;
        RECT 150.000 57.700 158.800 58.300 ;
        RECT 150.000 57.600 150.800 57.700 ;
        RECT 158.000 57.600 158.800 57.700 ;
        RECT 17.200 56.300 18.000 56.400 ;
        RECT 38.000 56.300 38.800 56.400 ;
        RECT 17.200 55.700 38.800 56.300 ;
        RECT 17.200 55.600 18.000 55.700 ;
        RECT 38.000 55.600 38.800 55.700 ;
        RECT 41.200 56.300 42.000 56.400 ;
        RECT 49.200 56.300 50.000 56.400 ;
        RECT 41.200 55.700 50.000 56.300 ;
        RECT 41.200 55.600 42.000 55.700 ;
        RECT 49.200 55.600 50.000 55.700 ;
        RECT 57.200 56.300 58.000 56.400 ;
        RECT 66.800 56.300 67.600 56.400 ;
        RECT 57.200 55.700 67.600 56.300 ;
        RECT 57.200 55.600 58.000 55.700 ;
        RECT 66.800 55.600 67.600 55.700 ;
        RECT 68.400 56.300 69.200 56.400 ;
        RECT 71.600 56.300 72.400 56.400 ;
        RECT 68.400 55.700 72.400 56.300 ;
        RECT 68.400 55.600 69.200 55.700 ;
        RECT 71.600 55.600 72.400 55.700 ;
        RECT 76.400 56.300 77.200 56.400 ;
        RECT 78.000 56.300 78.800 56.400 ;
        RECT 76.400 55.700 78.800 56.300 ;
        RECT 76.400 55.600 77.200 55.700 ;
        RECT 78.000 55.600 78.800 55.700 ;
        RECT 82.800 56.300 83.600 56.400 ;
        RECT 90.800 56.300 91.600 56.400 ;
        RECT 100.400 56.300 101.200 56.400 ;
        RECT 82.800 55.700 101.200 56.300 ;
        RECT 82.800 55.600 83.600 55.700 ;
        RECT 90.800 55.600 91.600 55.700 ;
        RECT 100.400 55.600 101.200 55.700 ;
        RECT 130.800 56.300 131.600 56.400 ;
        RECT 143.600 56.300 144.400 56.400 ;
        RECT 130.800 55.700 144.400 56.300 ;
        RECT 130.800 55.600 131.600 55.700 ;
        RECT 143.600 55.600 144.400 55.700 ;
        RECT 146.800 56.300 147.600 56.400 ;
        RECT 151.600 56.300 152.400 56.400 ;
        RECT 146.800 55.700 152.400 56.300 ;
        RECT 146.800 55.600 147.600 55.700 ;
        RECT 151.600 55.600 152.400 55.700 ;
        RECT 95.600 54.300 96.400 54.400 ;
        RECT 103.600 54.300 104.400 54.400 ;
        RECT 95.600 53.700 104.400 54.300 ;
        RECT 95.600 53.600 96.400 53.700 ;
        RECT 103.600 53.600 104.400 53.700 ;
        RECT 119.600 54.300 120.400 54.400 ;
        RECT 127.600 54.300 128.400 54.400 ;
        RECT 119.600 53.700 128.400 54.300 ;
        RECT 119.600 53.600 120.400 53.700 ;
        RECT 127.600 53.600 128.400 53.700 ;
        RECT 134.000 54.300 134.800 54.400 ;
        RECT 140.400 54.300 141.200 54.400 ;
        RECT 159.600 54.300 160.400 54.400 ;
        RECT 134.000 53.700 160.400 54.300 ;
        RECT 134.000 53.600 134.800 53.700 ;
        RECT 140.400 53.600 141.200 53.700 ;
        RECT 159.600 53.600 160.400 53.700 ;
        RECT 25.200 50.300 26.000 50.400 ;
        RECT 34.800 50.300 35.600 50.400 ;
        RECT 41.200 50.300 42.000 50.400 ;
        RECT 25.200 49.700 42.000 50.300 ;
        RECT 25.200 49.600 26.000 49.700 ;
        RECT 34.800 49.600 35.600 49.700 ;
        RECT 41.200 49.600 42.000 49.700 ;
        RECT 50.800 50.300 51.600 50.400 ;
        RECT 60.400 50.300 61.200 50.400 ;
        RECT 50.800 49.700 61.200 50.300 ;
        RECT 50.800 49.600 51.600 49.700 ;
        RECT 60.400 49.600 61.200 49.700 ;
        RECT 79.600 50.300 80.400 50.400 ;
        RECT 114.800 50.300 115.600 50.400 ;
        RECT 79.600 49.700 115.600 50.300 ;
        RECT 79.600 49.600 80.400 49.700 ;
        RECT 114.800 49.600 115.600 49.700 ;
        RECT 118.000 50.300 118.800 50.400 ;
        RECT 122.800 50.300 123.600 50.400 ;
        RECT 118.000 49.700 123.600 50.300 ;
        RECT 118.000 49.600 118.800 49.700 ;
        RECT 122.800 49.600 123.600 49.700 ;
        RECT 126.000 50.300 126.800 50.400 ;
        RECT 137.200 50.300 138.000 50.400 ;
        RECT 126.000 49.700 138.000 50.300 ;
        RECT 126.000 49.600 126.800 49.700 ;
        RECT 137.200 49.600 138.000 49.700 ;
        RECT 143.600 50.300 144.400 50.400 ;
        RECT 148.400 50.300 149.200 50.400 ;
        RECT 143.600 49.700 149.200 50.300 ;
        RECT 143.600 49.600 144.400 49.700 ;
        RECT 148.400 49.600 149.200 49.700 ;
        RECT 36.400 48.300 37.200 48.400 ;
        RECT 54.000 48.300 54.800 48.400 ;
        RECT 36.400 47.700 54.800 48.300 ;
        RECT 36.400 47.600 37.200 47.700 ;
        RECT 54.000 47.600 54.800 47.700 ;
        RECT 116.400 48.300 117.200 48.400 ;
        RECT 150.000 48.300 150.800 48.400 ;
        RECT 116.400 47.700 150.800 48.300 ;
        RECT 116.400 47.600 117.200 47.700 ;
        RECT 150.000 47.600 150.800 47.700 ;
        RECT 41.200 46.300 42.000 46.400 ;
        RECT 79.600 46.300 80.400 46.400 ;
        RECT 41.200 45.700 80.400 46.300 ;
        RECT 41.200 45.600 42.000 45.700 ;
        RECT 79.600 45.600 80.400 45.700 ;
        RECT 102.000 46.300 102.800 46.400 ;
        RECT 127.600 46.300 128.400 46.400 ;
        RECT 129.200 46.300 130.000 46.400 ;
        RECT 102.000 45.700 130.000 46.300 ;
        RECT 102.000 45.600 102.800 45.700 ;
        RECT 127.600 45.600 128.400 45.700 ;
        RECT 129.200 45.600 130.000 45.700 ;
        RECT 39.600 44.300 40.400 44.400 ;
        RECT 52.400 44.300 53.200 44.400 ;
        RECT 39.600 43.700 53.200 44.300 ;
        RECT 39.600 43.600 40.400 43.700 ;
        RECT 52.400 43.600 53.200 43.700 ;
        RECT 4.400 42.300 5.200 42.400 ;
        RECT 41.200 42.300 42.000 42.400 ;
        RECT 4.400 41.700 42.000 42.300 ;
        RECT 4.400 41.600 5.200 41.700 ;
        RECT 41.200 41.600 42.000 41.700 ;
        RECT 31.600 38.300 32.400 38.400 ;
        RECT 55.600 38.300 56.400 38.400 ;
        RECT 31.600 37.700 56.400 38.300 ;
        RECT 31.600 37.600 32.400 37.700 ;
        RECT 55.600 37.600 56.400 37.700 ;
        RECT 78.000 38.300 78.800 38.400 ;
        RECT 89.200 38.300 90.000 38.400 ;
        RECT 78.000 37.700 90.000 38.300 ;
        RECT 78.000 37.600 78.800 37.700 ;
        RECT 89.200 37.600 90.000 37.700 ;
        RECT 20.400 36.300 21.200 36.400 ;
        RECT 90.800 36.300 91.600 36.400 ;
        RECT 97.200 36.300 98.000 36.400 ;
        RECT 20.400 35.700 98.000 36.300 ;
        RECT 20.400 35.600 21.200 35.700 ;
        RECT 90.800 35.600 91.600 35.700 ;
        RECT 97.200 35.600 98.000 35.700 ;
        RECT 105.200 36.300 106.000 36.400 ;
        RECT 132.400 36.300 133.200 36.400 ;
        RECT 135.600 36.300 136.400 36.400 ;
        RECT 105.200 35.700 136.400 36.300 ;
        RECT 105.200 35.600 106.000 35.700 ;
        RECT 132.400 35.600 133.200 35.700 ;
        RECT 135.600 35.600 136.400 35.700 ;
        RECT 23.600 34.300 24.400 34.400 ;
        RECT 60.400 34.300 61.200 34.400 ;
        RECT 63.600 34.300 64.400 34.400 ;
        RECT 23.600 33.700 64.400 34.300 ;
        RECT 23.600 33.600 24.400 33.700 ;
        RECT 60.400 33.600 61.200 33.700 ;
        RECT 63.600 33.600 64.400 33.700 ;
        RECT 87.600 34.300 88.400 34.400 ;
        RECT 102.000 34.300 102.800 34.400 ;
        RECT 87.600 33.700 102.800 34.300 ;
        RECT 87.600 33.600 88.400 33.700 ;
        RECT 102.000 33.600 102.800 33.700 ;
        RECT 108.400 34.300 109.200 34.400 ;
        RECT 114.800 34.300 115.600 34.400 ;
        RECT 108.400 33.700 115.600 34.300 ;
        RECT 108.400 33.600 109.200 33.700 ;
        RECT 114.800 33.600 115.600 33.700 ;
        RECT 31.600 32.300 32.400 32.400 ;
        RECT 50.800 32.300 51.600 32.400 ;
        RECT 60.400 32.300 61.200 32.400 ;
        RECT 70.000 32.300 70.800 32.400 ;
        RECT 31.600 31.700 70.800 32.300 ;
        RECT 31.600 31.600 32.400 31.700 ;
        RECT 50.800 31.600 51.600 31.700 ;
        RECT 60.400 31.600 61.200 31.700 ;
        RECT 70.000 31.600 70.800 31.700 ;
        RECT 84.400 32.300 85.200 32.400 ;
        RECT 89.200 32.300 90.000 32.400 ;
        RECT 94.000 32.300 94.800 32.400 ;
        RECT 84.400 31.700 94.800 32.300 ;
        RECT 84.400 31.600 85.200 31.700 ;
        RECT 89.200 31.600 90.000 31.700 ;
        RECT 94.000 31.600 94.800 31.700 ;
        RECT 97.200 32.300 98.000 32.400 ;
        RECT 105.200 32.300 106.000 32.400 ;
        RECT 97.200 31.700 106.000 32.300 ;
        RECT 97.200 31.600 98.000 31.700 ;
        RECT 105.200 31.600 106.000 31.700 ;
        RECT 127.600 32.300 128.400 32.400 ;
        RECT 134.000 32.300 134.800 32.400 ;
        RECT 127.600 31.700 134.800 32.300 ;
        RECT 127.600 31.600 128.400 31.700 ;
        RECT 134.000 31.600 134.800 31.700 ;
        RECT 148.400 32.300 149.200 32.400 ;
        RECT 156.400 32.300 157.200 32.400 ;
        RECT 148.400 31.700 157.200 32.300 ;
        RECT 148.400 31.600 149.200 31.700 ;
        RECT 156.400 31.600 157.200 31.700 ;
        RECT 34.800 30.300 35.600 30.400 ;
        RECT 39.600 30.300 40.400 30.400 ;
        RECT 34.800 29.700 40.400 30.300 ;
        RECT 34.800 29.600 35.600 29.700 ;
        RECT 39.600 29.600 40.400 29.700 ;
        RECT 52.400 30.300 53.200 30.400 ;
        RECT 62.000 30.300 62.800 30.400 ;
        RECT 71.600 30.300 72.400 30.400 ;
        RECT 52.400 29.700 72.400 30.300 ;
        RECT 52.400 29.600 53.200 29.700 ;
        RECT 62.000 29.600 62.800 29.700 ;
        RECT 71.600 29.600 72.400 29.700 ;
        RECT 79.600 30.300 80.400 30.400 ;
        RECT 92.400 30.300 93.200 30.400 ;
        RECT 98.800 30.300 99.600 30.400 ;
        RECT 103.600 30.300 104.400 30.400 ;
        RECT 79.600 29.700 104.400 30.300 ;
        RECT 79.600 29.600 80.400 29.700 ;
        RECT 92.400 29.600 93.200 29.700 ;
        RECT 98.800 29.600 99.600 29.700 ;
        RECT 103.600 29.600 104.400 29.700 ;
        RECT 108.400 30.300 109.200 30.400 ;
        RECT 124.400 30.300 125.200 30.400 ;
        RECT 108.400 29.700 125.200 30.300 ;
        RECT 108.400 29.600 109.200 29.700 ;
        RECT 124.400 29.600 125.200 29.700 ;
        RECT 129.200 30.300 130.000 30.400 ;
        RECT 138.800 30.300 139.600 30.400 ;
        RECT 129.200 29.700 139.600 30.300 ;
        RECT 129.200 29.600 130.000 29.700 ;
        RECT 138.800 29.600 139.600 29.700 ;
        RECT 145.200 30.300 146.000 30.400 ;
        RECT 148.400 30.300 149.200 30.400 ;
        RECT 145.200 29.700 149.200 30.300 ;
        RECT 145.200 29.600 146.000 29.700 ;
        RECT 148.400 29.600 149.200 29.700 ;
        RECT 38.000 28.300 38.800 28.400 ;
        RECT 44.400 28.300 45.200 28.400 ;
        RECT 38.000 27.700 45.200 28.300 ;
        RECT 38.000 27.600 38.800 27.700 ;
        RECT 44.400 27.600 45.200 27.700 ;
        RECT 74.800 28.300 75.600 28.400 ;
        RECT 79.600 28.300 80.400 28.400 ;
        RECT 74.800 27.700 80.400 28.300 ;
        RECT 74.800 27.600 75.600 27.700 ;
        RECT 79.600 27.600 80.400 27.700 ;
        RECT 82.800 28.300 83.600 28.400 ;
        RECT 86.000 28.300 86.800 28.400 ;
        RECT 82.800 27.700 86.800 28.300 ;
        RECT 82.800 27.600 83.600 27.700 ;
        RECT 86.000 27.600 86.800 27.700 ;
        RECT 97.200 28.300 98.000 28.400 ;
        RECT 111.600 28.300 112.400 28.400 ;
        RECT 122.800 28.300 123.600 28.400 ;
        RECT 97.200 27.700 123.600 28.300 ;
        RECT 97.200 27.600 98.000 27.700 ;
        RECT 111.600 27.600 112.400 27.700 ;
        RECT 122.800 27.600 123.600 27.700 ;
        RECT 124.400 28.300 125.200 28.400 ;
        RECT 137.200 28.300 138.000 28.400 ;
        RECT 124.400 27.700 138.000 28.300 ;
        RECT 124.400 27.600 125.200 27.700 ;
        RECT 137.200 27.600 138.000 27.700 ;
        RECT 31.600 26.300 32.400 26.400 ;
        RECT 34.800 26.300 35.600 26.400 ;
        RECT 38.000 26.300 38.800 26.400 ;
        RECT 31.600 25.700 38.800 26.300 ;
        RECT 31.600 25.600 32.400 25.700 ;
        RECT 34.800 25.600 35.600 25.700 ;
        RECT 38.000 25.600 38.800 25.700 ;
        RECT 100.400 26.300 101.200 26.400 ;
        RECT 110.000 26.300 110.800 26.400 ;
        RECT 100.400 25.700 110.800 26.300 ;
        RECT 100.400 25.600 101.200 25.700 ;
        RECT 110.000 25.600 110.800 25.700 ;
        RECT 127.600 25.600 128.400 26.400 ;
        RECT 143.600 26.300 144.400 26.400 ;
        RECT 150.000 26.300 150.800 26.400 ;
        RECT 143.600 25.700 150.800 26.300 ;
        RECT 143.600 25.600 144.400 25.700 ;
        RECT 150.000 25.600 150.800 25.700 ;
        RECT 17.200 24.300 18.000 24.400 ;
        RECT 73.200 24.300 74.000 24.400 ;
        RECT 17.200 23.700 74.000 24.300 ;
        RECT 17.200 23.600 18.000 23.700 ;
        RECT 73.200 23.600 74.000 23.700 ;
        RECT 113.200 24.300 114.000 24.400 ;
        RECT 121.200 24.300 122.000 24.400 ;
        RECT 113.200 23.700 122.000 24.300 ;
        RECT 113.200 23.600 114.000 23.700 ;
        RECT 121.200 23.600 122.000 23.700 ;
        RECT 28.400 22.300 29.200 22.400 ;
        RECT 33.200 22.300 34.000 22.400 ;
        RECT 28.400 21.700 34.000 22.300 ;
        RECT 28.400 21.600 29.200 21.700 ;
        RECT 33.200 21.600 34.000 21.700 ;
        RECT 6.000 18.300 6.800 18.400 ;
        RECT 14.000 18.300 14.800 18.400 ;
        RECT 33.200 18.300 34.000 18.400 ;
        RECT 39.600 18.300 40.400 18.400 ;
        RECT 6.000 17.700 40.400 18.300 ;
        RECT 6.000 17.600 6.800 17.700 ;
        RECT 14.000 17.600 14.800 17.700 ;
        RECT 33.200 17.600 34.000 17.700 ;
        RECT 39.600 17.600 40.400 17.700 ;
        RECT 68.400 18.300 69.200 18.400 ;
        RECT 90.800 18.300 91.600 18.400 ;
        RECT 95.600 18.300 96.400 18.400 ;
        RECT 68.400 17.700 96.400 18.300 ;
        RECT 68.400 17.600 69.200 17.700 ;
        RECT 90.800 17.600 91.600 17.700 ;
        RECT 95.600 17.600 96.400 17.700 ;
        RECT 126.000 18.300 126.800 18.400 ;
        RECT 134.000 18.300 134.800 18.400 ;
        RECT 126.000 17.700 145.900 18.300 ;
        RECT 126.000 17.600 126.800 17.700 ;
        RECT 134.000 17.600 134.800 17.700 ;
        RECT 145.300 16.400 145.900 17.700 ;
        RECT 65.200 16.300 66.000 16.400 ;
        RECT 68.400 16.300 69.200 16.400 ;
        RECT 74.800 16.300 75.600 16.400 ;
        RECT 65.200 15.700 75.600 16.300 ;
        RECT 65.200 15.600 66.000 15.700 ;
        RECT 68.400 15.600 69.200 15.700 ;
        RECT 74.800 15.600 75.600 15.700 ;
        RECT 76.400 16.300 77.200 16.400 ;
        RECT 103.600 16.300 104.400 16.400 ;
        RECT 140.400 16.300 141.200 16.400 ;
        RECT 142.000 16.300 142.800 16.400 ;
        RECT 76.400 15.700 102.700 16.300 ;
        RECT 76.400 15.600 77.200 15.700 ;
        RECT 49.200 14.300 50.000 14.400 ;
        RECT 54.000 14.300 54.800 14.400 ;
        RECT 49.200 13.700 54.800 14.300 ;
        RECT 49.200 13.600 50.000 13.700 ;
        RECT 54.000 13.600 54.800 13.700 ;
        RECT 58.800 14.300 59.600 14.400 ;
        RECT 66.800 14.300 67.600 14.400 ;
        RECT 58.800 13.700 67.600 14.300 ;
        RECT 58.800 13.600 59.600 13.700 ;
        RECT 66.800 13.600 67.600 13.700 ;
        RECT 89.200 14.300 90.000 14.400 ;
        RECT 97.200 14.300 98.000 14.400 ;
        RECT 89.200 13.700 98.000 14.300 ;
        RECT 102.100 14.300 102.700 15.700 ;
        RECT 103.600 15.700 142.800 16.300 ;
        RECT 103.600 15.600 104.400 15.700 ;
        RECT 140.400 15.600 141.200 15.700 ;
        RECT 142.000 15.600 142.800 15.700 ;
        RECT 145.200 16.300 146.000 16.400 ;
        RECT 153.200 16.300 154.000 16.400 ;
        RECT 145.200 15.700 154.000 16.300 ;
        RECT 145.200 15.600 146.000 15.700 ;
        RECT 153.200 15.600 154.000 15.700 ;
        RECT 129.200 14.300 130.000 14.400 ;
        RECT 102.100 13.700 130.000 14.300 ;
        RECT 89.200 13.600 90.000 13.700 ;
        RECT 97.200 13.600 98.000 13.700 ;
        RECT 129.200 13.600 130.000 13.700 ;
        RECT 137.200 14.300 138.000 14.400 ;
        RECT 150.000 14.300 150.800 14.400 ;
        RECT 156.400 14.300 157.200 14.400 ;
        RECT 137.200 13.700 157.200 14.300 ;
        RECT 137.200 13.600 138.000 13.700 ;
        RECT 150.000 13.600 150.800 13.700 ;
        RECT 156.400 13.600 157.200 13.700 ;
        RECT 12.400 12.300 13.200 12.400 ;
        RECT 18.800 12.300 19.600 12.400 ;
        RECT 12.400 11.700 19.600 12.300 ;
        RECT 12.400 11.600 13.200 11.700 ;
        RECT 18.800 11.600 19.600 11.700 ;
        RECT 22.000 12.300 22.800 12.400 ;
        RECT 38.000 12.300 38.800 12.400 ;
        RECT 22.000 11.700 38.800 12.300 ;
        RECT 22.000 11.600 22.800 11.700 ;
        RECT 38.000 11.600 38.800 11.700 ;
        RECT 54.000 12.300 54.800 12.400 ;
        RECT 73.200 12.300 74.000 12.400 ;
        RECT 54.000 11.700 74.000 12.300 ;
        RECT 54.000 11.600 54.800 11.700 ;
        RECT 73.200 11.600 74.000 11.700 ;
        RECT 87.600 12.300 88.400 12.400 ;
        RECT 92.400 12.300 93.200 12.400 ;
        RECT 87.600 11.700 93.200 12.300 ;
        RECT 87.600 11.600 88.400 11.700 ;
        RECT 92.400 11.600 93.200 11.700 ;
        RECT 94.000 12.300 94.800 12.400 ;
        RECT 110.000 12.300 110.800 12.400 ;
        RECT 119.600 12.300 120.400 12.400 ;
        RECT 94.000 11.700 120.400 12.300 ;
        RECT 94.000 11.600 94.800 11.700 ;
        RECT 110.000 11.600 110.800 11.700 ;
        RECT 119.600 11.600 120.400 11.700 ;
        RECT 127.600 12.300 128.400 12.400 ;
        RECT 138.800 12.300 139.600 12.400 ;
        RECT 127.600 11.700 139.600 12.300 ;
        RECT 127.600 11.600 128.400 11.700 ;
        RECT 138.800 11.600 139.600 11.700 ;
        RECT 33.200 10.300 34.000 10.400 ;
        RECT 36.400 10.300 37.200 10.400 ;
        RECT 33.200 9.700 37.200 10.300 ;
        RECT 33.200 9.600 34.000 9.700 ;
        RECT 36.400 9.600 37.200 9.700 ;
        RECT 86.000 10.300 86.800 10.400 ;
        RECT 103.600 10.300 104.400 10.400 ;
        RECT 86.000 9.700 104.400 10.300 ;
        RECT 86.000 9.600 86.800 9.700 ;
        RECT 103.600 9.600 104.400 9.700 ;
        RECT 113.200 10.300 114.000 10.400 ;
        RECT 121.200 10.300 122.000 10.400 ;
        RECT 113.200 9.700 122.000 10.300 ;
        RECT 113.200 9.600 114.000 9.700 ;
        RECT 121.200 9.600 122.000 9.700 ;
        RECT 124.400 10.300 125.200 10.400 ;
        RECT 146.800 10.300 147.600 10.400 ;
        RECT 124.400 9.700 147.600 10.300 ;
        RECT 124.400 9.600 125.200 9.700 ;
        RECT 146.800 9.600 147.600 9.700 ;
        RECT 18.800 8.300 19.600 8.400 ;
        RECT 22.000 8.300 22.800 8.400 ;
        RECT 18.800 7.700 22.800 8.300 ;
        RECT 18.800 7.600 19.600 7.700 ;
        RECT 22.000 7.600 22.800 7.700 ;
        RECT 39.600 8.300 40.400 8.400 ;
        RECT 55.600 8.300 56.400 8.400 ;
        RECT 82.800 8.300 83.600 8.400 ;
        RECT 126.000 8.300 126.800 8.400 ;
        RECT 143.600 8.300 144.400 8.400 ;
        RECT 39.600 7.700 144.400 8.300 ;
        RECT 39.600 7.600 40.400 7.700 ;
        RECT 55.600 7.600 56.400 7.700 ;
        RECT 82.800 7.600 83.600 7.700 ;
        RECT 126.000 7.600 126.800 7.700 ;
        RECT 143.600 7.600 144.400 7.700 ;
        RECT 79.600 6.300 80.400 6.400 ;
        RECT 122.800 6.300 123.600 6.400 ;
        RECT 79.600 5.700 123.600 6.300 ;
        RECT 79.600 5.600 80.400 5.700 ;
        RECT 122.800 5.600 123.600 5.700 ;
      LAYER metal4 ;
        RECT 41.000 41.400 42.200 56.600 ;
        RECT 60.200 33.400 61.400 68.600 ;
        RECT 76.200 55.400 77.400 76.600 ;
        RECT 108.200 33.400 109.400 70.600 ;
        RECT 127.400 25.400 128.600 46.600 ;
        RECT 143.400 7.400 144.600 50.600 ;
  END
END alu_4bit
END LIBRARY

